VERSION 5.8 ;
BUSBITCHARS "[]" ;
DIVIDERCHAR "/" ;
UNITS
    DATABASE MICRONS 1000 ;
END UNITS

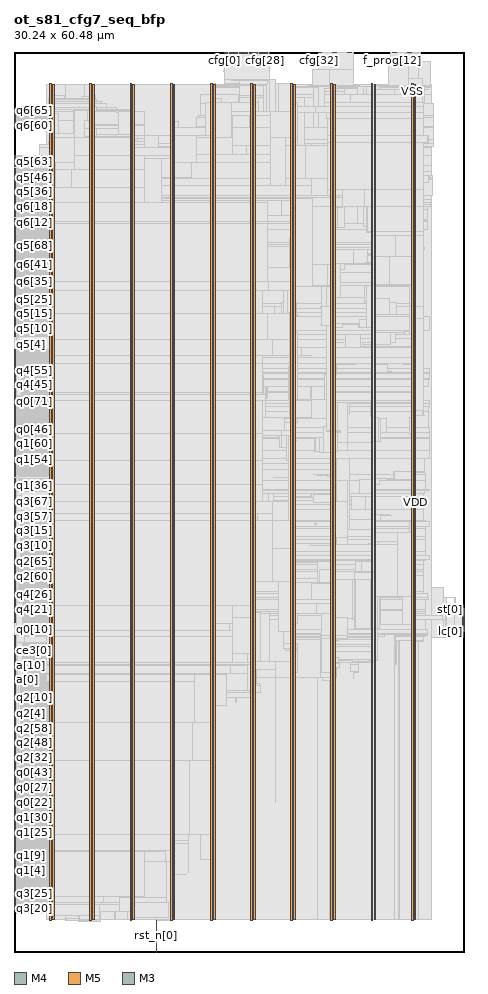
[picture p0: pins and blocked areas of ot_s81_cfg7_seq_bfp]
MACRO ot_s81_cfg7_seq_bfp
  FOREIGN ot_s81_cfg7_seq_bfp 0 0 ;
  CLASS BLOCK ;
  SIZE 30.24 BY 60.48 ;
  PIN a[0]
    DIRECTION OUTPUT ;
    USE SIGNAL ;
    PORT
      LAYER M4 ;
        RECT  0 18.288 0.084 18.312 ;
    END
  END a[0]
  PIN a[10]
    DIRECTION OUTPUT ;
    USE SIGNAL ;
    PORT
      LAYER M4 ;
        RECT  0 19.248 0.084 19.272 ;
    END
  END a[10]
  PIN a[11]
    DIRECTION OUTPUT ;
    USE SIGNAL ;
    PORT
      LAYER M4 ;
        RECT  0 19.344 0.084 19.368 ;
    END
  END a[11]
  PIN a[1]
    DIRECTION OUTPUT ;
    USE SIGNAL ;
    PORT
      LAYER M4 ;
        RECT  0 18.384 0.084 18.408 ;
    END
  END a[1]
  PIN a[2]
    DIRECTION OUTPUT ;
    USE SIGNAL ;
    PORT
      LAYER M4 ;
        RECT  0 18.48 0.084 18.504 ;
    END
  END a[2]
  PIN a[3]
    DIRECTION OUTPUT ;
    USE SIGNAL ;
    PORT
      LAYER M4 ;
        RECT  0 18.576 0.084 18.6 ;
    END
  END a[3]
  PIN a[4]
    DIRECTION OUTPUT ;
    USE SIGNAL ;
    PORT
      LAYER M4 ;
        RECT  0 18.672 0.084 18.696 ;
    END
  END a[4]
  PIN a[5]
    DIRECTION OUTPUT ;
    USE SIGNAL ;
    PORT
      LAYER M4 ;
        RECT  0 18.768 0.084 18.792 ;
    END
  END a[5]
  PIN a[6]
    DIRECTION OUTPUT ;
    USE SIGNAL ;
    PORT
      LAYER M4 ;
        RECT  0 18.864 0.084 18.888 ;
    END
  END a[6]
  PIN a[7]
    DIRECTION OUTPUT ;
    USE SIGNAL ;
    PORT
      LAYER M4 ;
        RECT  0 18.96 0.084 18.984 ;
    END
  END a[7]
  PIN a[8]
    DIRECTION OUTPUT ;
    USE SIGNAL ;
    PORT
      LAYER M4 ;
        RECT  0 19.056 0.084 19.08 ;
    END
  END a[8]
  PIN a[9]
    DIRECTION OUTPUT ;
    USE SIGNAL ;
    PORT
      LAYER M4 ;
        RECT  0 19.152 0.084 19.176 ;
    END
  END a[9]
  PIN ce0[0]
    DIRECTION OUTPUT ;
    USE SIGNAL ;
    PORT
      LAYER M4 ;
        RECT  0 19.44 0.084 19.464 ;
    END
  END ce0[0]
  PIN ce1[0]
    DIRECTION OUTPUT ;
    USE SIGNAL ;
    PORT
      LAYER M4 ;
        RECT  0 19.536 0.084 19.56 ;
    END
  END ce1[0]
  PIN ce2[0]
    DIRECTION OUTPUT ;
    USE SIGNAL ;
    PORT
      LAYER M4 ;
        RECT  0 19.632 0.084 19.656 ;
    END
  END ce2[0]
  PIN ce3[0]
    DIRECTION OUTPUT ;
    USE SIGNAL ;
    PORT
      LAYER M4 ;
        RECT  0 19.728 0.084 19.752 ;
    END
  END ce3[0]
  PIN ce4[0]
    DIRECTION OUTPUT ;
    USE SIGNAL ;
    PORT
      LAYER M4 ;
        RECT  0 19.824 0.084 19.848 ;
    END
  END ce4[0]
  PIN ce5[0]
    DIRECTION OUTPUT ;
    USE SIGNAL ;
    PORT
      LAYER M4 ;
        RECT  0 19.92 0.084 19.944 ;
    END
  END ce5[0]
  PIN ce6[0]
    DIRECTION OUTPUT ;
    USE SIGNAL ;
    PORT
      LAYER M4 ;
        RECT  0 20.016 0.084 20.04 ;
    END
  END ce6[0]
  PIN cfg[0]
    DIRECTION OUTPUT ;
    USE SIGNAL ;
    PORT
      LAYER M5 ;
        RECT  14.16 60.396 14.184 60.48 ;
    END
  END cfg[0]
  PIN cfg[10]
    DIRECTION OUTPUT ;
    USE SIGNAL ;
    PORT
      LAYER M5 ;
        RECT  15.12 60.396 15.144 60.48 ;
    END
  END cfg[10]
  PIN cfg[11]
    DIRECTION OUTPUT ;
    USE SIGNAL ;
    PORT
      LAYER M5 ;
        RECT  15.216 60.396 15.24 60.48 ;
    END
  END cfg[11]
  PIN cfg[12]
    DIRECTION OUTPUT ;
    USE SIGNAL ;
    PORT
      LAYER M5 ;
        RECT  15.312 60.396 15.336 60.48 ;
    END
  END cfg[12]
  PIN cfg[13]
    DIRECTION OUTPUT ;
    USE SIGNAL ;
    PORT
      LAYER M5 ;
        RECT  15.408 60.396 15.432 60.48 ;
    END
  END cfg[13]
  PIN cfg[14]
    DIRECTION OUTPUT ;
    USE SIGNAL ;
    PORT
      LAYER M5 ;
        RECT  15.504 60.396 15.528 60.48 ;
    END
  END cfg[14]
  PIN cfg[15]
    DIRECTION OUTPUT ;
    USE SIGNAL ;
    PORT
      LAYER M5 ;
        RECT  15.6 60.396 15.624 60.48 ;
    END
  END cfg[15]
  PIN cfg[16]
    DIRECTION OUTPUT ;
    USE SIGNAL ;
    PORT
      LAYER M5 ;
        RECT  15.696 60.396 15.72 60.48 ;
    END
  END cfg[16]
  PIN cfg[17]
    DIRECTION OUTPUT ;
    USE SIGNAL ;
    PORT
      LAYER M5 ;
        RECT  15.792 60.396 15.816 60.48 ;
    END
  END cfg[17]
  PIN cfg[18]
    DIRECTION OUTPUT ;
    USE SIGNAL ;
    PORT
      LAYER M5 ;
        RECT  15.888 60.396 15.912 60.48 ;
    END
  END cfg[18]
  PIN cfg[19]
    DIRECTION OUTPUT ;
    USE SIGNAL ;
    PORT
      LAYER M5 ;
        RECT  15.984 60.396 16.008 60.48 ;
    END
  END cfg[19]
  PIN cfg[1]
    DIRECTION OUTPUT ;
    USE SIGNAL ;
    PORT
      LAYER M5 ;
        RECT  14.256 60.396 14.28 60.48 ;
    END
  END cfg[1]
  PIN cfg[20]
    DIRECTION OUTPUT ;
    USE SIGNAL ;
    PORT
      LAYER M5 ;
        RECT  16.08 60.396 16.104 60.48 ;
    END
  END cfg[20]
  PIN cfg[21]
    DIRECTION OUTPUT ;
    USE SIGNAL ;
    PORT
      LAYER M5 ;
        RECT  16.176 60.396 16.2 60.48 ;
    END
  END cfg[21]
  PIN cfg[22]
    DIRECTION OUTPUT ;
    USE SIGNAL ;
    PORT
      LAYER M5 ;
        RECT  16.272 60.396 16.296 60.48 ;
    END
  END cfg[22]
  PIN cfg[23]
    DIRECTION OUTPUT ;
    USE SIGNAL ;
    PORT
      LAYER M5 ;
        RECT  16.368 60.396 16.392 60.48 ;
    END
  END cfg[23]
  PIN cfg[24]
    DIRECTION OUTPUT ;
    USE SIGNAL ;
    PORT
      LAYER M5 ;
        RECT  16.464 60.396 16.488 60.48 ;
    END
  END cfg[24]
  PIN cfg[25]
    DIRECTION OUTPUT ;
    USE SIGNAL ;
    PORT
      LAYER M5 ;
        RECT  16.56 60.396 16.584 60.48 ;
    END
  END cfg[25]
  PIN cfg[26]
    DIRECTION OUTPUT ;
    USE SIGNAL ;
    PORT
      LAYER M5 ;
        RECT  16.656 60.396 16.68 60.48 ;
    END
  END cfg[26]
  PIN cfg[27]
    DIRECTION OUTPUT ;
    USE SIGNAL ;
    PORT
      LAYER M5 ;
        RECT  16.752 60.396 16.776 60.48 ;
    END
  END cfg[27]
  PIN cfg[28]
    DIRECTION OUTPUT ;
    USE SIGNAL ;
    PORT
      LAYER M5 ;
        RECT  16.848 60.396 16.872 60.48 ;
    END
  END cfg[28]
  PIN cfg[29]
    DIRECTION OUTPUT ;
    USE SIGNAL ;
    PORT
      LAYER M5 ;
        RECT  16.944 60.396 16.968 60.48 ;
    END
  END cfg[29]
  PIN cfg[2]
    DIRECTION OUTPUT ;
    USE SIGNAL ;
    PORT
      LAYER M5 ;
        RECT  14.352 60.396 14.376 60.48 ;
    END
  END cfg[2]
  PIN cfg[30]
    DIRECTION OUTPUT ;
    USE SIGNAL ;
    PORT
      LAYER M5 ;
        RECT  17.04 60.396 17.064 60.48 ;
    END
  END cfg[30]
  PIN cfg[31]
    DIRECTION OUTPUT ;
    USE SIGNAL ;
    PORT
      LAYER M5 ;
        RECT  17.136 60.396 17.16 60.48 ;
    END
  END cfg[31]
  PIN cfg[32]
    DIRECTION OUTPUT ;
    USE SIGNAL ;
    PORT
      LAYER M3 ;
        RECT  20.484 60.443 20.502 60.48 ;
    END
  END cfg[32]
  PIN cfg[33]
    DIRECTION OUTPUT ;
    USE SIGNAL ;
    PORT
      LAYER M3 ;
        RECT  20.556 60.443 20.574 60.48 ;
    END
  END cfg[33]
  PIN cfg[34]
    DIRECTION OUTPUT ;
    USE SIGNAL ;
    PORT
      LAYER M3 ;
        RECT  20.628 60.443 20.646 60.48 ;
    END
  END cfg[34]
  PIN cfg[35]
    DIRECTION OUTPUT ;
    USE SIGNAL ;
    PORT
      LAYER M3 ;
        RECT  20.7 60.443 20.718 60.48 ;
    END
  END cfg[35]
  PIN cfg[36]
    DIRECTION OUTPUT ;
    USE SIGNAL ;
    PORT
      LAYER M3 ;
        RECT  20.772 60.443 20.79 60.48 ;
    END
  END cfg[36]
  PIN cfg[37]
    DIRECTION OUTPUT ;
    USE SIGNAL ;
    PORT
      LAYER M3 ;
        RECT  20.844 60.443 20.862 60.48 ;
    END
  END cfg[37]
  PIN cfg[38]
    DIRECTION OUTPUT ;
    USE SIGNAL ;
    PORT
      LAYER M3 ;
        RECT  20.916 60.443 20.934 60.48 ;
    END
  END cfg[38]
  PIN cfg[39]
    DIRECTION OUTPUT ;
    USE SIGNAL ;
    PORT
      LAYER M3 ;
        RECT  20.988 60.443 21.006 60.48 ;
    END
  END cfg[39]
  PIN cfg[3]
    DIRECTION OUTPUT ;
    USE SIGNAL ;
    PORT
      LAYER M5 ;
        RECT  14.448 60.396 14.472 60.48 ;
    END
  END cfg[3]
  PIN cfg[40]
    DIRECTION OUTPUT ;
    USE SIGNAL ;
    PORT
      LAYER M3 ;
        RECT  21.06 60.443 21.078 60.48 ;
    END
  END cfg[40]
  PIN cfg[41]
    DIRECTION OUTPUT ;
    USE SIGNAL ;
    PORT
      LAYER M3 ;
        RECT  21.132 60.443 21.15 60.48 ;
    END
  END cfg[41]
  PIN cfg[42]
    DIRECTION OUTPUT ;
    USE SIGNAL ;
    PORT
      LAYER M3 ;
        RECT  21.204 60.443 21.222 60.48 ;
    END
  END cfg[42]
  PIN cfg[43]
    DIRECTION OUTPUT ;
    USE SIGNAL ;
    PORT
      LAYER M3 ;
        RECT  21.276 60.443 21.294 60.48 ;
    END
  END cfg[43]
  PIN cfg[44]
    DIRECTION OUTPUT ;
    USE SIGNAL ;
    PORT
      LAYER M3 ;
        RECT  21.348 60.443 21.366 60.48 ;
    END
  END cfg[44]
  PIN cfg[45]
    DIRECTION OUTPUT ;
    USE SIGNAL ;
    PORT
      LAYER M3 ;
        RECT  21.42 60.443 21.438 60.48 ;
    END
  END cfg[45]
  PIN cfg[46]
    DIRECTION OUTPUT ;
    USE SIGNAL ;
    PORT
      LAYER M3 ;
        RECT  21.492 60.443 21.51 60.48 ;
    END
  END cfg[46]
  PIN cfg[47]
    DIRECTION OUTPUT ;
    USE SIGNAL ;
    PORT
      LAYER M3 ;
        RECT  21.564 60.443 21.582 60.48 ;
    END
  END cfg[47]
  PIN cfg[48]
    DIRECTION OUTPUT ;
    USE SIGNAL ;
    PORT
      LAYER M3 ;
        RECT  21.636 60.443 21.654 60.48 ;
    END
  END cfg[48]
  PIN cfg[49]
    DIRECTION OUTPUT ;
    USE SIGNAL ;
    PORT
      LAYER M3 ;
        RECT  21.708 60.443 21.726 60.48 ;
    END
  END cfg[49]
  PIN cfg[4]
    DIRECTION OUTPUT ;
    USE SIGNAL ;
    PORT
      LAYER M5 ;
        RECT  14.544 60.396 14.568 60.48 ;
    END
  END cfg[4]
  PIN cfg[50]
    DIRECTION OUTPUT ;
    USE SIGNAL ;
    PORT
      LAYER M3 ;
        RECT  21.78 60.443 21.798 60.48 ;
    END
  END cfg[50]
  PIN cfg[51]
    DIRECTION OUTPUT ;
    USE SIGNAL ;
    PORT
      LAYER M3 ;
        RECT  21.852 60.443 21.87 60.48 ;
    END
  END cfg[51]
  PIN cfg[52]
    DIRECTION OUTPUT ;
    USE SIGNAL ;
    PORT
      LAYER M3 ;
        RECT  21.924 60.443 21.942 60.48 ;
    END
  END cfg[52]
  PIN cfg[53]
    DIRECTION OUTPUT ;
    USE SIGNAL ;
    PORT
      LAYER M3 ;
        RECT  21.996 60.443 22.014 60.48 ;
    END
  END cfg[53]
  PIN cfg[5]
    DIRECTION OUTPUT ;
    USE SIGNAL ;
    PORT
      LAYER M5 ;
        RECT  14.64 60.396 14.664 60.48 ;
    END
  END cfg[5]
  PIN cfg[6]
    DIRECTION OUTPUT ;
    USE SIGNAL ;
    PORT
      LAYER M5 ;
        RECT  14.736 60.396 14.76 60.48 ;
    END
  END cfg[6]
  PIN cfg[7]
    DIRECTION OUTPUT ;
    USE SIGNAL ;
    PORT
      LAYER M5 ;
        RECT  14.832 60.396 14.856 60.48 ;
    END
  END cfg[7]
  PIN cfg[8]
    DIRECTION OUTPUT ;
    USE SIGNAL ;
    PORT
      LAYER M5 ;
        RECT  14.928 60.396 14.952 60.48 ;
    END
  END cfg[8]
  PIN cfg[9]
    DIRECTION OUTPUT ;
    USE SIGNAL ;
    PORT
      LAYER M5 ;
        RECT  15.024 60.396 15.048 60.48 ;
    END
  END cfg[9]
  PIN clk[0]
    DIRECTION INPUT ;
    USE SIGNAL ;
    PORT
      LAYER M4 ;
        RECT  0 20.112 0.084 20.136 ;
    END
  END clk[0]
  PIN f_prog[0]
    DIRECTION OUTPUT ;
    USE SIGNAL ;
    PORT
      LAYER M3 ;
        RECT  22.068 60.443 22.086 60.48 ;
    END
  END f_prog[0]
  PIN f_prog[10]
    DIRECTION OUTPUT ;
    USE SIGNAL ;
    PORT
      LAYER M3 ;
        RECT  25.308 60.443 25.326 60.48 ;
    END
  END f_prog[10]
  PIN f_prog[11]
    DIRECTION OUTPUT ;
    USE SIGNAL ;
    PORT
      LAYER M3 ;
        RECT  25.38 60.443 25.398 60.48 ;
    END
  END f_prog[11]
  PIN f_prog[12]
    DIRECTION OUTPUT ;
    USE SIGNAL ;
    PORT
      LAYER M3 ;
        RECT  25.452 60.443 25.47 60.48 ;
    END
  END f_prog[12]
  PIN f_prog[13]
    DIRECTION OUTPUT ;
    USE SIGNAL ;
    PORT
      LAYER M3 ;
        RECT  25.524 60.443 25.542 60.48 ;
    END
  END f_prog[13]
  PIN f_prog[14]
    DIRECTION OUTPUT ;
    USE SIGNAL ;
    PORT
      LAYER M3 ;
        RECT  25.596 60.443 25.614 60.48 ;
    END
  END f_prog[14]
  PIN f_prog[15]
    DIRECTION OUTPUT ;
    USE SIGNAL ;
    PORT
      LAYER M3 ;
        RECT  25.668 60.443 25.686 60.48 ;
    END
  END f_prog[15]
  PIN f_prog[16]
    DIRECTION OUTPUT ;
    USE SIGNAL ;
    PORT
      LAYER M3 ;
        RECT  25.74 60.443 25.758 60.48 ;
    END
  END f_prog[16]
  PIN f_prog[17]
    DIRECTION OUTPUT ;
    USE SIGNAL ;
    PORT
      LAYER M3 ;
        RECT  25.812 60.443 25.83 60.48 ;
    END
  END f_prog[17]
  PIN f_prog[18]
    DIRECTION OUTPUT ;
    USE SIGNAL ;
    PORT
      LAYER M3 ;
        RECT  25.884 60.443 25.902 60.48 ;
    END
  END f_prog[18]
  PIN f_prog[19]
    DIRECTION OUTPUT ;
    USE SIGNAL ;
    PORT
      LAYER M3 ;
        RECT  25.956 60.443 25.974 60.48 ;
    END
  END f_prog[19]
  PIN f_prog[1]
    DIRECTION OUTPUT ;
    USE SIGNAL ;
    PORT
      LAYER M3 ;
        RECT  22.14 60.443 22.158 60.48 ;
    END
  END f_prog[1]
  PIN f_prog[20]
    DIRECTION OUTPUT ;
    USE SIGNAL ;
    PORT
      LAYER M3 ;
        RECT  26.028 60.443 26.046 60.48 ;
    END
  END f_prog[20]
  PIN f_prog[21]
    DIRECTION OUTPUT ;
    USE SIGNAL ;
    PORT
      LAYER M3 ;
        RECT  26.1 60.443 26.118 60.48 ;
    END
  END f_prog[21]
  PIN f_prog[22]
    DIRECTION OUTPUT ;
    USE SIGNAL ;
    PORT
      LAYER M3 ;
        RECT  26.172 60.443 26.19 60.48 ;
    END
  END f_prog[22]
  PIN f_prog[23]
    DIRECTION OUTPUT ;
    USE SIGNAL ;
    PORT
      LAYER M3 ;
        RECT  26.244 60.443 26.262 60.48 ;
    END
  END f_prog[23]
  PIN f_prog[24]
    DIRECTION OUTPUT ;
    USE SIGNAL ;
    PORT
      LAYER M3 ;
        RECT  26.316 60.443 26.334 60.48 ;
    END
  END f_prog[24]
  PIN f_prog[25]
    DIRECTION OUTPUT ;
    USE SIGNAL ;
    PORT
      LAYER M3 ;
        RECT  26.388 60.443 26.406 60.48 ;
    END
  END f_prog[25]
  PIN f_prog[26]
    DIRECTION OUTPUT ;
    USE SIGNAL ;
    PORT
      LAYER M3 ;
        RECT  26.46 60.443 26.478 60.48 ;
    END
  END f_prog[26]
  PIN f_prog[27]
    DIRECTION OUTPUT ;
    USE SIGNAL ;
    PORT
      LAYER M3 ;
        RECT  26.532 60.443 26.55 60.48 ;
    END
  END f_prog[27]
  PIN f_prog[28]
    DIRECTION OUTPUT ;
    USE SIGNAL ;
    PORT
      LAYER M3 ;
        RECT  26.604 60.443 26.622 60.48 ;
    END
  END f_prog[28]
  PIN f_prog[29]
    DIRECTION OUTPUT ;
    USE SIGNAL ;
    PORT
      LAYER M3 ;
        RECT  26.676 60.443 26.694 60.48 ;
    END
  END f_prog[29]
  PIN f_prog[2]
    DIRECTION OUTPUT ;
    USE SIGNAL ;
    PORT
      LAYER M3 ;
        RECT  22.212 60.443 22.23 60.48 ;
    END
  END f_prog[2]
  PIN f_prog[30]
    DIRECTION OUTPUT ;
    USE SIGNAL ;
    PORT
      LAYER M3 ;
        RECT  26.748 60.443 26.766 60.48 ;
    END
  END f_prog[30]
  PIN f_prog[31]
    DIRECTION OUTPUT ;
    USE SIGNAL ;
    PORT
      LAYER M3 ;
        RECT  26.82 60.443 26.838 60.48 ;
    END
  END f_prog[31]
  PIN f_prog[32]
    DIRECTION OUTPUT ;
    USE SIGNAL ;
    PORT
      LAYER M3 ;
        RECT  26.892 60.443 26.91 60.48 ;
    END
  END f_prog[32]
  PIN f_prog[33]
    DIRECTION OUTPUT ;
    USE SIGNAL ;
    PORT
      LAYER M3 ;
        RECT  26.964 60.443 26.982 60.48 ;
    END
  END f_prog[33]
  PIN f_prog[34]
    DIRECTION OUTPUT ;
    USE SIGNAL ;
    PORT
      LAYER M3 ;
        RECT  27.036 60.443 27.054 60.48 ;
    END
  END f_prog[34]
  PIN f_prog[35]
    DIRECTION OUTPUT ;
    USE SIGNAL ;
    PORT
      LAYER M3 ;
        RECT  27.108 60.443 27.126 60.48 ;
    END
  END f_prog[35]
  PIN f_prog[36]
    DIRECTION OUTPUT ;
    USE SIGNAL ;
    PORT
      LAYER M3 ;
        RECT  27.18 60.443 27.198 60.48 ;
    END
  END f_prog[36]
  PIN f_prog[37]
    DIRECTION OUTPUT ;
    USE SIGNAL ;
    PORT
      LAYER M3 ;
        RECT  27.252 60.443 27.27 60.48 ;
    END
  END f_prog[37]
  PIN f_prog[3]
    DIRECTION OUTPUT ;
    USE SIGNAL ;
    PORT
      LAYER M3 ;
        RECT  22.284 60.443 22.302 60.48 ;
    END
  END f_prog[3]
  PIN f_prog[4]
    DIRECTION OUTPUT ;
    USE SIGNAL ;
    PORT
      LAYER M3 ;
        RECT  22.356 60.443 22.374 60.48 ;
    END
  END f_prog[4]
  PIN f_prog[5]
    DIRECTION OUTPUT ;
    USE SIGNAL ;
    PORT
      LAYER M3 ;
        RECT  22.428 60.443 22.446 60.48 ;
    END
  END f_prog[5]
  PIN f_prog[6]
    DIRECTION OUTPUT ;
    USE SIGNAL ;
    PORT
      LAYER M3 ;
        RECT  22.5 60.443 22.518 60.48 ;
    END
  END f_prog[6]
  PIN f_prog[7]
    DIRECTION OUTPUT ;
    USE SIGNAL ;
    PORT
      LAYER M3 ;
        RECT  22.572 60.443 22.59 60.48 ;
    END
  END f_prog[7]
  PIN f_prog[8]
    DIRECTION OUTPUT ;
    USE SIGNAL ;
    PORT
      LAYER M3 ;
        RECT  22.644 60.443 22.662 60.48 ;
    END
  END f_prog[8]
  PIN f_prog[9]
    DIRECTION OUTPUT ;
    USE SIGNAL ;
    PORT
      LAYER M3 ;
        RECT  22.716 60.443 22.734 60.48 ;
    END
  END f_prog[9]
  PIN go_e[0]
    DIRECTION OUTPUT ;
    USE SIGNAL ;
    PORT
      LAYER M3 ;
        RECT  27.324 60.443 27.342 60.48 ;
    END
  END go_e[0]
  PIN lc[0]
    DIRECTION INPUT ;
    USE SIGNAL ;
    PORT
      LAYER M4 ;
        RECT  30.156 21.552 30.24 21.576 ;
    END
  END lc[0]
  PIN lc[10]
    DIRECTION INPUT ;
    USE SIGNAL ;
    PORT
      LAYER M4 ;
        RECT  30.156 22.512 30.24 22.536 ;
    END
  END lc[10]
  PIN lc[11]
    DIRECTION INPUT ;
    USE SIGNAL ;
    PORT
      LAYER M4 ;
        RECT  30.156 22.608 30.24 22.632 ;
    END
  END lc[11]
  PIN lc[12]
    DIRECTION INPUT ;
    USE SIGNAL ;
    PORT
      LAYER M4 ;
        RECT  30.156 22.704 30.24 22.728 ;
    END
  END lc[12]
  PIN lc[13]
    DIRECTION INPUT ;
    USE SIGNAL ;
    PORT
      LAYER M4 ;
        RECT  30.156 22.8 30.24 22.824 ;
    END
  END lc[13]
  PIN lc[14]
    DIRECTION INPUT ;
    USE SIGNAL ;
    PORT
      LAYER M4 ;
        RECT  30.156 22.896 30.24 22.92 ;
    END
  END lc[14]
  PIN lc[1]
    DIRECTION INPUT ;
    USE SIGNAL ;
    PORT
      LAYER M4 ;
        RECT  30.156 21.648 30.24 21.672 ;
    END
  END lc[1]
  PIN lc[2]
    DIRECTION INPUT ;
    USE SIGNAL ;
    PORT
      LAYER M4 ;
        RECT  30.156 21.744 30.24 21.768 ;
    END
  END lc[2]
  PIN lc[3]
    DIRECTION INPUT ;
    USE SIGNAL ;
    PORT
      LAYER M4 ;
        RECT  30.156 21.84 30.24 21.864 ;
    END
  END lc[3]
  PIN lc[4]
    DIRECTION INPUT ;
    USE SIGNAL ;
    PORT
      LAYER M4 ;
        RECT  30.156 21.936 30.24 21.96 ;
    END
  END lc[4]
  PIN lc[5]
    DIRECTION INPUT ;
    USE SIGNAL ;
    PORT
      LAYER M4 ;
        RECT  30.156 22.032 30.24 22.056 ;
    END
  END lc[5]
  PIN lc[6]
    DIRECTION INPUT ;
    USE SIGNAL ;
    PORT
      LAYER M4 ;
        RECT  30.156 22.128 30.24 22.152 ;
    END
  END lc[6]
  PIN lc[7]
    DIRECTION INPUT ;
    USE SIGNAL ;
    PORT
      LAYER M4 ;
        RECT  30.156 22.224 30.24 22.248 ;
    END
  END lc[7]
  PIN lc[8]
    DIRECTION INPUT ;
    USE SIGNAL ;
    PORT
      LAYER M4 ;
        RECT  30.156 22.32 30.24 22.344 ;
    END
  END lc[8]
  PIN lc[9]
    DIRECTION INPUT ;
    USE SIGNAL ;
    PORT
      LAYER M4 ;
        RECT  30.156 22.416 30.24 22.44 ;
    END
  END lc[9]
  PIN q0[0]
    DIRECTION INPUT ;
    USE SIGNAL ;
    PORT
      LAYER M4 ;
        RECT  0 20.208 0.084 20.232 ;
    END
  END q0[0]
  PIN q0[10]
    DIRECTION INPUT ;
    USE SIGNAL ;
    PORT
      LAYER M4 ;
        RECT  0 21.168 0.084 21.192 ;
    END
  END q0[10]
  PIN q0[11]
    DIRECTION INPUT ;
    USE SIGNAL ;
    PORT
      LAYER M4 ;
        RECT  0 21.264 0.084 21.288 ;
    END
  END q0[11]
  PIN q0[12]
    DIRECTION INPUT ;
    USE SIGNAL ;
    PORT
      LAYER M4 ;
        RECT  0 9.072 0.084 9.096 ;
    END
  END q0[12]
  PIN q0[13]
    DIRECTION INPUT ;
    USE SIGNAL ;
    PORT
      LAYER M4 ;
        RECT  0 9.168 0.084 9.192 ;
    END
  END q0[13]
  PIN q0[14]
    DIRECTION INPUT ;
    USE SIGNAL ;
    PORT
      LAYER M4 ;
        RECT  0 9.264 0.084 9.288 ;
    END
  END q0[14]
  PIN q0[15]
    DIRECTION INPUT ;
    USE SIGNAL ;
    PORT
      LAYER M4 ;
        RECT  0 9.36 0.084 9.384 ;
    END
  END q0[15]
  PIN q0[16]
    DIRECTION INPUT ;
    USE SIGNAL ;
    PORT
      LAYER M4 ;
        RECT  0 9.456 0.084 9.48 ;
    END
  END q0[16]
  PIN q0[17]
    DIRECTION INPUT ;
    USE SIGNAL ;
    PORT
      LAYER M4 ;
        RECT  0 9.552 0.084 9.576 ;
    END
  END q0[17]
  PIN q0[18]
    DIRECTION INPUT ;
    USE SIGNAL ;
    PORT
      LAYER M4 ;
        RECT  0 9.648 0.084 9.672 ;
    END
  END q0[18]
  PIN q0[19]
    DIRECTION INPUT ;
    USE SIGNAL ;
    PORT
      LAYER M4 ;
        RECT  0 9.744 0.084 9.768 ;
    END
  END q0[19]
  PIN q0[1]
    DIRECTION INPUT ;
    USE SIGNAL ;
    PORT
      LAYER M4 ;
        RECT  0 20.304 0.084 20.328 ;
    END
  END q0[1]
  PIN q0[20]
    DIRECTION INPUT ;
    USE SIGNAL ;
    PORT
      LAYER M4 ;
        RECT  0 9.84 0.084 9.864 ;
    END
  END q0[20]
  PIN q0[21]
    DIRECTION INPUT ;
    USE SIGNAL ;
    PORT
      LAYER M4 ;
        RECT  0 9.936 0.084 9.96 ;
    END
  END q0[21]
  PIN q0[22]
    DIRECTION INPUT ;
    USE SIGNAL ;
    PORT
      LAYER M4 ;
        RECT  0 10.032 0.084 10.056 ;
    END
  END q0[22]
  PIN q0[23]
    DIRECTION INPUT ;
    USE SIGNAL ;
    PORT
      LAYER M4 ;
        RECT  0 10.128 0.084 10.152 ;
    END
  END q0[23]
  PIN q0[24]
    DIRECTION INPUT ;
    USE SIGNAL ;
    PORT
      LAYER M4 ;
        RECT  0 10.224 0.084 10.248 ;
    END
  END q0[24]
  PIN q0[25]
    DIRECTION INPUT ;
    USE SIGNAL ;
    PORT
      LAYER M4 ;
        RECT  0 10.32 0.084 10.344 ;
    END
  END q0[25]
  PIN q0[26]
    DIRECTION INPUT ;
    USE SIGNAL ;
    PORT
      LAYER M4 ;
        RECT  0 10.416 0.084 10.44 ;
    END
  END q0[26]
  PIN q0[27]
    DIRECTION INPUT ;
    USE SIGNAL ;
    PORT
      LAYER M4 ;
        RECT  0 10.512 0.084 10.536 ;
    END
  END q0[27]
  PIN q0[28]
    DIRECTION INPUT ;
    USE SIGNAL ;
    PORT
      LAYER M4 ;
        RECT  0 10.608 0.084 10.632 ;
    END
  END q0[28]
  PIN q0[29]
    DIRECTION INPUT ;
    USE SIGNAL ;
    PORT
      LAYER M4 ;
        RECT  0 10.704 0.084 10.728 ;
    END
  END q0[29]
  PIN q0[2]
    DIRECTION INPUT ;
    USE SIGNAL ;
    PORT
      LAYER M4 ;
        RECT  0 20.4 0.084 20.424 ;
    END
  END q0[2]
  PIN q0[30]
    DIRECTION INPUT ;
    USE SIGNAL ;
    PORT
      LAYER M4 ;
        RECT  0 10.8 0.084 10.824 ;
    END
  END q0[30]
  PIN q0[31]
    DIRECTION INPUT ;
    USE SIGNAL ;
    PORT
      LAYER M4 ;
        RECT  0 10.896 0.084 10.92 ;
    END
  END q0[31]
  PIN q0[32]
    DIRECTION INPUT ;
    USE SIGNAL ;
    PORT
      LAYER M4 ;
        RECT  0 10.992 0.084 11.016 ;
    END
  END q0[32]
  PIN q0[33]
    DIRECTION INPUT ;
    USE SIGNAL ;
    PORT
      LAYER M4 ;
        RECT  0 11.088 0.084 11.112 ;
    END
  END q0[33]
  PIN q0[34]
    DIRECTION INPUT ;
    USE SIGNAL ;
    PORT
      LAYER M4 ;
        RECT  0 11.184 0.084 11.208 ;
    END
  END q0[34]
  PIN q0[35]
    DIRECTION INPUT ;
    USE SIGNAL ;
    PORT
      LAYER M4 ;
        RECT  0 11.28 0.084 11.304 ;
    END
  END q0[35]
  PIN q0[36]
    DIRECTION INPUT ;
    USE SIGNAL ;
    PORT
      LAYER M4 ;
        RECT  0 11.376 0.084 11.4 ;
    END
  END q0[36]
  PIN q0[37]
    DIRECTION INPUT ;
    USE SIGNAL ;
    PORT
      LAYER M4 ;
        RECT  0 11.472 0.084 11.496 ;
    END
  END q0[37]
  PIN q0[38]
    DIRECTION INPUT ;
    USE SIGNAL ;
    PORT
      LAYER M4 ;
        RECT  0 11.568 0.084 11.592 ;
    END
  END q0[38]
  PIN q0[39]
    DIRECTION INPUT ;
    USE SIGNAL ;
    PORT
      LAYER M4 ;
        RECT  0 11.664 0.084 11.688 ;
    END
  END q0[39]
  PIN q0[3]
    DIRECTION INPUT ;
    USE SIGNAL ;
    PORT
      LAYER M4 ;
        RECT  0 20.496 0.084 20.52 ;
    END
  END q0[3]
  PIN q0[40]
    DIRECTION INPUT ;
    USE SIGNAL ;
    PORT
      LAYER M4 ;
        RECT  0 11.76 0.084 11.784 ;
    END
  END q0[40]
  PIN q0[41]
    DIRECTION INPUT ;
    USE SIGNAL ;
    PORT
      LAYER M4 ;
        RECT  0 11.856 0.084 11.88 ;
    END
  END q0[41]
  PIN q0[42]
    DIRECTION INPUT ;
    USE SIGNAL ;
    PORT
      LAYER M4 ;
        RECT  0 11.952 0.084 11.976 ;
    END
  END q0[42]
  PIN q0[43]
    DIRECTION INPUT ;
    USE SIGNAL ;
    PORT
      LAYER M4 ;
        RECT  0 12.048 0.084 12.072 ;
    END
  END q0[43]
  PIN q0[44]
    DIRECTION INPUT ;
    USE SIGNAL ;
    PORT
      LAYER M4 ;
        RECT  0 34.416 0.084 34.44 ;
    END
  END q0[44]
  PIN q0[45]
    DIRECTION INPUT ;
    USE SIGNAL ;
    PORT
      LAYER M4 ;
        RECT  0 34.512 0.084 34.536 ;
    END
  END q0[45]
  PIN q0[46]
    DIRECTION INPUT ;
    USE SIGNAL ;
    PORT
      LAYER M4 ;
        RECT  0 34.608 0.084 34.632 ;
    END
  END q0[46]
  PIN q0[47]
    DIRECTION INPUT ;
    USE SIGNAL ;
    PORT
      LAYER M4 ;
        RECT  0 34.704 0.084 34.728 ;
    END
  END q0[47]
  PIN q0[48]
    DIRECTION INPUT ;
    USE SIGNAL ;
    PORT
      LAYER M4 ;
        RECT  0 34.8 0.084 34.824 ;
    END
  END q0[48]
  PIN q0[49]
    DIRECTION INPUT ;
    USE SIGNAL ;
    PORT
      LAYER M4 ;
        RECT  0 34.896 0.084 34.92 ;
    END
  END q0[49]
  PIN q0[4]
    DIRECTION INPUT ;
    USE SIGNAL ;
    PORT
      LAYER M4 ;
        RECT  0 20.592 0.084 20.616 ;
    END
  END q0[4]
  PIN q0[50]
    DIRECTION INPUT ;
    USE SIGNAL ;
    PORT
      LAYER M4 ;
        RECT  0 34.992 0.084 35.016 ;
    END
  END q0[50]
  PIN q0[51]
    DIRECTION INPUT ;
    USE SIGNAL ;
    PORT
      LAYER M4 ;
        RECT  0 35.088 0.084 35.112 ;
    END
  END q0[51]
  PIN q0[52]
    DIRECTION INPUT ;
    USE SIGNAL ;
    PORT
      LAYER M4 ;
        RECT  0 35.184 0.084 35.208 ;
    END
  END q0[52]
  PIN q0[53]
    DIRECTION INPUT ;
    USE SIGNAL ;
    PORT
      LAYER M4 ;
        RECT  0 35.28 0.084 35.304 ;
    END
  END q0[53]
  PIN q0[54]
    DIRECTION INPUT ;
    USE SIGNAL ;
    PORT
      LAYER M4 ;
        RECT  0 35.376 0.084 35.4 ;
    END
  END q0[54]
  PIN q0[55]
    DIRECTION INPUT ;
    USE SIGNAL ;
    PORT
      LAYER M4 ;
        RECT  0 35.472 0.084 35.496 ;
    END
  END q0[55]
  PIN q0[56]
    DIRECTION INPUT ;
    USE SIGNAL ;
    PORT
      LAYER M4 ;
        RECT  0 35.568 0.084 35.592 ;
    END
  END q0[56]
  PIN q0[57]
    DIRECTION INPUT ;
    USE SIGNAL ;
    PORT
      LAYER M4 ;
        RECT  0 35.664 0.084 35.688 ;
    END
  END q0[57]
  PIN q0[58]
    DIRECTION INPUT ;
    USE SIGNAL ;
    PORT
      LAYER M4 ;
        RECT  0 35.76 0.084 35.784 ;
    END
  END q0[58]
  PIN q0[59]
    DIRECTION INPUT ;
    USE SIGNAL ;
    PORT
      LAYER M4 ;
        RECT  0 35.856 0.084 35.88 ;
    END
  END q0[59]
  PIN q0[5]
    DIRECTION INPUT ;
    USE SIGNAL ;
    PORT
      LAYER M4 ;
        RECT  0 20.688 0.084 20.712 ;
    END
  END q0[5]
  PIN q0[60]
    DIRECTION INPUT ;
    USE SIGNAL ;
    PORT
      LAYER M4 ;
        RECT  0 35.952 0.084 35.976 ;
    END
  END q0[60]
  PIN q0[61]
    DIRECTION INPUT ;
    USE SIGNAL ;
    PORT
      LAYER M4 ;
        RECT  0 36.048 0.084 36.072 ;
    END
  END q0[61]
  PIN q0[62]
    DIRECTION INPUT ;
    USE SIGNAL ;
    PORT
      LAYER M4 ;
        RECT  0 36.144 0.084 36.168 ;
    END
  END q0[62]
  PIN q0[63]
    DIRECTION INPUT ;
    USE SIGNAL ;
    PORT
      LAYER M4 ;
        RECT  0 36.24 0.084 36.264 ;
    END
  END q0[63]
  PIN q0[64]
    DIRECTION INPUT ;
    USE SIGNAL ;
    PORT
      LAYER M4 ;
        RECT  0 36.336 0.084 36.36 ;
    END
  END q0[64]
  PIN q0[65]
    DIRECTION INPUT ;
    USE SIGNAL ;
    PORT
      LAYER M4 ;
        RECT  0 36.432 0.084 36.456 ;
    END
  END q0[65]
  PIN q0[66]
    DIRECTION INPUT ;
    USE SIGNAL ;
    PORT
      LAYER M4 ;
        RECT  0 36.528 0.084 36.552 ;
    END
  END q0[66]
  PIN q0[67]
    DIRECTION INPUT ;
    USE SIGNAL ;
    PORT
      LAYER M4 ;
        RECT  0 36.624 0.084 36.648 ;
    END
  END q0[67]
  PIN q0[68]
    DIRECTION INPUT ;
    USE SIGNAL ;
    PORT
      LAYER M4 ;
        RECT  0 36.72 0.084 36.744 ;
    END
  END q0[68]
  PIN q0[69]
    DIRECTION INPUT ;
    USE SIGNAL ;
    PORT
      LAYER M4 ;
        RECT  0 36.816 0.084 36.84 ;
    END
  END q0[69]
  PIN q0[6]
    DIRECTION INPUT ;
    USE SIGNAL ;
    PORT
      LAYER M4 ;
        RECT  0 20.784 0.084 20.808 ;
    END
  END q0[6]
  PIN q0[70]
    DIRECTION INPUT ;
    USE SIGNAL ;
    PORT
      LAYER M4 ;
        RECT  0 36.912 0.084 36.936 ;
    END
  END q0[70]
  PIN q0[71]
    DIRECTION INPUT ;
    USE SIGNAL ;
    PORT
      LAYER M4 ;
        RECT  0 37.008 0.084 37.032 ;
    END
  END q0[71]
  PIN q0[7]
    DIRECTION INPUT ;
    USE SIGNAL ;
    PORT
      LAYER M4 ;
        RECT  0 20.88 0.084 20.904 ;
    END
  END q0[7]
  PIN q0[8]
    DIRECTION INPUT ;
    USE SIGNAL ;
    PORT
      LAYER M4 ;
        RECT  0 20.976 0.084 21 ;
    END
  END q0[8]
  PIN q0[9]
    DIRECTION INPUT ;
    USE SIGNAL ;
    PORT
      LAYER M4 ;
        RECT  0 21.072 0.084 21.096 ;
    END
  END q0[9]
  PIN q1[0]
    DIRECTION INPUT ;
    USE SIGNAL ;
    PORT
      LAYER M4 ;
        RECT  0 37.104 0.084 37.128 ;
    END
  END q1[0]
  PIN q1[10]
    DIRECTION INPUT ;
    USE SIGNAL ;
    PORT
      LAYER M4 ;
        RECT  0 6.576 0.084 6.6 ;
    END
  END q1[10]
  PIN q1[11]
    DIRECTION INPUT ;
    USE SIGNAL ;
    PORT
      LAYER M4 ;
        RECT  0 6.672 0.084 6.696 ;
    END
  END q1[11]
  PIN q1[12]
    DIRECTION INPUT ;
    USE SIGNAL ;
    PORT
      LAYER M4 ;
        RECT  0 6.768 0.084 6.792 ;
    END
  END q1[12]
  PIN q1[13]
    DIRECTION INPUT ;
    USE SIGNAL ;
    PORT
      LAYER M4 ;
        RECT  0 6.864 0.084 6.888 ;
    END
  END q1[13]
  PIN q1[14]
    DIRECTION INPUT ;
    USE SIGNAL ;
    PORT
      LAYER M4 ;
        RECT  0 6.96 0.084 6.984 ;
    END
  END q1[14]
  PIN q1[15]
    DIRECTION INPUT ;
    USE SIGNAL ;
    PORT
      LAYER M4 ;
        RECT  0 7.056 0.084 7.08 ;
    END
  END q1[15]
  PIN q1[16]
    DIRECTION INPUT ;
    USE SIGNAL ;
    PORT
      LAYER M4 ;
        RECT  0 7.152 0.084 7.176 ;
    END
  END q1[16]
  PIN q1[17]
    DIRECTION INPUT ;
    USE SIGNAL ;
    PORT
      LAYER M4 ;
        RECT  0 7.248 0.084 7.272 ;
    END
  END q1[17]
  PIN q1[18]
    DIRECTION INPUT ;
    USE SIGNAL ;
    PORT
      LAYER M4 ;
        RECT  0 7.344 0.084 7.368 ;
    END
  END q1[18]
  PIN q1[19]
    DIRECTION INPUT ;
    USE SIGNAL ;
    PORT
      LAYER M4 ;
        RECT  0 7.44 0.084 7.464 ;
    END
  END q1[19]
  PIN q1[1]
    DIRECTION INPUT ;
    USE SIGNAL ;
    PORT
      LAYER M4 ;
        RECT  0 37.2 0.084 37.224 ;
    END
  END q1[1]
  PIN q1[20]
    DIRECTION INPUT ;
    USE SIGNAL ;
    PORT
      LAYER M4 ;
        RECT  0 7.536 0.084 7.56 ;
    END
  END q1[20]
  PIN q1[21]
    DIRECTION INPUT ;
    USE SIGNAL ;
    PORT
      LAYER M4 ;
        RECT  0 7.632 0.084 7.656 ;
    END
  END q1[21]
  PIN q1[22]
    DIRECTION INPUT ;
    USE SIGNAL ;
    PORT
      LAYER M4 ;
        RECT  0 7.728 0.084 7.752 ;
    END
  END q1[22]
  PIN q1[23]
    DIRECTION INPUT ;
    USE SIGNAL ;
    PORT
      LAYER M4 ;
        RECT  0 7.824 0.084 7.848 ;
    END
  END q1[23]
  PIN q1[24]
    DIRECTION INPUT ;
    USE SIGNAL ;
    PORT
      LAYER M4 ;
        RECT  0 7.92 0.084 7.944 ;
    END
  END q1[24]
  PIN q1[25]
    DIRECTION INPUT ;
    USE SIGNAL ;
    PORT
      LAYER M4 ;
        RECT  0 8.016 0.084 8.04 ;
    END
  END q1[25]
  PIN q1[26]
    DIRECTION INPUT ;
    USE SIGNAL ;
    PORT
      LAYER M4 ;
        RECT  0 8.112 0.084 8.136 ;
    END
  END q1[26]
  PIN q1[27]
    DIRECTION INPUT ;
    USE SIGNAL ;
    PORT
      LAYER M4 ;
        RECT  0 8.208 0.084 8.232 ;
    END
  END q1[27]
  PIN q1[28]
    DIRECTION INPUT ;
    USE SIGNAL ;
    PORT
      LAYER M4 ;
        RECT  0 8.304 0.084 8.328 ;
    END
  END q1[28]
  PIN q1[29]
    DIRECTION INPUT ;
    USE SIGNAL ;
    PORT
      LAYER M4 ;
        RECT  0 8.4 0.084 8.424 ;
    END
  END q1[29]
  PIN q1[2]
    DIRECTION INPUT ;
    USE SIGNAL ;
    PORT
      LAYER M4 ;
        RECT  0 37.296 0.084 37.32 ;
    END
  END q1[2]
  PIN q1[30]
    DIRECTION INPUT ;
    USE SIGNAL ;
    PORT
      LAYER M4 ;
        RECT  0 8.496 0.084 8.52 ;
    END
  END q1[30]
  PIN q1[31]
    DIRECTION INPUT ;
    USE SIGNAL ;
    PORT
      LAYER M4 ;
        RECT  0 8.592 0.084 8.616 ;
    END
  END q1[31]
  PIN q1[32]
    DIRECTION INPUT ;
    USE SIGNAL ;
    PORT
      LAYER M4 ;
        RECT  0 8.688 0.084 8.712 ;
    END
  END q1[32]
  PIN q1[33]
    DIRECTION INPUT ;
    USE SIGNAL ;
    PORT
      LAYER M4 ;
        RECT  0 8.784 0.084 8.808 ;
    END
  END q1[33]
  PIN q1[34]
    DIRECTION INPUT ;
    USE SIGNAL ;
    PORT
      LAYER M4 ;
        RECT  0 8.88 0.084 8.904 ;
    END
  END q1[34]
  PIN q1[35]
    DIRECTION INPUT ;
    USE SIGNAL ;
    PORT
      LAYER M4 ;
        RECT  0 8.976 0.084 9 ;
    END
  END q1[35]
  PIN q1[36]
    DIRECTION INPUT ;
    USE SIGNAL ;
    PORT
      LAYER M4 ;
        RECT  0 31.344 0.084 31.368 ;
    END
  END q1[36]
  PIN q1[37]
    DIRECTION INPUT ;
    USE SIGNAL ;
    PORT
      LAYER M4 ;
        RECT  0 31.44 0.084 31.464 ;
    END
  END q1[37]
  PIN q1[38]
    DIRECTION INPUT ;
    USE SIGNAL ;
    PORT
      LAYER M4 ;
        RECT  0 31.536 0.084 31.56 ;
    END
  END q1[38]
  PIN q1[39]
    DIRECTION INPUT ;
    USE SIGNAL ;
    PORT
      LAYER M4 ;
        RECT  0 31.632 0.084 31.656 ;
    END
  END q1[39]
  PIN q1[3]
    DIRECTION INPUT ;
    USE SIGNAL ;
    PORT
      LAYER M4 ;
        RECT  0 37.392 0.084 37.416 ;
    END
  END q1[3]
  PIN q1[40]
    DIRECTION INPUT ;
    USE SIGNAL ;
    PORT
      LAYER M4 ;
        RECT  0 31.728 0.084 31.752 ;
    END
  END q1[40]
  PIN q1[41]
    DIRECTION INPUT ;
    USE SIGNAL ;
    PORT
      LAYER M4 ;
        RECT  0 31.824 0.084 31.848 ;
    END
  END q1[41]
  PIN q1[42]
    DIRECTION INPUT ;
    USE SIGNAL ;
    PORT
      LAYER M4 ;
        RECT  0 31.92 0.084 31.944 ;
    END
  END q1[42]
  PIN q1[43]
    DIRECTION INPUT ;
    USE SIGNAL ;
    PORT
      LAYER M4 ;
        RECT  0 32.016 0.084 32.04 ;
    END
  END q1[43]
  PIN q1[44]
    DIRECTION INPUT ;
    USE SIGNAL ;
    PORT
      LAYER M4 ;
        RECT  0 32.112 0.084 32.136 ;
    END
  END q1[44]
  PIN q1[45]
    DIRECTION INPUT ;
    USE SIGNAL ;
    PORT
      LAYER M4 ;
        RECT  0 32.208 0.084 32.232 ;
    END
  END q1[45]
  PIN q1[46]
    DIRECTION INPUT ;
    USE SIGNAL ;
    PORT
      LAYER M4 ;
        RECT  0 32.304 0.084 32.328 ;
    END
  END q1[46]
  PIN q1[47]
    DIRECTION INPUT ;
    USE SIGNAL ;
    PORT
      LAYER M4 ;
        RECT  0 32.4 0.084 32.424 ;
    END
  END q1[47]
  PIN q1[48]
    DIRECTION INPUT ;
    USE SIGNAL ;
    PORT
      LAYER M4 ;
        RECT  0 32.496 0.084 32.52 ;
    END
  END q1[48]
  PIN q1[49]
    DIRECTION INPUT ;
    USE SIGNAL ;
    PORT
      LAYER M4 ;
        RECT  0 32.592 0.084 32.616 ;
    END
  END q1[49]
  PIN q1[4]
    DIRECTION INPUT ;
    USE SIGNAL ;
    PORT
      LAYER M4 ;
        RECT  0 6 0.084 6.024 ;
    END
  END q1[4]
  PIN q1[50]
    DIRECTION INPUT ;
    USE SIGNAL ;
    PORT
      LAYER M4 ;
        RECT  0 32.688 0.084 32.712 ;
    END
  END q1[50]
  PIN q1[51]
    DIRECTION INPUT ;
    USE SIGNAL ;
    PORT
      LAYER M4 ;
        RECT  0 32.784 0.084 32.808 ;
    END
  END q1[51]
  PIN q1[52]
    DIRECTION INPUT ;
    USE SIGNAL ;
    PORT
      LAYER M4 ;
        RECT  0 32.88 0.084 32.904 ;
    END
  END q1[52]
  PIN q1[53]
    DIRECTION INPUT ;
    USE SIGNAL ;
    PORT
      LAYER M4 ;
        RECT  0 32.976 0.084 33 ;
    END
  END q1[53]
  PIN q1[54]
    DIRECTION INPUT ;
    USE SIGNAL ;
    PORT
      LAYER M4 ;
        RECT  0 33.072 0.084 33.096 ;
    END
  END q1[54]
  PIN q1[55]
    DIRECTION INPUT ;
    USE SIGNAL ;
    PORT
      LAYER M4 ;
        RECT  0 33.168 0.084 33.192 ;
    END
  END q1[55]
  PIN q1[56]
    DIRECTION INPUT ;
    USE SIGNAL ;
    PORT
      LAYER M4 ;
        RECT  0 33.264 0.084 33.288 ;
    END
  END q1[56]
  PIN q1[57]
    DIRECTION INPUT ;
    USE SIGNAL ;
    PORT
      LAYER M4 ;
        RECT  0 33.36 0.084 33.384 ;
    END
  END q1[57]
  PIN q1[58]
    DIRECTION INPUT ;
    USE SIGNAL ;
    PORT
      LAYER M4 ;
        RECT  0 33.456 0.084 33.48 ;
    END
  END q1[58]
  PIN q1[59]
    DIRECTION INPUT ;
    USE SIGNAL ;
    PORT
      LAYER M4 ;
        RECT  0 33.552 0.084 33.576 ;
    END
  END q1[59]
  PIN q1[5]
    DIRECTION INPUT ;
    USE SIGNAL ;
    PORT
      LAYER M4 ;
        RECT  0 6.096 0.084 6.12 ;
    END
  END q1[5]
  PIN q1[60]
    DIRECTION INPUT ;
    USE SIGNAL ;
    PORT
      LAYER M4 ;
        RECT  0 33.648 0.084 33.672 ;
    END
  END q1[60]
  PIN q1[61]
    DIRECTION INPUT ;
    USE SIGNAL ;
    PORT
      LAYER M4 ;
        RECT  0 33.744 0.084 33.768 ;
    END
  END q1[61]
  PIN q1[62]
    DIRECTION INPUT ;
    USE SIGNAL ;
    PORT
      LAYER M4 ;
        RECT  0 33.84 0.084 33.864 ;
    END
  END q1[62]
  PIN q1[63]
    DIRECTION INPUT ;
    USE SIGNAL ;
    PORT
      LAYER M4 ;
        RECT  0 33.936 0.084 33.96 ;
    END
  END q1[63]
  PIN q1[64]
    DIRECTION INPUT ;
    USE SIGNAL ;
    PORT
      LAYER M4 ;
        RECT  0 34.032 0.084 34.056 ;
    END
  END q1[64]
  PIN q1[65]
    DIRECTION INPUT ;
    USE SIGNAL ;
    PORT
      LAYER M4 ;
        RECT  0 34.128 0.084 34.152 ;
    END
  END q1[65]
  PIN q1[66]
    DIRECTION INPUT ;
    USE SIGNAL ;
    PORT
      LAYER M4 ;
        RECT  0 34.224 0.084 34.248 ;
    END
  END q1[66]
  PIN q1[67]
    DIRECTION INPUT ;
    USE SIGNAL ;
    PORT
      LAYER M4 ;
        RECT  0 34.32 0.084 34.344 ;
    END
  END q1[67]
  PIN q1[68]
    DIRECTION INPUT ;
    USE SIGNAL ;
    PORT
      LAYER M4 ;
        RECT  0 15.216 0.084 15.24 ;
    END
  END q1[68]
  PIN q1[69]
    DIRECTION INPUT ;
    USE SIGNAL ;
    PORT
      LAYER M4 ;
        RECT  0 15.312 0.084 15.336 ;
    END
  END q1[69]
  PIN q1[6]
    DIRECTION INPUT ;
    USE SIGNAL ;
    PORT
      LAYER M4 ;
        RECT  0 6.192 0.084 6.216 ;
    END
  END q1[6]
  PIN q1[70]
    DIRECTION INPUT ;
    USE SIGNAL ;
    PORT
      LAYER M4 ;
        RECT  0 15.408 0.084 15.432 ;
    END
  END q1[70]
  PIN q1[71]
    DIRECTION INPUT ;
    USE SIGNAL ;
    PORT
      LAYER M4 ;
        RECT  0 15.504 0.084 15.528 ;
    END
  END q1[71]
  PIN q1[7]
    DIRECTION INPUT ;
    USE SIGNAL ;
    PORT
      LAYER M4 ;
        RECT  0 6.288 0.084 6.312 ;
    END
  END q1[7]
  PIN q1[8]
    DIRECTION INPUT ;
    USE SIGNAL ;
    PORT
      LAYER M4 ;
        RECT  0 6.384 0.084 6.408 ;
    END
  END q1[8]
  PIN q1[9]
    DIRECTION INPUT ;
    USE SIGNAL ;
    PORT
      LAYER M4 ;
        RECT  0 6.48 0.084 6.504 ;
    END
  END q1[9]
  PIN q2[0]
    DIRECTION INPUT ;
    USE SIGNAL ;
    PORT
      LAYER M4 ;
        RECT  0 15.6 0.084 15.624 ;
    END
  END q2[0]
  PIN q2[10]
    DIRECTION INPUT ;
    USE SIGNAL ;
    PORT
      LAYER M4 ;
        RECT  0 16.56 0.084 16.584 ;
    END
  END q2[10]
  PIN q2[11]
    DIRECTION INPUT ;
    USE SIGNAL ;
    PORT
      LAYER M4 ;
        RECT  0 16.656 0.084 16.68 ;
    END
  END q2[11]
  PIN q2[12]
    DIRECTION INPUT ;
    USE SIGNAL ;
    PORT
      LAYER M4 ;
        RECT  0 16.752 0.084 16.776 ;
    END
  END q2[12]
  PIN q2[13]
    DIRECTION INPUT ;
    USE SIGNAL ;
    PORT
      LAYER M4 ;
        RECT  0 16.848 0.084 16.872 ;
    END
  END q2[13]
  PIN q2[14]
    DIRECTION INPUT ;
    USE SIGNAL ;
    PORT
      LAYER M4 ;
        RECT  0 16.944 0.084 16.968 ;
    END
  END q2[14]
  PIN q2[15]
    DIRECTION INPUT ;
    USE SIGNAL ;
    PORT
      LAYER M4 ;
        RECT  0 17.04 0.084 17.064 ;
    END
  END q2[15]
  PIN q2[16]
    DIRECTION INPUT ;
    USE SIGNAL ;
    PORT
      LAYER M4 ;
        RECT  0 17.136 0.084 17.16 ;
    END
  END q2[16]
  PIN q2[17]
    DIRECTION INPUT ;
    USE SIGNAL ;
    PORT
      LAYER M4 ;
        RECT  0 17.232 0.084 17.256 ;
    END
  END q2[17]
  PIN q2[18]
    DIRECTION INPUT ;
    USE SIGNAL ;
    PORT
      LAYER M4 ;
        RECT  0 17.328 0.084 17.352 ;
    END
  END q2[18]
  PIN q2[19]
    DIRECTION INPUT ;
    USE SIGNAL ;
    PORT
      LAYER M4 ;
        RECT  0 17.424 0.084 17.448 ;
    END
  END q2[19]
  PIN q2[1]
    DIRECTION INPUT ;
    USE SIGNAL ;
    PORT
      LAYER M4 ;
        RECT  0 15.696 0.084 15.72 ;
    END
  END q2[1]
  PIN q2[20]
    DIRECTION INPUT ;
    USE SIGNAL ;
    PORT
      LAYER M4 ;
        RECT  0 17.52 0.084 17.544 ;
    END
  END q2[20]
  PIN q2[21]
    DIRECTION INPUT ;
    USE SIGNAL ;
    PORT
      LAYER M4 ;
        RECT  0 17.616 0.084 17.64 ;
    END
  END q2[21]
  PIN q2[22]
    DIRECTION INPUT ;
    USE SIGNAL ;
    PORT
      LAYER M4 ;
        RECT  0 17.712 0.084 17.736 ;
    END
  END q2[22]
  PIN q2[23]
    DIRECTION INPUT ;
    USE SIGNAL ;
    PORT
      LAYER M4 ;
        RECT  0 17.808 0.084 17.832 ;
    END
  END q2[23]
  PIN q2[24]
    DIRECTION INPUT ;
    USE SIGNAL ;
    PORT
      LAYER M4 ;
        RECT  0 17.904 0.084 17.928 ;
    END
  END q2[24]
  PIN q2[25]
    DIRECTION INPUT ;
    USE SIGNAL ;
    PORT
      LAYER M4 ;
        RECT  0 18 0.084 18.024 ;
    END
  END q2[25]
  PIN q2[26]
    DIRECTION INPUT ;
    USE SIGNAL ;
    PORT
      LAYER M4 ;
        RECT  0 18.096 0.084 18.12 ;
    END
  END q2[26]
  PIN q2[27]
    DIRECTION INPUT ;
    USE SIGNAL ;
    PORT
      LAYER M4 ;
        RECT  0 18.192 0.084 18.216 ;
    END
  END q2[27]
  PIN q2[28]
    DIRECTION INPUT ;
    USE SIGNAL ;
    PORT
      LAYER M4 ;
        RECT  0 12.144 0.084 12.168 ;
    END
  END q2[28]
  PIN q2[29]
    DIRECTION INPUT ;
    USE SIGNAL ;
    PORT
      LAYER M4 ;
        RECT  0 12.24 0.084 12.264 ;
    END
  END q2[29]
  PIN q2[2]
    DIRECTION INPUT ;
    USE SIGNAL ;
    PORT
      LAYER M4 ;
        RECT  0 15.792 0.084 15.816 ;
    END
  END q2[2]
  PIN q2[30]
    DIRECTION INPUT ;
    USE SIGNAL ;
    PORT
      LAYER M4 ;
        RECT  0 12.336 0.084 12.36 ;
    END
  END q2[30]
  PIN q2[31]
    DIRECTION INPUT ;
    USE SIGNAL ;
    PORT
      LAYER M4 ;
        RECT  0 12.432 0.084 12.456 ;
    END
  END q2[31]
  PIN q2[32]
    DIRECTION INPUT ;
    USE SIGNAL ;
    PORT
      LAYER M4 ;
        RECT  0 12.528 0.084 12.552 ;
    END
  END q2[32]
  PIN q2[33]
    DIRECTION INPUT ;
    USE SIGNAL ;
    PORT
      LAYER M4 ;
        RECT  0 12.624 0.084 12.648 ;
    END
  END q2[33]
  PIN q2[34]
    DIRECTION INPUT ;
    USE SIGNAL ;
    PORT
      LAYER M4 ;
        RECT  0 12.72 0.084 12.744 ;
    END
  END q2[34]
  PIN q2[35]
    DIRECTION INPUT ;
    USE SIGNAL ;
    PORT
      LAYER M4 ;
        RECT  0 12.816 0.084 12.84 ;
    END
  END q2[35]
  PIN q2[36]
    DIRECTION INPUT ;
    USE SIGNAL ;
    PORT
      LAYER M4 ;
        RECT  0 12.912 0.084 12.936 ;
    END
  END q2[36]
  PIN q2[37]
    DIRECTION INPUT ;
    USE SIGNAL ;
    PORT
      LAYER M4 ;
        RECT  0 13.008 0.084 13.032 ;
    END
  END q2[37]
  PIN q2[38]
    DIRECTION INPUT ;
    USE SIGNAL ;
    PORT
      LAYER M4 ;
        RECT  0 13.104 0.084 13.128 ;
    END
  END q2[38]
  PIN q2[39]
    DIRECTION INPUT ;
    USE SIGNAL ;
    PORT
      LAYER M4 ;
        RECT  0 13.2 0.084 13.224 ;
    END
  END q2[39]
  PIN q2[3]
    DIRECTION INPUT ;
    USE SIGNAL ;
    PORT
      LAYER M4 ;
        RECT  0 15.888 0.084 15.912 ;
    END
  END q2[3]
  PIN q2[40]
    DIRECTION INPUT ;
    USE SIGNAL ;
    PORT
      LAYER M4 ;
        RECT  0 13.296 0.084 13.32 ;
    END
  END q2[40]
  PIN q2[41]
    DIRECTION INPUT ;
    USE SIGNAL ;
    PORT
      LAYER M4 ;
        RECT  0 13.392 0.084 13.416 ;
    END
  END q2[41]
  PIN q2[42]
    DIRECTION INPUT ;
    USE SIGNAL ;
    PORT
      LAYER M4 ;
        RECT  0 13.488 0.084 13.512 ;
    END
  END q2[42]
  PIN q2[43]
    DIRECTION INPUT ;
    USE SIGNAL ;
    PORT
      LAYER M4 ;
        RECT  0 13.584 0.084 13.608 ;
    END
  END q2[43]
  PIN q2[44]
    DIRECTION INPUT ;
    USE SIGNAL ;
    PORT
      LAYER M4 ;
        RECT  0 13.68 0.084 13.704 ;
    END
  END q2[44]
  PIN q2[45]
    DIRECTION INPUT ;
    USE SIGNAL ;
    PORT
      LAYER M4 ;
        RECT  0 13.776 0.084 13.8 ;
    END
  END q2[45]
  PIN q2[46]
    DIRECTION INPUT ;
    USE SIGNAL ;
    PORT
      LAYER M4 ;
        RECT  0 13.872 0.084 13.896 ;
    END
  END q2[46]
  PIN q2[47]
    DIRECTION INPUT ;
    USE SIGNAL ;
    PORT
      LAYER M4 ;
        RECT  0 13.968 0.084 13.992 ;
    END
  END q2[47]
  PIN q2[48]
    DIRECTION INPUT ;
    USE SIGNAL ;
    PORT
      LAYER M4 ;
        RECT  0 14.064 0.084 14.088 ;
    END
  END q2[48]
  PIN q2[49]
    DIRECTION INPUT ;
    USE SIGNAL ;
    PORT
      LAYER M4 ;
        RECT  0 14.16 0.084 14.184 ;
    END
  END q2[49]
  PIN q2[4]
    DIRECTION INPUT ;
    USE SIGNAL ;
    PORT
      LAYER M4 ;
        RECT  0 15.984 0.084 16.008 ;
    END
  END q2[4]
  PIN q2[50]
    DIRECTION INPUT ;
    USE SIGNAL ;
    PORT
      LAYER M4 ;
        RECT  0 14.256 0.084 14.28 ;
    END
  END q2[50]
  PIN q2[51]
    DIRECTION INPUT ;
    USE SIGNAL ;
    PORT
      LAYER M4 ;
        RECT  0 14.352 0.084 14.376 ;
    END
  END q2[51]
  PIN q2[52]
    DIRECTION INPUT ;
    USE SIGNAL ;
    PORT
      LAYER M4 ;
        RECT  0 14.448 0.084 14.472 ;
    END
  END q2[52]
  PIN q2[53]
    DIRECTION INPUT ;
    USE SIGNAL ;
    PORT
      LAYER M4 ;
        RECT  0 14.544 0.084 14.568 ;
    END
  END q2[53]
  PIN q2[54]
    DIRECTION INPUT ;
    USE SIGNAL ;
    PORT
      LAYER M4 ;
        RECT  0 14.64 0.084 14.664 ;
    END
  END q2[54]
  PIN q2[55]
    DIRECTION INPUT ;
    USE SIGNAL ;
    PORT
      LAYER M4 ;
        RECT  0 14.736 0.084 14.76 ;
    END
  END q2[55]
  PIN q2[56]
    DIRECTION INPUT ;
    USE SIGNAL ;
    PORT
      LAYER M4 ;
        RECT  0 14.832 0.084 14.856 ;
    END
  END q2[56]
  PIN q2[57]
    DIRECTION INPUT ;
    USE SIGNAL ;
    PORT
      LAYER M4 ;
        RECT  0 14.928 0.084 14.952 ;
    END
  END q2[57]
  PIN q2[58]
    DIRECTION INPUT ;
    USE SIGNAL ;
    PORT
      LAYER M4 ;
        RECT  0 15.024 0.084 15.048 ;
    END
  END q2[58]
  PIN q2[59]
    DIRECTION INPUT ;
    USE SIGNAL ;
    PORT
      LAYER M4 ;
        RECT  0 15.12 0.084 15.144 ;
    END
  END q2[59]
  PIN q2[5]
    DIRECTION INPUT ;
    USE SIGNAL ;
    PORT
      LAYER M4 ;
        RECT  0 16.08 0.084 16.104 ;
    END
  END q2[5]
  PIN q2[60]
    DIRECTION INPUT ;
    USE SIGNAL ;
    PORT
      LAYER M4 ;
        RECT  0 25.2 0.084 25.224 ;
    END
  END q2[60]
  PIN q2[61]
    DIRECTION INPUT ;
    USE SIGNAL ;
    PORT
      LAYER M4 ;
        RECT  0 25.296 0.084 25.32 ;
    END
  END q2[61]
  PIN q2[62]
    DIRECTION INPUT ;
    USE SIGNAL ;
    PORT
      LAYER M4 ;
        RECT  0 25.392 0.084 25.416 ;
    END
  END q2[62]
  PIN q2[63]
    DIRECTION INPUT ;
    USE SIGNAL ;
    PORT
      LAYER M4 ;
        RECT  0 25.488 0.084 25.512 ;
    END
  END q2[63]
  PIN q2[64]
    DIRECTION INPUT ;
    USE SIGNAL ;
    PORT
      LAYER M4 ;
        RECT  0 25.584 0.084 25.608 ;
    END
  END q2[64]
  PIN q2[65]
    DIRECTION INPUT ;
    USE SIGNAL ;
    PORT
      LAYER M4 ;
        RECT  0 25.68 0.084 25.704 ;
    END
  END q2[65]
  PIN q2[66]
    DIRECTION INPUT ;
    USE SIGNAL ;
    PORT
      LAYER M4 ;
        RECT  0 25.776 0.084 25.8 ;
    END
  END q2[66]
  PIN q2[67]
    DIRECTION INPUT ;
    USE SIGNAL ;
    PORT
      LAYER M4 ;
        RECT  0 25.872 0.084 25.896 ;
    END
  END q2[67]
  PIN q2[68]
    DIRECTION INPUT ;
    USE SIGNAL ;
    PORT
      LAYER M4 ;
        RECT  0 25.968 0.084 25.992 ;
    END
  END q2[68]
  PIN q2[69]
    DIRECTION INPUT ;
    USE SIGNAL ;
    PORT
      LAYER M4 ;
        RECT  0 26.064 0.084 26.088 ;
    END
  END q2[69]
  PIN q2[6]
    DIRECTION INPUT ;
    USE SIGNAL ;
    PORT
      LAYER M4 ;
        RECT  0 16.176 0.084 16.2 ;
    END
  END q2[6]
  PIN q2[70]
    DIRECTION INPUT ;
    USE SIGNAL ;
    PORT
      LAYER M4 ;
        RECT  0 26.16 0.084 26.184 ;
    END
  END q2[70]
  PIN q2[71]
    DIRECTION INPUT ;
    USE SIGNAL ;
    PORT
      LAYER M4 ;
        RECT  0 26.256 0.084 26.28 ;
    END
  END q2[71]
  PIN q2[7]
    DIRECTION INPUT ;
    USE SIGNAL ;
    PORT
      LAYER M4 ;
        RECT  0 16.272 0.084 16.296 ;
    END
  END q2[7]
  PIN q2[8]
    DIRECTION INPUT ;
    USE SIGNAL ;
    PORT
      LAYER M4 ;
        RECT  0 16.368 0.084 16.392 ;
    END
  END q2[8]
  PIN q2[9]
    DIRECTION INPUT ;
    USE SIGNAL ;
    PORT
      LAYER M4 ;
        RECT  0 16.464 0.084 16.488 ;
    END
  END q2[9]
  PIN q3[0]
    DIRECTION INPUT ;
    USE SIGNAL ;
    PORT
      LAYER M4 ;
        RECT  0 26.352 0.084 26.376 ;
    END
  END q3[0]
  PIN q3[10]
    DIRECTION INPUT ;
    USE SIGNAL ;
    PORT
      LAYER M4 ;
        RECT  0 27.312 0.084 27.336 ;
    END
  END q3[10]
  PIN q3[11]
    DIRECTION INPUT ;
    USE SIGNAL ;
    PORT
      LAYER M4 ;
        RECT  0 27.408 0.084 27.432 ;
    END
  END q3[11]
  PIN q3[12]
    DIRECTION INPUT ;
    USE SIGNAL ;
    PORT
      LAYER M4 ;
        RECT  0 27.504 0.084 27.528 ;
    END
  END q3[12]
  PIN q3[13]
    DIRECTION INPUT ;
    USE SIGNAL ;
    PORT
      LAYER M4 ;
        RECT  0 27.6 0.084 27.624 ;
    END
  END q3[13]
  PIN q3[14]
    DIRECTION INPUT ;
    USE SIGNAL ;
    PORT
      LAYER M4 ;
        RECT  0 27.696 0.084 27.72 ;
    END
  END q3[14]
  PIN q3[15]
    DIRECTION INPUT ;
    USE SIGNAL ;
    PORT
      LAYER M4 ;
        RECT  0 27.792 0.084 27.816 ;
    END
  END q3[15]
  PIN q3[16]
    DIRECTION INPUT ;
    USE SIGNAL ;
    PORT
      LAYER M4 ;
        RECT  0 27.888 0.084 27.912 ;
    END
  END q3[16]
  PIN q3[17]
    DIRECTION INPUT ;
    USE SIGNAL ;
    PORT
      LAYER M4 ;
        RECT  0 27.984 0.084 28.008 ;
    END
  END q3[17]
  PIN q3[18]
    DIRECTION INPUT ;
    USE SIGNAL ;
    PORT
      LAYER M4 ;
        RECT  0 28.08 0.084 28.104 ;
    END
  END q3[18]
  PIN q3[19]
    DIRECTION INPUT ;
    USE SIGNAL ;
    PORT
      LAYER M4 ;
        RECT  0 28.176 0.084 28.2 ;
    END
  END q3[19]
  PIN q3[1]
    DIRECTION INPUT ;
    USE SIGNAL ;
    PORT
      LAYER M4 ;
        RECT  0 26.448 0.084 26.472 ;
    END
  END q3[1]
  PIN q3[20]
    DIRECTION INPUT ;
    USE SIGNAL ;
    PORT
      LAYER M4 ;
        RECT  0 2.928 0.084 2.952 ;
    END
  END q3[20]
  PIN q3[21]
    DIRECTION INPUT ;
    USE SIGNAL ;
    PORT
      LAYER M4 ;
        RECT  0 3.024 0.084 3.048 ;
    END
  END q3[21]
  PIN q3[22]
    DIRECTION INPUT ;
    USE SIGNAL ;
    PORT
      LAYER M4 ;
        RECT  0 3.12 0.084 3.144 ;
    END
  END q3[22]
  PIN q3[23]
    DIRECTION INPUT ;
    USE SIGNAL ;
    PORT
      LAYER M4 ;
        RECT  0 3.216 0.084 3.24 ;
    END
  END q3[23]
  PIN q3[24]
    DIRECTION INPUT ;
    USE SIGNAL ;
    PORT
      LAYER M4 ;
        RECT  0 3.312 0.084 3.336 ;
    END
  END q3[24]
  PIN q3[25]
    DIRECTION INPUT ;
    USE SIGNAL ;
    PORT
      LAYER M4 ;
        RECT  0 3.408 0.084 3.432 ;
    END
  END q3[25]
  PIN q3[26]
    DIRECTION INPUT ;
    USE SIGNAL ;
    PORT
      LAYER M4 ;
        RECT  0 3.504 0.084 3.528 ;
    END
  END q3[26]
  PIN q3[27]
    DIRECTION INPUT ;
    USE SIGNAL ;
    PORT
      LAYER M4 ;
        RECT  0 3.6 0.084 3.624 ;
    END
  END q3[27]
  PIN q3[28]
    DIRECTION INPUT ;
    USE SIGNAL ;
    PORT
      LAYER M4 ;
        RECT  0 3.696 0.084 3.72 ;
    END
  END q3[28]
  PIN q3[29]
    DIRECTION INPUT ;
    USE SIGNAL ;
    PORT
      LAYER M4 ;
        RECT  0 3.792 0.084 3.816 ;
    END
  END q3[29]
  PIN q3[2]
    DIRECTION INPUT ;
    USE SIGNAL ;
    PORT
      LAYER M4 ;
        RECT  0 26.544 0.084 26.568 ;
    END
  END q3[2]
  PIN q3[30]
    DIRECTION INPUT ;
    USE SIGNAL ;
    PORT
      LAYER M4 ;
        RECT  0 3.888 0.084 3.912 ;
    END
  END q3[30]
  PIN q3[31]
    DIRECTION INPUT ;
    USE SIGNAL ;
    PORT
      LAYER M4 ;
        RECT  0 3.984 0.084 4.008 ;
    END
  END q3[31]
  PIN q3[32]
    DIRECTION INPUT ;
    USE SIGNAL ;
    PORT
      LAYER M4 ;
        RECT  0 4.08 0.084 4.104 ;
    END
  END q3[32]
  PIN q3[33]
    DIRECTION INPUT ;
    USE SIGNAL ;
    PORT
      LAYER M4 ;
        RECT  0 4.176 0.084 4.2 ;
    END
  END q3[33]
  PIN q3[34]
    DIRECTION INPUT ;
    USE SIGNAL ;
    PORT
      LAYER M4 ;
        RECT  0 4.272 0.084 4.296 ;
    END
  END q3[34]
  PIN q3[35]
    DIRECTION INPUT ;
    USE SIGNAL ;
    PORT
      LAYER M4 ;
        RECT  0 4.368 0.084 4.392 ;
    END
  END q3[35]
  PIN q3[36]
    DIRECTION INPUT ;
    USE SIGNAL ;
    PORT
      LAYER M4 ;
        RECT  0 4.464 0.084 4.488 ;
    END
  END q3[36]
  PIN q3[37]
    DIRECTION INPUT ;
    USE SIGNAL ;
    PORT
      LAYER M4 ;
        RECT  0 4.56 0.084 4.584 ;
    END
  END q3[37]
  PIN q3[38]
    DIRECTION INPUT ;
    USE SIGNAL ;
    PORT
      LAYER M4 ;
        RECT  0 4.656 0.084 4.68 ;
    END
  END q3[38]
  PIN q3[39]
    DIRECTION INPUT ;
    USE SIGNAL ;
    PORT
      LAYER M4 ;
        RECT  0 4.752 0.084 4.776 ;
    END
  END q3[39]
  PIN q3[3]
    DIRECTION INPUT ;
    USE SIGNAL ;
    PORT
      LAYER M4 ;
        RECT  0 26.64 0.084 26.664 ;
    END
  END q3[3]
  PIN q3[40]
    DIRECTION INPUT ;
    USE SIGNAL ;
    PORT
      LAYER M4 ;
        RECT  0 4.848 0.084 4.872 ;
    END
  END q3[40]
  PIN q3[41]
    DIRECTION INPUT ;
    USE SIGNAL ;
    PORT
      LAYER M4 ;
        RECT  0 4.944 0.084 4.968 ;
    END
  END q3[41]
  PIN q3[42]
    DIRECTION INPUT ;
    USE SIGNAL ;
    PORT
      LAYER M4 ;
        RECT  0 5.04 0.084 5.064 ;
    END
  END q3[42]
  PIN q3[43]
    DIRECTION INPUT ;
    USE SIGNAL ;
    PORT
      LAYER M4 ;
        RECT  0 5.136 0.084 5.16 ;
    END
  END q3[43]
  PIN q3[44]
    DIRECTION INPUT ;
    USE SIGNAL ;
    PORT
      LAYER M4 ;
        RECT  0 5.232 0.084 5.256 ;
    END
  END q3[44]
  PIN q3[45]
    DIRECTION INPUT ;
    USE SIGNAL ;
    PORT
      LAYER M4 ;
        RECT  0 5.328 0.084 5.352 ;
    END
  END q3[45]
  PIN q3[46]
    DIRECTION INPUT ;
    USE SIGNAL ;
    PORT
      LAYER M4 ;
        RECT  0 5.424 0.084 5.448 ;
    END
  END q3[46]
  PIN q3[47]
    DIRECTION INPUT ;
    USE SIGNAL ;
    PORT
      LAYER M4 ;
        RECT  0 5.52 0.084 5.544 ;
    END
  END q3[47]
  PIN q3[48]
    DIRECTION INPUT ;
    USE SIGNAL ;
    PORT
      LAYER M4 ;
        RECT  0 5.616 0.084 5.64 ;
    END
  END q3[48]
  PIN q3[49]
    DIRECTION INPUT ;
    USE SIGNAL ;
    PORT
      LAYER M4 ;
        RECT  0 5.712 0.084 5.736 ;
    END
  END q3[49]
  PIN q3[4]
    DIRECTION INPUT ;
    USE SIGNAL ;
    PORT
      LAYER M4 ;
        RECT  0 26.736 0.084 26.76 ;
    END
  END q3[4]
  PIN q3[50]
    DIRECTION INPUT ;
    USE SIGNAL ;
    PORT
      LAYER M4 ;
        RECT  0 5.808 0.084 5.832 ;
    END
  END q3[50]
  PIN q3[51]
    DIRECTION INPUT ;
    USE SIGNAL ;
    PORT
      LAYER M4 ;
        RECT  0 5.904 0.084 5.928 ;
    END
  END q3[51]
  PIN q3[52]
    DIRECTION INPUT ;
    USE SIGNAL ;
    PORT
      LAYER M4 ;
        RECT  0 28.272 0.084 28.296 ;
    END
  END q3[52]
  PIN q3[53]
    DIRECTION INPUT ;
    USE SIGNAL ;
    PORT
      LAYER M4 ;
        RECT  0 28.368 0.084 28.392 ;
    END
  END q3[53]
  PIN q3[54]
    DIRECTION INPUT ;
    USE SIGNAL ;
    PORT
      LAYER M4 ;
        RECT  0 28.464 0.084 28.488 ;
    END
  END q3[54]
  PIN q3[55]
    DIRECTION INPUT ;
    USE SIGNAL ;
    PORT
      LAYER M4 ;
        RECT  0 28.56 0.084 28.584 ;
    END
  END q3[55]
  PIN q3[56]
    DIRECTION INPUT ;
    USE SIGNAL ;
    PORT
      LAYER M4 ;
        RECT  0 28.656 0.084 28.68 ;
    END
  END q3[56]
  PIN q3[57]
    DIRECTION INPUT ;
    USE SIGNAL ;
    PORT
      LAYER M4 ;
        RECT  0 28.752 0.084 28.776 ;
    END
  END q3[57]
  PIN q3[58]
    DIRECTION INPUT ;
    USE SIGNAL ;
    PORT
      LAYER M4 ;
        RECT  0 28.848 0.084 28.872 ;
    END
  END q3[58]
  PIN q3[59]
    DIRECTION INPUT ;
    USE SIGNAL ;
    PORT
      LAYER M4 ;
        RECT  0 28.944 0.084 28.968 ;
    END
  END q3[59]
  PIN q3[5]
    DIRECTION INPUT ;
    USE SIGNAL ;
    PORT
      LAYER M4 ;
        RECT  0 26.832 0.084 26.856 ;
    END
  END q3[5]
  PIN q3[60]
    DIRECTION INPUT ;
    USE SIGNAL ;
    PORT
      LAYER M4 ;
        RECT  0 29.04 0.084 29.064 ;
    END
  END q3[60]
  PIN q3[61]
    DIRECTION INPUT ;
    USE SIGNAL ;
    PORT
      LAYER M4 ;
        RECT  0 29.136 0.084 29.16 ;
    END
  END q3[61]
  PIN q3[62]
    DIRECTION INPUT ;
    USE SIGNAL ;
    PORT
      LAYER M4 ;
        RECT  0 29.232 0.084 29.256 ;
    END
  END q3[62]
  PIN q3[63]
    DIRECTION INPUT ;
    USE SIGNAL ;
    PORT
      LAYER M4 ;
        RECT  0 29.328 0.084 29.352 ;
    END
  END q3[63]
  PIN q3[64]
    DIRECTION INPUT ;
    USE SIGNAL ;
    PORT
      LAYER M4 ;
        RECT  0 29.424 0.084 29.448 ;
    END
  END q3[64]
  PIN q3[65]
    DIRECTION INPUT ;
    USE SIGNAL ;
    PORT
      LAYER M4 ;
        RECT  0 29.52 0.084 29.544 ;
    END
  END q3[65]
  PIN q3[66]
    DIRECTION INPUT ;
    USE SIGNAL ;
    PORT
      LAYER M4 ;
        RECT  0 29.616 0.084 29.64 ;
    END
  END q3[66]
  PIN q3[67]
    DIRECTION INPUT ;
    USE SIGNAL ;
    PORT
      LAYER M4 ;
        RECT  0 29.712 0.084 29.736 ;
    END
  END q3[67]
  PIN q3[68]
    DIRECTION INPUT ;
    USE SIGNAL ;
    PORT
      LAYER M4 ;
        RECT  0 29.808 0.084 29.832 ;
    END
  END q3[68]
  PIN q3[69]
    DIRECTION INPUT ;
    USE SIGNAL ;
    PORT
      LAYER M4 ;
        RECT  0 29.904 0.084 29.928 ;
    END
  END q3[69]
  PIN q3[6]
    DIRECTION INPUT ;
    USE SIGNAL ;
    PORT
      LAYER M4 ;
        RECT  0 26.928 0.084 26.952 ;
    END
  END q3[6]
  PIN q3[70]
    DIRECTION INPUT ;
    USE SIGNAL ;
    PORT
      LAYER M4 ;
        RECT  0 30 0.084 30.024 ;
    END
  END q3[70]
  PIN q3[71]
    DIRECTION INPUT ;
    USE SIGNAL ;
    PORT
      LAYER M4 ;
        RECT  0 30.096 0.084 30.12 ;
    END
  END q3[71]
  PIN q3[7]
    DIRECTION INPUT ;
    USE SIGNAL ;
    PORT
      LAYER M4 ;
        RECT  0 27.024 0.084 27.048 ;
    END
  END q3[7]
  PIN q3[8]
    DIRECTION INPUT ;
    USE SIGNAL ;
    PORT
      LAYER M4 ;
        RECT  0 27.12 0.084 27.144 ;
    END
  END q3[8]
  PIN q3[9]
    DIRECTION INPUT ;
    USE SIGNAL ;
    PORT
      LAYER M4 ;
        RECT  0 27.216 0.084 27.24 ;
    END
  END q3[9]
  PIN q4[0]
    DIRECTION INPUT ;
    USE SIGNAL ;
    PORT
      LAYER M4 ;
        RECT  0 30.192 0.084 30.216 ;
    END
  END q4[0]
  PIN q4[10]
    DIRECTION INPUT ;
    USE SIGNAL ;
    PORT
      LAYER M4 ;
        RECT  0 31.152 0.084 31.176 ;
    END
  END q4[10]
  PIN q4[11]
    DIRECTION INPUT ;
    USE SIGNAL ;
    PORT
      LAYER M4 ;
        RECT  0 31.248 0.084 31.272 ;
    END
  END q4[11]
  PIN q4[12]
    DIRECTION INPUT ;
    USE SIGNAL ;
    PORT
      LAYER M4 ;
        RECT  0 22.128 0.084 22.152 ;
    END
  END q4[12]
  PIN q4[13]
    DIRECTION INPUT ;
    USE SIGNAL ;
    PORT
      LAYER M4 ;
        RECT  0 22.224 0.084 22.248 ;
    END
  END q4[13]
  PIN q4[14]
    DIRECTION INPUT ;
    USE SIGNAL ;
    PORT
      LAYER M4 ;
        RECT  0 22.32 0.084 22.344 ;
    END
  END q4[14]
  PIN q4[15]
    DIRECTION INPUT ;
    USE SIGNAL ;
    PORT
      LAYER M4 ;
        RECT  0 22.416 0.084 22.44 ;
    END
  END q4[15]
  PIN q4[16]
    DIRECTION INPUT ;
    USE SIGNAL ;
    PORT
      LAYER M4 ;
        RECT  0 22.512 0.084 22.536 ;
    END
  END q4[16]
  PIN q4[17]
    DIRECTION INPUT ;
    USE SIGNAL ;
    PORT
      LAYER M4 ;
        RECT  0 22.608 0.084 22.632 ;
    END
  END q4[17]
  PIN q4[18]
    DIRECTION INPUT ;
    USE SIGNAL ;
    PORT
      LAYER M4 ;
        RECT  0 22.704 0.084 22.728 ;
    END
  END q4[18]
  PIN q4[19]
    DIRECTION INPUT ;
    USE SIGNAL ;
    PORT
      LAYER M4 ;
        RECT  0 22.8 0.084 22.824 ;
    END
  END q4[19]
  PIN q4[1]
    DIRECTION INPUT ;
    USE SIGNAL ;
    PORT
      LAYER M4 ;
        RECT  0 30.288 0.084 30.312 ;
    END
  END q4[1]
  PIN q4[20]
    DIRECTION INPUT ;
    USE SIGNAL ;
    PORT
      LAYER M4 ;
        RECT  0 22.896 0.084 22.92 ;
    END
  END q4[20]
  PIN q4[21]
    DIRECTION INPUT ;
    USE SIGNAL ;
    PORT
      LAYER M4 ;
        RECT  0 22.992 0.084 23.016 ;
    END
  END q4[21]
  PIN q4[22]
    DIRECTION INPUT ;
    USE SIGNAL ;
    PORT
      LAYER M4 ;
        RECT  0 23.088 0.084 23.112 ;
    END
  END q4[22]
  PIN q4[23]
    DIRECTION INPUT ;
    USE SIGNAL ;
    PORT
      LAYER M4 ;
        RECT  0 23.184 0.084 23.208 ;
    END
  END q4[23]
  PIN q4[24]
    DIRECTION INPUT ;
    USE SIGNAL ;
    PORT
      LAYER M4 ;
        RECT  0 23.28 0.084 23.304 ;
    END
  END q4[24]
  PIN q4[25]
    DIRECTION INPUT ;
    USE SIGNAL ;
    PORT
      LAYER M4 ;
        RECT  0 23.376 0.084 23.4 ;
    END
  END q4[25]
  PIN q4[26]
    DIRECTION INPUT ;
    USE SIGNAL ;
    PORT
      LAYER M4 ;
        RECT  0 23.472 0.084 23.496 ;
    END
  END q4[26]
  PIN q4[27]
    DIRECTION INPUT ;
    USE SIGNAL ;
    PORT
      LAYER M4 ;
        RECT  0 23.568 0.084 23.592 ;
    END
  END q4[27]
  PIN q4[28]
    DIRECTION INPUT ;
    USE SIGNAL ;
    PORT
      LAYER M4 ;
        RECT  0 23.664 0.084 23.688 ;
    END
  END q4[28]
  PIN q4[29]
    DIRECTION INPUT ;
    USE SIGNAL ;
    PORT
      LAYER M4 ;
        RECT  0 23.76 0.084 23.784 ;
    END
  END q4[29]
  PIN q4[2]
    DIRECTION INPUT ;
    USE SIGNAL ;
    PORT
      LAYER M4 ;
        RECT  0 30.384 0.084 30.408 ;
    END
  END q4[2]
  PIN q4[30]
    DIRECTION INPUT ;
    USE SIGNAL ;
    PORT
      LAYER M4 ;
        RECT  0 23.856 0.084 23.88 ;
    END
  END q4[30]
  PIN q4[31]
    DIRECTION INPUT ;
    USE SIGNAL ;
    PORT
      LAYER M4 ;
        RECT  0 23.952 0.084 23.976 ;
    END
  END q4[31]
  PIN q4[32]
    DIRECTION INPUT ;
    USE SIGNAL ;
    PORT
      LAYER M4 ;
        RECT  0 24.048 0.084 24.072 ;
    END
  END q4[32]
  PIN q4[33]
    DIRECTION INPUT ;
    USE SIGNAL ;
    PORT
      LAYER M4 ;
        RECT  0 24.144 0.084 24.168 ;
    END
  END q4[33]
  PIN q4[34]
    DIRECTION INPUT ;
    USE SIGNAL ;
    PORT
      LAYER M4 ;
        RECT  0 24.24 0.084 24.264 ;
    END
  END q4[34]
  PIN q4[35]
    DIRECTION INPUT ;
    USE SIGNAL ;
    PORT
      LAYER M4 ;
        RECT  0 24.336 0.084 24.36 ;
    END
  END q4[35]
  PIN q4[36]
    DIRECTION INPUT ;
    USE SIGNAL ;
    PORT
      LAYER M4 ;
        RECT  0 24.432 0.084 24.456 ;
    END
  END q4[36]
  PIN q4[37]
    DIRECTION INPUT ;
    USE SIGNAL ;
    PORT
      LAYER M4 ;
        RECT  0 24.528 0.084 24.552 ;
    END
  END q4[37]
  PIN q4[38]
    DIRECTION INPUT ;
    USE SIGNAL ;
    PORT
      LAYER M4 ;
        RECT  0 24.624 0.084 24.648 ;
    END
  END q4[38]
  PIN q4[39]
    DIRECTION INPUT ;
    USE SIGNAL ;
    PORT
      LAYER M4 ;
        RECT  0 24.72 0.084 24.744 ;
    END
  END q4[39]
  PIN q4[3]
    DIRECTION INPUT ;
    USE SIGNAL ;
    PORT
      LAYER M4 ;
        RECT  0 30.48 0.084 30.504 ;
    END
  END q4[3]
  PIN q4[40]
    DIRECTION INPUT ;
    USE SIGNAL ;
    PORT
      LAYER M4 ;
        RECT  0 24.816 0.084 24.84 ;
    END
  END q4[40]
  PIN q4[41]
    DIRECTION INPUT ;
    USE SIGNAL ;
    PORT
      LAYER M4 ;
        RECT  0 24.912 0.084 24.936 ;
    END
  END q4[41]
  PIN q4[42]
    DIRECTION INPUT ;
    USE SIGNAL ;
    PORT
      LAYER M4 ;
        RECT  0 25.008 0.084 25.032 ;
    END
  END q4[42]
  PIN q4[43]
    DIRECTION INPUT ;
    USE SIGNAL ;
    PORT
      LAYER M4 ;
        RECT  0 25.104 0.084 25.128 ;
    END
  END q4[43]
  PIN q4[44]
    DIRECTION INPUT ;
    USE SIGNAL ;
    PORT
      LAYER M4 ;
        RECT  0 37.488 0.084 37.512 ;
    END
  END q4[44]
  PIN q4[45]
    DIRECTION INPUT ;
    USE SIGNAL ;
    PORT
      LAYER M4 ;
        RECT  0 37.584 0.084 37.608 ;
    END
  END q4[45]
  PIN q4[46]
    DIRECTION INPUT ;
    USE SIGNAL ;
    PORT
      LAYER M4 ;
        RECT  0 37.68 0.084 37.704 ;
    END
  END q4[46]
  PIN q4[47]
    DIRECTION INPUT ;
    USE SIGNAL ;
    PORT
      LAYER M4 ;
        RECT  0 37.776 0.084 37.8 ;
    END
  END q4[47]
  PIN q4[48]
    DIRECTION INPUT ;
    USE SIGNAL ;
    PORT
      LAYER M4 ;
        RECT  0 37.872 0.084 37.896 ;
    END
  END q4[48]
  PIN q4[49]
    DIRECTION INPUT ;
    USE SIGNAL ;
    PORT
      LAYER M4 ;
        RECT  0 37.968 0.084 37.992 ;
    END
  END q4[49]
  PIN q4[4]
    DIRECTION INPUT ;
    USE SIGNAL ;
    PORT
      LAYER M4 ;
        RECT  0 30.576 0.084 30.6 ;
    END
  END q4[4]
  PIN q4[50]
    DIRECTION INPUT ;
    USE SIGNAL ;
    PORT
      LAYER M4 ;
        RECT  0 38.064 0.084 38.088 ;
    END
  END q4[50]
  PIN q4[51]
    DIRECTION INPUT ;
    USE SIGNAL ;
    PORT
      LAYER M4 ;
        RECT  0 38.16 0.084 38.184 ;
    END
  END q4[51]
  PIN q4[52]
    DIRECTION INPUT ;
    USE SIGNAL ;
    PORT
      LAYER M4 ;
        RECT  0 38.256 0.084 38.28 ;
    END
  END q4[52]
  PIN q4[53]
    DIRECTION INPUT ;
    USE SIGNAL ;
    PORT
      LAYER M4 ;
        RECT  0 38.352 0.084 38.376 ;
    END
  END q4[53]
  PIN q4[54]
    DIRECTION INPUT ;
    USE SIGNAL ;
    PORT
      LAYER M4 ;
        RECT  0 38.448 0.084 38.472 ;
    END
  END q4[54]
  PIN q4[55]
    DIRECTION INPUT ;
    USE SIGNAL ;
    PORT
      LAYER M4 ;
        RECT  0 38.544 0.084 38.568 ;
    END
  END q4[55]
  PIN q4[56]
    DIRECTION INPUT ;
    USE SIGNAL ;
    PORT
      LAYER M4 ;
        RECT  0 38.64 0.084 38.664 ;
    END
  END q4[56]
  PIN q4[57]
    DIRECTION INPUT ;
    USE SIGNAL ;
    PORT
      LAYER M4 ;
        RECT  0 38.736 0.084 38.76 ;
    END
  END q4[57]
  PIN q4[58]
    DIRECTION INPUT ;
    USE SIGNAL ;
    PORT
      LAYER M4 ;
        RECT  0 38.832 0.084 38.856 ;
    END
  END q4[58]
  PIN q4[59]
    DIRECTION INPUT ;
    USE SIGNAL ;
    PORT
      LAYER M4 ;
        RECT  0 38.928 0.084 38.952 ;
    END
  END q4[59]
  PIN q4[5]
    DIRECTION INPUT ;
    USE SIGNAL ;
    PORT
      LAYER M4 ;
        RECT  0 30.672 0.084 30.696 ;
    END
  END q4[5]
  PIN q4[60]
    DIRECTION INPUT ;
    USE SIGNAL ;
    PORT
      LAYER M4 ;
        RECT  0 39.024 0.084 39.048 ;
    END
  END q4[60]
  PIN q4[61]
    DIRECTION INPUT ;
    USE SIGNAL ;
    PORT
      LAYER M4 ;
        RECT  0 39.12 0.084 39.144 ;
    END
  END q4[61]
  PIN q4[62]
    DIRECTION INPUT ;
    USE SIGNAL ;
    PORT
      LAYER M4 ;
        RECT  0 39.216 0.084 39.24 ;
    END
  END q4[62]
  PIN q4[63]
    DIRECTION INPUT ;
    USE SIGNAL ;
    PORT
      LAYER M4 ;
        RECT  0 39.312 0.084 39.336 ;
    END
  END q4[63]
  PIN q4[64]
    DIRECTION INPUT ;
    USE SIGNAL ;
    PORT
      LAYER M4 ;
        RECT  0 39.408 0.084 39.432 ;
    END
  END q4[64]
  PIN q4[65]
    DIRECTION INPUT ;
    USE SIGNAL ;
    PORT
      LAYER M4 ;
        RECT  0 39.504 0.084 39.528 ;
    END
  END q4[65]
  PIN q4[66]
    DIRECTION INPUT ;
    USE SIGNAL ;
    PORT
      LAYER M4 ;
        RECT  0 39.6 0.084 39.624 ;
    END
  END q4[66]
  PIN q4[67]
    DIRECTION INPUT ;
    USE SIGNAL ;
    PORT
      LAYER M4 ;
        RECT  0 39.696 0.084 39.72 ;
    END
  END q4[67]
  PIN q4[68]
    DIRECTION INPUT ;
    USE SIGNAL ;
    PORT
      LAYER M4 ;
        RECT  0 39.792 0.084 39.816 ;
    END
  END q4[68]
  PIN q4[69]
    DIRECTION INPUT ;
    USE SIGNAL ;
    PORT
      LAYER M4 ;
        RECT  0 39.888 0.084 39.912 ;
    END
  END q4[69]
  PIN q4[6]
    DIRECTION INPUT ;
    USE SIGNAL ;
    PORT
      LAYER M4 ;
        RECT  0 30.768 0.084 30.792 ;
    END
  END q4[6]
  PIN q4[70]
    DIRECTION INPUT ;
    USE SIGNAL ;
    PORT
      LAYER M4 ;
        RECT  0 39.984 0.084 40.008 ;
    END
  END q4[70]
  PIN q4[71]
    DIRECTION INPUT ;
    USE SIGNAL ;
    PORT
      LAYER M4 ;
        RECT  0 40.08 0.084 40.104 ;
    END
  END q4[71]
  PIN q4[7]
    DIRECTION INPUT ;
    USE SIGNAL ;
    PORT
      LAYER M4 ;
        RECT  0 30.864 0.084 30.888 ;
    END
  END q4[7]
  PIN q4[8]
    DIRECTION INPUT ;
    USE SIGNAL ;
    PORT
      LAYER M4 ;
        RECT  0 30.96 0.084 30.984 ;
    END
  END q4[8]
  PIN q4[9]
    DIRECTION INPUT ;
    USE SIGNAL ;
    PORT
      LAYER M4 ;
        RECT  0 31.056 0.084 31.08 ;
    END
  END q4[9]
  PIN q5[0]
    DIRECTION INPUT ;
    USE SIGNAL ;
    PORT
      LAYER M4 ;
        RECT  0 40.176 0.084 40.2 ;
    END
  END q5[0]
  PIN q5[10]
    DIRECTION INPUT ;
    USE SIGNAL ;
    PORT
      LAYER M4 ;
        RECT  0 41.904 0.084 41.928 ;
    END
  END q5[10]
  PIN q5[11]
    DIRECTION INPUT ;
    USE SIGNAL ;
    PORT
      LAYER M4 ;
        RECT  0 42 0.084 42.024 ;
    END
  END q5[11]
  PIN q5[12]
    DIRECTION INPUT ;
    USE SIGNAL ;
    PORT
      LAYER M4 ;
        RECT  0 42.096 0.084 42.12 ;
    END
  END q5[12]
  PIN q5[13]
    DIRECTION INPUT ;
    USE SIGNAL ;
    PORT
      LAYER M4 ;
        RECT  0 42.192 0.084 42.216 ;
    END
  END q5[13]
  PIN q5[14]
    DIRECTION INPUT ;
    USE SIGNAL ;
    PORT
      LAYER M4 ;
        RECT  0 42.288 0.084 42.312 ;
    END
  END q5[14]
  PIN q5[15]
    DIRECTION INPUT ;
    USE SIGNAL ;
    PORT
      LAYER M4 ;
        RECT  0 42.384 0.084 42.408 ;
    END
  END q5[15]
  PIN q5[16]
    DIRECTION INPUT ;
    USE SIGNAL ;
    PORT
      LAYER M4 ;
        RECT  0 42.48 0.084 42.504 ;
    END
  END q5[16]
  PIN q5[17]
    DIRECTION INPUT ;
    USE SIGNAL ;
    PORT
      LAYER M4 ;
        RECT  0 42.576 0.084 42.6 ;
    END
  END q5[17]
  PIN q5[18]
    DIRECTION INPUT ;
    USE SIGNAL ;
    PORT
      LAYER M4 ;
        RECT  0 42.672 0.084 42.696 ;
    END
  END q5[18]
  PIN q5[19]
    DIRECTION INPUT ;
    USE SIGNAL ;
    PORT
      LAYER M4 ;
        RECT  0 42.768 0.084 42.792 ;
    END
  END q5[19]
  PIN q5[1]
    DIRECTION INPUT ;
    USE SIGNAL ;
    PORT
      LAYER M4 ;
        RECT  0 40.272 0.084 40.296 ;
    END
  END q5[1]
  PIN q5[20]
    DIRECTION INPUT ;
    USE SIGNAL ;
    PORT
      LAYER M4 ;
        RECT  0 42.864 0.084 42.888 ;
    END
  END q5[20]
  PIN q5[21]
    DIRECTION INPUT ;
    USE SIGNAL ;
    PORT
      LAYER M4 ;
        RECT  0 42.96 0.084 42.984 ;
    END
  END q5[21]
  PIN q5[22]
    DIRECTION INPUT ;
    USE SIGNAL ;
    PORT
      LAYER M4 ;
        RECT  0 43.056 0.084 43.08 ;
    END
  END q5[22]
  PIN q5[23]
    DIRECTION INPUT ;
    USE SIGNAL ;
    PORT
      LAYER M4 ;
        RECT  0 43.152 0.084 43.176 ;
    END
  END q5[23]
  PIN q5[24]
    DIRECTION INPUT ;
    USE SIGNAL ;
    PORT
      LAYER M4 ;
        RECT  0 43.248 0.084 43.272 ;
    END
  END q5[24]
  PIN q5[25]
    DIRECTION INPUT ;
    USE SIGNAL ;
    PORT
      LAYER M4 ;
        RECT  0 43.344 0.084 43.368 ;
    END
  END q5[25]
  PIN q5[26]
    DIRECTION INPUT ;
    USE SIGNAL ;
    PORT
      LAYER M4 ;
        RECT  0 43.44 0.084 43.464 ;
    END
  END q5[26]
  PIN q5[27]
    DIRECTION INPUT ;
    USE SIGNAL ;
    PORT
      LAYER M4 ;
        RECT  0 43.536 0.084 43.56 ;
    END
  END q5[27]
  PIN q5[28]
    DIRECTION INPUT ;
    USE SIGNAL ;
    PORT
      LAYER M4 ;
        RECT  0 43.632 0.084 43.656 ;
    END
  END q5[28]
  PIN q5[29]
    DIRECTION INPUT ;
    USE SIGNAL ;
    PORT
      LAYER M4 ;
        RECT  0 43.728 0.084 43.752 ;
    END
  END q5[29]
  PIN q5[2]
    DIRECTION INPUT ;
    USE SIGNAL ;
    PORT
      LAYER M4 ;
        RECT  0 40.368 0.084 40.392 ;
    END
  END q5[2]
  PIN q5[30]
    DIRECTION INPUT ;
    USE SIGNAL ;
    PORT
      LAYER M4 ;
        RECT  0 43.824 0.084 43.848 ;
    END
  END q5[30]
  PIN q5[31]
    DIRECTION INPUT ;
    USE SIGNAL ;
    PORT
      LAYER M4 ;
        RECT  0 43.92 0.084 43.944 ;
    END
  END q5[31]
  PIN q5[32]
    DIRECTION INPUT ;
    USE SIGNAL ;
    PORT
      LAYER M4 ;
        RECT  0 44.016 0.084 44.04 ;
    END
  END q5[32]
  PIN q5[33]
    DIRECTION INPUT ;
    USE SIGNAL ;
    PORT
      LAYER M4 ;
        RECT  0 44.112 0.084 44.136 ;
    END
  END q5[33]
  PIN q5[34]
    DIRECTION INPUT ;
    USE SIGNAL ;
    PORT
      LAYER M4 ;
        RECT  0 44.208 0.084 44.232 ;
    END
  END q5[34]
  PIN q5[35]
    DIRECTION INPUT ;
    USE SIGNAL ;
    PORT
      LAYER M4 ;
        RECT  0 44.304 0.084 44.328 ;
    END
  END q5[35]
  PIN q5[36]
    DIRECTION INPUT ;
    USE SIGNAL ;
    PORT
      LAYER M4 ;
        RECT  0 50.544 0.084 50.568 ;
    END
  END q5[36]
  PIN q5[37]
    DIRECTION INPUT ;
    USE SIGNAL ;
    PORT
      LAYER M4 ;
        RECT  0 50.64 0.084 50.664 ;
    END
  END q5[37]
  PIN q5[38]
    DIRECTION INPUT ;
    USE SIGNAL ;
    PORT
      LAYER M4 ;
        RECT  0 50.736 0.084 50.76 ;
    END
  END q5[38]
  PIN q5[39]
    DIRECTION INPUT ;
    USE SIGNAL ;
    PORT
      LAYER M4 ;
        RECT  0 50.832 0.084 50.856 ;
    END
  END q5[39]
  PIN q5[3]
    DIRECTION INPUT ;
    USE SIGNAL ;
    PORT
      LAYER M4 ;
        RECT  0 40.464 0.084 40.488 ;
    END
  END q5[3]
  PIN q5[40]
    DIRECTION INPUT ;
    USE SIGNAL ;
    PORT
      LAYER M4 ;
        RECT  0 50.928 0.084 50.952 ;
    END
  END q5[40]
  PIN q5[41]
    DIRECTION INPUT ;
    USE SIGNAL ;
    PORT
      LAYER M4 ;
        RECT  0 51.024 0.084 51.048 ;
    END
  END q5[41]
  PIN q5[42]
    DIRECTION INPUT ;
    USE SIGNAL ;
    PORT
      LAYER M4 ;
        RECT  0 51.12 0.084 51.144 ;
    END
  END q5[42]
  PIN q5[43]
    DIRECTION INPUT ;
    USE SIGNAL ;
    PORT
      LAYER M4 ;
        RECT  0 51.216 0.084 51.24 ;
    END
  END q5[43]
  PIN q5[44]
    DIRECTION INPUT ;
    USE SIGNAL ;
    PORT
      LAYER M4 ;
        RECT  0 51.312 0.084 51.336 ;
    END
  END q5[44]
  PIN q5[45]
    DIRECTION INPUT ;
    USE SIGNAL ;
    PORT
      LAYER M4 ;
        RECT  0 51.408 0.084 51.432 ;
    END
  END q5[45]
  PIN q5[46]
    DIRECTION INPUT ;
    USE SIGNAL ;
    PORT
      LAYER M4 ;
        RECT  0 51.504 0.084 51.528 ;
    END
  END q5[46]
  PIN q5[47]
    DIRECTION INPUT ;
    USE SIGNAL ;
    PORT
      LAYER M4 ;
        RECT  0 51.6 0.084 51.624 ;
    END
  END q5[47]
  PIN q5[48]
    DIRECTION INPUT ;
    USE SIGNAL ;
    PORT
      LAYER M4 ;
        RECT  0 51.696 0.084 51.72 ;
    END
  END q5[48]
  PIN q5[49]
    DIRECTION INPUT ;
    USE SIGNAL ;
    PORT
      LAYER M4 ;
        RECT  0 51.792 0.084 51.816 ;
    END
  END q5[49]
  PIN q5[4]
    DIRECTION INPUT ;
    USE SIGNAL ;
    PORT
      LAYER M4 ;
        RECT  0 41.328 0.084 41.352 ;
    END
  END q5[4]
  PIN q5[50]
    DIRECTION INPUT ;
    USE SIGNAL ;
    PORT
      LAYER M4 ;
        RECT  0 51.888 0.084 51.912 ;
    END
  END q5[50]
  PIN q5[51]
    DIRECTION INPUT ;
    USE SIGNAL ;
    PORT
      LAYER M4 ;
        RECT  0 51.984 0.084 52.008 ;
    END
  END q5[51]
  PIN q5[52]
    DIRECTION INPUT ;
    USE SIGNAL ;
    PORT
      LAYER M4 ;
        RECT  0 52.08 0.084 52.104 ;
    END
  END q5[52]
  PIN q5[53]
    DIRECTION INPUT ;
    USE SIGNAL ;
    PORT
      LAYER M4 ;
        RECT  0 52.176 0.084 52.2 ;
    END
  END q5[53]
  PIN q5[54]
    DIRECTION INPUT ;
    USE SIGNAL ;
    PORT
      LAYER M4 ;
        RECT  0 52.272 0.084 52.296 ;
    END
  END q5[54]
  PIN q5[55]
    DIRECTION INPUT ;
    USE SIGNAL ;
    PORT
      LAYER M4 ;
        RECT  0 52.368 0.084 52.392 ;
    END
  END q5[55]
  PIN q5[56]
    DIRECTION INPUT ;
    USE SIGNAL ;
    PORT
      LAYER M4 ;
        RECT  0 52.464 0.084 52.488 ;
    END
  END q5[56]
  PIN q5[57]
    DIRECTION INPUT ;
    USE SIGNAL ;
    PORT
      LAYER M4 ;
        RECT  0 52.56 0.084 52.584 ;
    END
  END q5[57]
  PIN q5[58]
    DIRECTION INPUT ;
    USE SIGNAL ;
    PORT
      LAYER M4 ;
        RECT  0 52.656 0.084 52.68 ;
    END
  END q5[58]
  PIN q5[59]
    DIRECTION INPUT ;
    USE SIGNAL ;
    PORT
      LAYER M4 ;
        RECT  0 52.752 0.084 52.776 ;
    END
  END q5[59]
  PIN q5[5]
    DIRECTION INPUT ;
    USE SIGNAL ;
    PORT
      LAYER M4 ;
        RECT  0 41.424 0.084 41.448 ;
    END
  END q5[5]
  PIN q5[60]
    DIRECTION INPUT ;
    USE SIGNAL ;
    PORT
      LAYER M4 ;
        RECT  0 52.848 0.084 52.872 ;
    END
  END q5[60]
  PIN q5[61]
    DIRECTION INPUT ;
    USE SIGNAL ;
    PORT
      LAYER M4 ;
        RECT  0 52.944 0.084 52.968 ;
    END
  END q5[61]
  PIN q5[62]
    DIRECTION INPUT ;
    USE SIGNAL ;
    PORT
      LAYER M4 ;
        RECT  0 53.04 0.084 53.064 ;
    END
  END q5[62]
  PIN q5[63]
    DIRECTION INPUT ;
    USE SIGNAL ;
    PORT
      LAYER M4 ;
        RECT  0 53.136 0.084 53.16 ;
    END
  END q5[63]
  PIN q5[64]
    DIRECTION INPUT ;
    USE SIGNAL ;
    PORT
      LAYER M4 ;
        RECT  0 53.232 0.084 53.256 ;
    END
  END q5[64]
  PIN q5[65]
    DIRECTION INPUT ;
    USE SIGNAL ;
    PORT
      LAYER M4 ;
        RECT  0 53.328 0.084 53.352 ;
    END
  END q5[65]
  PIN q5[66]
    DIRECTION INPUT ;
    USE SIGNAL ;
    PORT
      LAYER M4 ;
        RECT  0 53.424 0.084 53.448 ;
    END
  END q5[66]
  PIN q5[67]
    DIRECTION INPUT ;
    USE SIGNAL ;
    PORT
      LAYER M4 ;
        RECT  0 53.52 0.084 53.544 ;
    END
  END q5[67]
  PIN q5[68]
    DIRECTION INPUT ;
    USE SIGNAL ;
    PORT
      LAYER M4 ;
        RECT  0 47.472 0.084 47.496 ;
    END
  END q5[68]
  PIN q5[69]
    DIRECTION INPUT ;
    USE SIGNAL ;
    PORT
      LAYER M4 ;
        RECT  0 47.568 0.084 47.592 ;
    END
  END q5[69]
  PIN q5[6]
    DIRECTION INPUT ;
    USE SIGNAL ;
    PORT
      LAYER M4 ;
        RECT  0 41.52 0.084 41.544 ;
    END
  END q5[6]
  PIN q5[70]
    DIRECTION INPUT ;
    USE SIGNAL ;
    PORT
      LAYER M4 ;
        RECT  0 47.664 0.084 47.688 ;
    END
  END q5[70]
  PIN q5[71]
    DIRECTION INPUT ;
    USE SIGNAL ;
    PORT
      LAYER M4 ;
        RECT  0 47.76 0.084 47.784 ;
    END
  END q5[71]
  PIN q5[7]
    DIRECTION INPUT ;
    USE SIGNAL ;
    PORT
      LAYER M4 ;
        RECT  0 41.616 0.084 41.64 ;
    END
  END q5[7]
  PIN q5[8]
    DIRECTION INPUT ;
    USE SIGNAL ;
    PORT
      LAYER M4 ;
        RECT  0 41.712 0.084 41.736 ;
    END
  END q5[8]
  PIN q5[9]
    DIRECTION INPUT ;
    USE SIGNAL ;
    PORT
      LAYER M4 ;
        RECT  0 41.808 0.084 41.832 ;
    END
  END q5[9]
  PIN q6[0]
    DIRECTION INPUT ;
    USE SIGNAL ;
    PORT
      LAYER M4 ;
        RECT  0 47.856 0.084 47.88 ;
    END
  END q6[0]
  PIN q6[10]
    DIRECTION INPUT ;
    USE SIGNAL ;
    PORT
      LAYER M4 ;
        RECT  0 48.816 0.084 48.84 ;
    END
  END q6[10]
  PIN q6[11]
    DIRECTION INPUT ;
    USE SIGNAL ;
    PORT
      LAYER M4 ;
        RECT  0 48.912 0.084 48.936 ;
    END
  END q6[11]
  PIN q6[12]
    DIRECTION INPUT ;
    USE SIGNAL ;
    PORT
      LAYER M4 ;
        RECT  0 49.008 0.084 49.032 ;
    END
  END q6[12]
  PIN q6[13]
    DIRECTION INPUT ;
    USE SIGNAL ;
    PORT
      LAYER M4 ;
        RECT  0 49.104 0.084 49.128 ;
    END
  END q6[13]
  PIN q6[14]
    DIRECTION INPUT ;
    USE SIGNAL ;
    PORT
      LAYER M4 ;
        RECT  0 49.2 0.084 49.224 ;
    END
  END q6[14]
  PIN q6[15]
    DIRECTION INPUT ;
    USE SIGNAL ;
    PORT
      LAYER M4 ;
        RECT  0 49.296 0.084 49.32 ;
    END
  END q6[15]
  PIN q6[16]
    DIRECTION INPUT ;
    USE SIGNAL ;
    PORT
      LAYER M4 ;
        RECT  0 49.392 0.084 49.416 ;
    END
  END q6[16]
  PIN q6[17]
    DIRECTION INPUT ;
    USE SIGNAL ;
    PORT
      LAYER M4 ;
        RECT  0 49.488 0.084 49.512 ;
    END
  END q6[17]
  PIN q6[18]
    DIRECTION INPUT ;
    USE SIGNAL ;
    PORT
      LAYER M4 ;
        RECT  0 49.584 0.084 49.608 ;
    END
  END q6[18]
  PIN q6[19]
    DIRECTION INPUT ;
    USE SIGNAL ;
    PORT
      LAYER M4 ;
        RECT  0 49.68 0.084 49.704 ;
    END
  END q6[19]
  PIN q6[1]
    DIRECTION INPUT ;
    USE SIGNAL ;
    PORT
      LAYER M4 ;
        RECT  0 47.952 0.084 47.976 ;
    END
  END q6[1]
  PIN q6[20]
    DIRECTION INPUT ;
    USE SIGNAL ;
    PORT
      LAYER M4 ;
        RECT  0 49.776 0.084 49.8 ;
    END
  END q6[20]
  PIN q6[21]
    DIRECTION INPUT ;
    USE SIGNAL ;
    PORT
      LAYER M4 ;
        RECT  0 49.872 0.084 49.896 ;
    END
  END q6[21]
  PIN q6[22]
    DIRECTION INPUT ;
    USE SIGNAL ;
    PORT
      LAYER M4 ;
        RECT  0 49.968 0.084 49.992 ;
    END
  END q6[22]
  PIN q6[23]
    DIRECTION INPUT ;
    USE SIGNAL ;
    PORT
      LAYER M4 ;
        RECT  0 50.064 0.084 50.088 ;
    END
  END q6[23]
  PIN q6[24]
    DIRECTION INPUT ;
    USE SIGNAL ;
    PORT
      LAYER M4 ;
        RECT  0 50.16 0.084 50.184 ;
    END
  END q6[24]
  PIN q6[25]
    DIRECTION INPUT ;
    USE SIGNAL ;
    PORT
      LAYER M4 ;
        RECT  0 50.256 0.084 50.28 ;
    END
  END q6[25]
  PIN q6[26]
    DIRECTION INPUT ;
    USE SIGNAL ;
    PORT
      LAYER M4 ;
        RECT  0 50.352 0.084 50.376 ;
    END
  END q6[26]
  PIN q6[27]
    DIRECTION INPUT ;
    USE SIGNAL ;
    PORT
      LAYER M4 ;
        RECT  0 50.448 0.084 50.472 ;
    END
  END q6[27]
  PIN q6[28]
    DIRECTION INPUT ;
    USE SIGNAL ;
    PORT
      LAYER M4 ;
        RECT  0 44.4 0.084 44.424 ;
    END
  END q6[28]
  PIN q6[29]
    DIRECTION INPUT ;
    USE SIGNAL ;
    PORT
      LAYER M4 ;
        RECT  0 44.496 0.084 44.52 ;
    END
  END q6[29]
  PIN q6[2]
    DIRECTION INPUT ;
    USE SIGNAL ;
    PORT
      LAYER M4 ;
        RECT  0 48.048 0.084 48.072 ;
    END
  END q6[2]
  PIN q6[30]
    DIRECTION INPUT ;
    USE SIGNAL ;
    PORT
      LAYER M4 ;
        RECT  0 44.592 0.084 44.616 ;
    END
  END q6[30]
  PIN q6[31]
    DIRECTION INPUT ;
    USE SIGNAL ;
    PORT
      LAYER M4 ;
        RECT  0 44.688 0.084 44.712 ;
    END
  END q6[31]
  PIN q6[32]
    DIRECTION INPUT ;
    USE SIGNAL ;
    PORT
      LAYER M4 ;
        RECT  0 44.784 0.084 44.808 ;
    END
  END q6[32]
  PIN q6[33]
    DIRECTION INPUT ;
    USE SIGNAL ;
    PORT
      LAYER M4 ;
        RECT  0 44.88 0.084 44.904 ;
    END
  END q6[33]
  PIN q6[34]
    DIRECTION INPUT ;
    USE SIGNAL ;
    PORT
      LAYER M4 ;
        RECT  0 44.976 0.084 45 ;
    END
  END q6[34]
  PIN q6[35]
    DIRECTION INPUT ;
    USE SIGNAL ;
    PORT
      LAYER M4 ;
        RECT  0 45.072 0.084 45.096 ;
    END
  END q6[35]
  PIN q6[36]
    DIRECTION INPUT ;
    USE SIGNAL ;
    PORT
      LAYER M4 ;
        RECT  0 45.168 0.084 45.192 ;
    END
  END q6[36]
  PIN q6[37]
    DIRECTION INPUT ;
    USE SIGNAL ;
    PORT
      LAYER M4 ;
        RECT  0 45.264 0.084 45.288 ;
    END
  END q6[37]
  PIN q6[38]
    DIRECTION INPUT ;
    USE SIGNAL ;
    PORT
      LAYER M4 ;
        RECT  0 45.36 0.084 45.384 ;
    END
  END q6[38]
  PIN q6[39]
    DIRECTION INPUT ;
    USE SIGNAL ;
    PORT
      LAYER M4 ;
        RECT  0 45.456 0.084 45.48 ;
    END
  END q6[39]
  PIN q6[3]
    DIRECTION INPUT ;
    USE SIGNAL ;
    PORT
      LAYER M4 ;
        RECT  0 48.144 0.084 48.168 ;
    END
  END q6[3]
  PIN q6[40]
    DIRECTION INPUT ;
    USE SIGNAL ;
    PORT
      LAYER M4 ;
        RECT  0 45.552 0.084 45.576 ;
    END
  END q6[40]
  PIN q6[41]
    DIRECTION INPUT ;
    USE SIGNAL ;
    PORT
      LAYER M4 ;
        RECT  0 45.648 0.084 45.672 ;
    END
  END q6[41]
  PIN q6[42]
    DIRECTION INPUT ;
    USE SIGNAL ;
    PORT
      LAYER M4 ;
        RECT  0 45.744 0.084 45.768 ;
    END
  END q6[42]
  PIN q6[43]
    DIRECTION INPUT ;
    USE SIGNAL ;
    PORT
      LAYER M4 ;
        RECT  0 45.84 0.084 45.864 ;
    END
  END q6[43]
  PIN q6[44]
    DIRECTION INPUT ;
    USE SIGNAL ;
    PORT
      LAYER M4 ;
        RECT  0 45.936 0.084 45.96 ;
    END
  END q6[44]
  PIN q6[45]
    DIRECTION INPUT ;
    USE SIGNAL ;
    PORT
      LAYER M4 ;
        RECT  0 46.032 0.084 46.056 ;
    END
  END q6[45]
  PIN q6[46]
    DIRECTION INPUT ;
    USE SIGNAL ;
    PORT
      LAYER M4 ;
        RECT  0 46.128 0.084 46.152 ;
    END
  END q6[46]
  PIN q6[47]
    DIRECTION INPUT ;
    USE SIGNAL ;
    PORT
      LAYER M4 ;
        RECT  0 46.224 0.084 46.248 ;
    END
  END q6[47]
  PIN q6[48]
    DIRECTION INPUT ;
    USE SIGNAL ;
    PORT
      LAYER M4 ;
        RECT  0 46.32 0.084 46.344 ;
    END
  END q6[48]
  PIN q6[49]
    DIRECTION INPUT ;
    USE SIGNAL ;
    PORT
      LAYER M4 ;
        RECT  0 46.416 0.084 46.44 ;
    END
  END q6[49]
  PIN q6[4]
    DIRECTION INPUT ;
    USE SIGNAL ;
    PORT
      LAYER M4 ;
        RECT  0 48.24 0.084 48.264 ;
    END
  END q6[4]
  PIN q6[50]
    DIRECTION INPUT ;
    USE SIGNAL ;
    PORT
      LAYER M4 ;
        RECT  0 46.512 0.084 46.536 ;
    END
  END q6[50]
  PIN q6[51]
    DIRECTION INPUT ;
    USE SIGNAL ;
    PORT
      LAYER M4 ;
        RECT  0 46.608 0.084 46.632 ;
    END
  END q6[51]
  PIN q6[52]
    DIRECTION INPUT ;
    USE SIGNAL ;
    PORT
      LAYER M4 ;
        RECT  0 46.704 0.084 46.728 ;
    END
  END q6[52]
  PIN q6[53]
    DIRECTION INPUT ;
    USE SIGNAL ;
    PORT
      LAYER M4 ;
        RECT  0 46.8 0.084 46.824 ;
    END
  END q6[53]
  PIN q6[54]
    DIRECTION INPUT ;
    USE SIGNAL ;
    PORT
      LAYER M4 ;
        RECT  0 46.896 0.084 46.92 ;
    END
  END q6[54]
  PIN q6[55]
    DIRECTION INPUT ;
    USE SIGNAL ;
    PORT
      LAYER M4 ;
        RECT  0 46.992 0.084 47.016 ;
    END
  END q6[55]
  PIN q6[56]
    DIRECTION INPUT ;
    USE SIGNAL ;
    PORT
      LAYER M4 ;
        RECT  0 47.088 0.084 47.112 ;
    END
  END q6[56]
  PIN q6[57]
    DIRECTION INPUT ;
    USE SIGNAL ;
    PORT
      LAYER M4 ;
        RECT  0 47.184 0.084 47.208 ;
    END
  END q6[57]
  PIN q6[58]
    DIRECTION INPUT ;
    USE SIGNAL ;
    PORT
      LAYER M4 ;
        RECT  0 47.28 0.084 47.304 ;
    END
  END q6[58]
  PIN q6[59]
    DIRECTION INPUT ;
    USE SIGNAL ;
    PORT
      LAYER M4 ;
        RECT  0 47.376 0.084 47.4 ;
    END
  END q6[59]
  PIN q6[5]
    DIRECTION INPUT ;
    USE SIGNAL ;
    PORT
      LAYER M4 ;
        RECT  0 48.336 0.084 48.36 ;
    END
  END q6[5]
  PIN q6[60]
    DIRECTION INPUT ;
    USE SIGNAL ;
    PORT
      LAYER M4 ;
        RECT  0 55.536 0.084 55.56 ;
    END
  END q6[60]
  PIN q6[61]
    DIRECTION INPUT ;
    USE SIGNAL ;
    PORT
      LAYER M4 ;
        RECT  0 55.632 0.084 55.656 ;
    END
  END q6[61]
  PIN q6[62]
    DIRECTION INPUT ;
    USE SIGNAL ;
    PORT
      LAYER M4 ;
        RECT  0 55.728 0.084 55.752 ;
    END
  END q6[62]
  PIN q6[63]
    DIRECTION INPUT ;
    USE SIGNAL ;
    PORT
      LAYER M4 ;
        RECT  0 55.824 0.084 55.848 ;
    END
  END q6[63]
  PIN q6[64]
    DIRECTION INPUT ;
    USE SIGNAL ;
    PORT
      LAYER M4 ;
        RECT  0 55.92 0.084 55.944 ;
    END
  END q6[64]
  PIN q6[65]
    DIRECTION INPUT ;
    USE SIGNAL ;
    PORT
      LAYER M4 ;
        RECT  0 56.016 0.084 56.04 ;
    END
  END q6[65]
  PIN q6[66]
    DIRECTION INPUT ;
    USE SIGNAL ;
    PORT
      LAYER M4 ;
        RECT  0 56.112 0.084 56.136 ;
    END
  END q6[66]
  PIN q6[67]
    DIRECTION INPUT ;
    USE SIGNAL ;
    PORT
      LAYER M4 ;
        RECT  0 56.208 0.084 56.232 ;
    END
  END q6[67]
  PIN q6[68]
    DIRECTION INPUT ;
    USE SIGNAL ;
    PORT
      LAYER M4 ;
        RECT  0 56.304 0.084 56.328 ;
    END
  END q6[68]
  PIN q6[69]
    DIRECTION INPUT ;
    USE SIGNAL ;
    PORT
      LAYER M4 ;
        RECT  0 56.4 0.084 56.424 ;
    END
  END q6[69]
  PIN q6[6]
    DIRECTION INPUT ;
    USE SIGNAL ;
    PORT
      LAYER M4 ;
        RECT  0 48.432 0.084 48.456 ;
    END
  END q6[6]
  PIN q6[70]
    DIRECTION INPUT ;
    USE SIGNAL ;
    PORT
      LAYER M4 ;
        RECT  0 56.496 0.084 56.52 ;
    END
  END q6[70]
  PIN q6[71]
    DIRECTION INPUT ;
    USE SIGNAL ;
    PORT
      LAYER M4 ;
        RECT  0 56.592 0.084 56.616 ;
    END
  END q6[71]
  PIN q6[7]
    DIRECTION INPUT ;
    USE SIGNAL ;
    PORT
      LAYER M4 ;
        RECT  0 48.528 0.084 48.552 ;
    END
  END q6[7]
  PIN q6[8]
    DIRECTION INPUT ;
    USE SIGNAL ;
    PORT
      LAYER M4 ;
        RECT  0 48.624 0.084 48.648 ;
    END
  END q6[8]
  PIN q6[9]
    DIRECTION INPUT ;
    USE SIGNAL ;
    PORT
      LAYER M4 ;
        RECT  0 48.72 0.084 48.744 ;
    END
  END q6[9]
  PIN rst_n[0]
    DIRECTION INPUT ;
    USE SIGNAL ;
    PORT
      LAYER M5 ;
        RECT  9.552 0 9.576 0.084 ;
    END
    PORT
      LAYER M5 ;
        RECT  9.552 0.016 9.576 2.137 ;
    END
  END rst_n[0]
  PIN st[0]
    DIRECTION OUTPUT ;
    USE SIGNAL ;
    PORT
      LAYER M4 ;
        RECT  30.156 22.992 30.24 23.016 ;
    END
  END st[0]
  PIN st[1]
    DIRECTION OUTPUT ;
    USE SIGNAL ;
    PORT
      LAYER M4 ;
        RECT  30.156 23.088 30.24 23.112 ;
    END
  END st[1]
  PIN VDD
    DIRECTION INOUT ;
    USE POWER ;
    PORT
      LAYER M5 ;
        RECT  26.892 2.151 27.012 58.329 ;
        RECT  24.192 2.151 24.312 58.329 ;
        RECT  21.492 2.151 21.612 58.329 ;
        RECT  18.792 2.151 18.912 58.329 ;
        RECT  16.092 2.151 16.212 58.329 ;
        RECT  13.392 2.151 13.512 58.329 ;
        RECT  10.692 2.151 10.812 58.329 ;
        RECT  7.992 2.151 8.112 58.329 ;
        RECT  5.292 2.151 5.412 58.329 ;
        RECT  2.592 2.151 2.712 58.329 ;
    END
  END VDD
  PIN VSS
    DIRECTION INOUT ;
    USE GROUND ;
    PORT
      LAYER M5 ;
        RECT  26.7 2.137 26.82 58.343 ;
        RECT  24 2.137 24.12 58.343 ;
        RECT  21.3 2.137 21.42 58.343 ;
        RECT  18.6 2.137 18.72 58.343 ;
        RECT  15.9 2.137 16.02 58.343 ;
        RECT  13.2 2.137 13.32 58.343 ;
        RECT  10.5 2.137 10.62 58.343 ;
        RECT  7.8 2.137 7.92 58.343 ;
        RECT  5.1 2.137 5.22 58.343 ;
        RECT  2.4 2.137 2.52 58.343 ;
    END
  END VSS
  # OT_OBS_CLOSED layer=M5 d_um=1.536 added=94
  OBS
    LAYER RVTN ;
     RECT  2.16 2.16 28.08 2.295 ;
     RECT  2.16 2.565 28.08 2.835 ;
     RECT  2.16 3.105 28.08 3.375 ;
     RECT  2.16 3.645 28.08 3.915 ;
     RECT  2.16 4.185 28.08 4.455 ;
     RECT  2.16 4.725 28.08 4.995 ;
     RECT  2.16 5.265 28.08 5.535 ;
     RECT  2.16 5.805 28.08 6.075 ;
     RECT  2.16 6.345 28.08 6.615 ;
     RECT  2.16 6.885 28.08 7.155 ;
     RECT  2.16 7.425 28.08 7.695 ;
     RECT  2.16 7.965 28.08 8.235 ;
     RECT  2.16 8.505 28.08 8.775 ;
     RECT  2.16 9.045 28.08 9.315 ;
     RECT  2.16 9.585 28.08 9.855 ;
     RECT  2.16 10.125 28.08 10.395 ;
     RECT  2.16 10.665 28.08 10.935 ;
     RECT  2.16 11.205 28.08 11.475 ;
     RECT  2.16 11.745 28.08 12.015 ;
     RECT  2.16 12.285 28.08 12.555 ;
     RECT  2.16 12.825 28.08 13.095 ;
     RECT  2.16 13.365 28.08 13.635 ;
     RECT  2.16 13.905 28.08 14.175 ;
     RECT  2.16 14.445 28.08 14.715 ;
     RECT  2.16 14.985 28.08 15.255 ;
     RECT  2.16 15.525 28.08 15.795 ;
     RECT  2.16 16.065 28.08 16.335 ;
     RECT  2.16 16.605 28.08 16.875 ;
     RECT  2.16 17.145 28.08 17.415 ;
     RECT  2.16 17.685 28.08 17.955 ;
     RECT  2.16 18.225 28.08 18.495 ;
     RECT  2.16 18.765 28.08 19.035 ;
     RECT  2.16 19.305 28.08 19.575 ;
     RECT  2.16 19.845 28.08 20.115 ;
     RECT  2.16 20.385 28.08 20.655 ;
     RECT  2.16 20.925 28.08 21.195 ;
     RECT  2.16 21.465 28.08 21.735 ;
     RECT  2.16 22.005 28.08 22.275 ;
     RECT  2.16 22.545 28.08 22.815 ;
     RECT  2.16 23.085 28.08 23.355 ;
     RECT  2.16 23.625 28.08 23.895 ;
     RECT  2.16 24.165 28.08 24.435 ;
     RECT  2.16 24.705 28.08 24.975 ;
     RECT  2.16 25.245 28.08 25.515 ;
     RECT  2.16 25.785 28.08 26.055 ;
     RECT  2.16 26.325 28.08 26.595 ;
     RECT  2.16 26.865 28.08 27.135 ;
     RECT  2.16 27.405 28.08 27.675 ;
     RECT  2.16 27.945 28.08 28.215 ;
     RECT  2.16 28.485 28.08 28.755 ;
     RECT  2.16 29.025 28.08 29.295 ;
     RECT  2.16 29.565 28.08 29.835 ;
     RECT  2.16 30.105 28.08 30.375 ;
     RECT  2.16 30.645 28.08 30.915 ;
     RECT  2.16 31.185 28.08 31.455 ;
     RECT  2.16 31.725 28.08 31.995 ;
     RECT  2.16 32.265 28.08 32.535 ;
     RECT  2.16 32.805 28.08 33.075 ;
     RECT  2.16 33.345 28.08 33.615 ;
     RECT  2.16 33.885 28.08 34.155 ;
     RECT  2.16 34.425 28.08 34.695 ;
     RECT  2.16 34.965 28.08 35.235 ;
     RECT  2.16 35.505 28.08 35.775 ;
     RECT  2.16 36.045 28.08 36.315 ;
     RECT  2.16 36.585 28.08 36.855 ;
     RECT  2.16 37.125 28.08 37.395 ;
     RECT  2.16 37.665 28.08 37.935 ;
     RECT  2.16 38.205 28.08 38.475 ;
     RECT  2.16 38.745 28.08 39.015 ;
     RECT  2.16 39.285 28.08 39.555 ;
     RECT  2.16 39.825 28.08 40.095 ;
     RECT  2.16 40.365 28.08 40.635 ;
     RECT  2.16 40.905 28.08 41.175 ;
     RECT  2.16 41.445 28.08 41.715 ;
     RECT  2.16 41.985 28.08 42.255 ;
     RECT  2.16 42.525 28.08 42.795 ;
     RECT  2.16 43.065 28.08 43.335 ;
     RECT  2.16 43.605 28.08 43.875 ;
     RECT  2.16 44.145 28.08 44.415 ;
     RECT  2.16 44.685 28.08 44.955 ;
     RECT  2.16 45.225 28.08 45.495 ;
     RECT  2.16 45.765 28.08 46.035 ;
     RECT  2.16 46.305 28.08 46.575 ;
     RECT  2.16 46.845 28.08 47.115 ;
     RECT  2.16 47.385 28.08 47.655 ;
     RECT  2.16 47.925 28.08 48.195 ;
     RECT  2.16 48.465 28.08 48.735 ;
     RECT  2.16 49.005 28.08 49.275 ;
     RECT  2.16 49.545 28.08 49.815 ;
     RECT  2.16 50.085 28.08 50.355 ;
     RECT  2.16 50.625 28.08 50.895 ;
     RECT  2.16 51.165 28.08 51.435 ;
     RECT  2.16 51.705 28.08 51.975 ;
     RECT  2.16 52.245 28.08 52.515 ;
     RECT  2.16 52.785 28.08 53.055 ;
     RECT  2.16 53.325 28.08 53.595 ;
     RECT  2.16 53.865 28.08 54.135 ;
     RECT  2.16 54.405 28.08 54.675 ;
     RECT  2.16 54.945 28.08 55.215 ;
     RECT  2.16 55.485 28.08 55.755 ;
     RECT  2.16 56.025 28.08 56.295 ;
     RECT  2.16 56.565 28.08 56.835 ;
     RECT  2.16 57.105 28.08 57.375 ;
     RECT  2.16 57.645 28.08 57.915 ;
     RECT  2.16 58.185 28.08 58.32 ;
    LAYER RVTP ;
     RECT  2.16 2.295 28.08 2.565 ;
     RECT  2.16 2.835 28.08 3.105 ;
     RECT  2.16 3.375 28.08 3.645 ;
     RECT  2.16 3.915 28.08 4.185 ;
     RECT  2.16 4.455 28.08 4.725 ;
     RECT  2.16 4.995 28.08 5.265 ;
     RECT  2.16 5.535 28.08 5.805 ;
     RECT  2.16 6.075 28.08 6.345 ;
     RECT  2.16 6.615 28.08 6.885 ;
     RECT  2.16 7.155 28.08 7.425 ;
     RECT  2.16 7.695 28.08 7.965 ;
     RECT  2.16 8.235 28.08 8.505 ;
     RECT  2.16 8.775 28.08 9.045 ;
     RECT  2.16 9.315 28.08 9.585 ;
     RECT  2.16 9.855 28.08 10.125 ;
     RECT  2.16 10.395 28.08 10.665 ;
     RECT  2.16 10.935 28.08 11.205 ;
     RECT  2.16 11.475 28.08 11.745 ;
     RECT  2.16 12.015 28.08 12.285 ;
     RECT  2.16 12.555 28.08 12.825 ;
     RECT  2.16 13.095 28.08 13.365 ;
     RECT  2.16 13.635 28.08 13.905 ;
     RECT  2.16 14.175 28.08 14.445 ;
     RECT  2.16 14.715 28.08 14.985 ;
     RECT  2.16 15.255 28.08 15.525 ;
     RECT  2.16 15.795 28.08 16.065 ;
     RECT  2.16 16.335 28.08 16.605 ;
     RECT  2.16 16.875 28.08 17.145 ;
     RECT  2.16 17.415 28.08 17.685 ;
     RECT  2.16 17.955 28.08 18.225 ;
     RECT  2.16 18.495 28.08 18.765 ;
     RECT  2.16 19.035 28.08 19.305 ;
     RECT  2.16 19.575 28.08 19.845 ;
     RECT  2.16 20.115 28.08 20.385 ;
     RECT  2.16 20.655 28.08 20.925 ;
     RECT  2.16 21.195 28.08 21.465 ;
     RECT  2.16 21.735 28.08 22.005 ;
     RECT  2.16 22.275 28.08 22.545 ;
     RECT  2.16 22.815 28.08 23.085 ;
     RECT  2.16 23.355 28.08 23.625 ;
     RECT  2.16 23.895 28.08 24.165 ;
     RECT  2.16 24.435 28.08 24.705 ;
     RECT  2.16 24.975 28.08 25.245 ;
     RECT  2.16 25.515 28.08 25.785 ;
     RECT  2.16 26.055 28.08 26.325 ;
     RECT  2.16 26.595 28.08 26.865 ;
     RECT  2.16 27.135 28.08 27.405 ;
     RECT  2.16 27.675 28.08 27.945 ;
     RECT  2.16 28.215 28.08 28.485 ;
     RECT  2.16 28.755 28.08 29.025 ;
     RECT  2.16 29.295 28.08 29.565 ;
     RECT  2.16 29.835 28.08 30.105 ;
     RECT  2.16 30.375 28.08 30.645 ;
     RECT  2.16 30.915 28.08 31.185 ;
     RECT  2.16 31.455 28.08 31.725 ;
     RECT  2.16 31.995 28.08 32.265 ;
     RECT  2.16 32.535 28.08 32.805 ;
     RECT  2.16 33.075 28.08 33.345 ;
     RECT  2.16 33.615 28.08 33.885 ;
     RECT  2.16 34.155 28.08 34.425 ;
     RECT  2.16 34.695 28.08 34.965 ;
     RECT  2.16 35.235 28.08 35.505 ;
     RECT  2.16 35.775 28.08 36.045 ;
     RECT  2.16 36.315 28.08 36.585 ;
     RECT  2.16 36.855 28.08 37.125 ;
     RECT  2.16 37.395 28.08 37.665 ;
     RECT  2.16 37.935 28.08 38.205 ;
     RECT  2.16 38.475 28.08 38.745 ;
     RECT  2.16 39.015 28.08 39.285 ;
     RECT  2.16 39.555 28.08 39.825 ;
     RECT  2.16 40.095 28.08 40.365 ;
     RECT  2.16 40.635 28.08 40.905 ;
     RECT  2.16 41.175 28.08 41.445 ;
     RECT  2.16 41.715 28.08 41.985 ;
     RECT  2.16 42.255 28.08 42.525 ;
     RECT  2.16 42.795 28.08 43.065 ;
     RECT  2.16 43.335 28.08 43.605 ;
     RECT  2.16 43.875 28.08 44.145 ;
     RECT  2.16 44.415 28.08 44.685 ;
     RECT  2.16 44.955 28.08 45.225 ;
     RECT  2.16 45.495 28.08 45.765 ;
     RECT  2.16 46.035 28.08 46.305 ;
     RECT  2.16 46.575 28.08 46.845 ;
     RECT  2.16 47.115 28.08 47.385 ;
     RECT  2.16 47.655 28.08 47.925 ;
     RECT  2.16 48.195 28.08 48.465 ;
     RECT  2.16 48.735 28.08 49.005 ;
     RECT  2.16 49.275 28.08 49.545 ;
     RECT  2.16 49.815 28.08 50.085 ;
     RECT  2.16 50.355 28.08 50.625 ;
     RECT  2.16 50.895 28.08 51.165 ;
     RECT  2.16 51.435 28.08 51.705 ;
     RECT  2.16 51.975 28.08 52.245 ;
     RECT  2.16 52.515 28.08 52.785 ;
     RECT  2.16 53.055 28.08 53.325 ;
     RECT  2.16 53.595 28.08 53.865 ;
     RECT  2.16 54.135 28.08 54.405 ;
     RECT  2.16 54.675 28.08 54.945 ;
     RECT  2.16 55.215 28.08 55.485 ;
     RECT  2.16 55.755 28.08 56.025 ;
     RECT  2.16 56.295 28.08 56.565 ;
     RECT  2.16 56.835 28.08 57.105 ;
     RECT  2.16 57.375 28.08 57.645 ;
     RECT  2.16 57.915 28.08 58.185 ;
    LAYER M1 ;
     RECT  2.16 2.151 28.08 58.329 ;
    LAYER M2 ;
     RECT  0.031 6.66 0.103 6.678 ;
     RECT  0.031 9.171 0.103 9.189 ;
     RECT  0.103 9.171 0.131 9.918 ;
     RECT  0.103 2.772 0.139 3.402 ;
     RECT  0.103 16.11 0.139 16.128 ;
     RECT  0.103 17.424 0.139 17.514 ;
     RECT  0.103 24.174 0.139 24.192 ;
     RECT  0.103 28.962 0.139 29.628 ;
     RECT  0.103 42.534 0.139 42.552 ;
     RECT  0.103 45.54 0.139 45.558 ;
     RECT  0.131 9.252 0.175 9.918 ;
     RECT  0.103 14.49 0.175 14.508 ;
     RECT  0.103 33.66 0.175 35.298 ;
     RECT  0.103 55.692 0.175 55.71 ;
     RECT  0.103 32.076 0.203 32.49 ;
     RECT  0.103 6.66 0.211 7.416 ;
     RECT  0.175 8.28 0.211 8.298 ;
     RECT  0.175 33.66 0.239 35.838 ;
     RECT  0.103 43.812 0.239 43.83 ;
     RECT  0.175 26.028 0.247 26.046 ;
     RECT  0.139 45 0.247 45.558 ;
     RECT  0.211 19.044 0.347 19.062 ;
     RECT  0.247 43.956 0.347 45.558 ;
     RECT  0.175 55.692 0.347 56.394 ;
     RECT  0.103 30.582 0.383 30.708 ;
     RECT  0.319 5.616 0.419 5.634 ;
     RECT  0.175 4.734 0.463 4.752 ;
     RECT  0.139 24.174 0.499 24.228 ;
     RECT  0.103 39.87 0.499 39.888 ;
     RECT  0.139 17.082 0.535 17.514 ;
     RECT  0.499 23.706 0.535 24.228 ;
     RECT  0.139 28.764 0.535 29.628 ;
     RECT  0.203 32.472 0.535 32.49 ;
     RECT  0.175 14.112 1.147 14.508 ;
     RECT  0.347 43.956 1.175 45.018 ;
     RECT  0.535 22.554 1.183 22.572 ;
     RECT  1.183 21.942 1.283 22.572 ;
     RECT  0.535 11.178 1.723 11.772 ;
     RECT  0.239 34.632 1.723 35.838 ;
     RECT  1.283 22.554 2.155 22.572 ;
     RECT  0.535 23.706 2.155 24.426 ;
     RECT  0.139 2.61 2.16 3.402 ;
     RECT  0.463 4.266 2.16 4.752 ;
     RECT  0.211 6.426 2.16 8.298 ;
     RECT  0.175 9.252 2.16 10.08 ;
     RECT  1.723 10.944 2.16 11.772 ;
     RECT  1.147 14.112 2.16 14.778 ;
     RECT  0.139 16.038 2.16 16.128 ;
     RECT  0.535 16.956 2.16 17.712 ;
     RECT  1.147 20.322 2.16 20.34 ;
     RECT  2.083 21.402 2.16 21.42 ;
     RECT  2.155 22.554 2.16 24.426 ;
     RECT  0.247 25.722 2.16 26.046 ;
     RECT  1.723 26.874 2.16 26.892 ;
     RECT  0.535 28.296 2.16 29.628 ;
     RECT  0.383 30.69 2.16 30.708 ;
     RECT  0.535 32.472 2.16 32.868 ;
     RECT  1.723 34.632 2.16 36.342 ;
     RECT  0.535 37.206 2.16 37.224 ;
     RECT  1.723 38.826 2.16 38.844 ;
     RECT  0.499 39.87 2.16 40.428 ;
     RECT  0.535 41.724 2.16 41.742 ;
     RECT  0.139 42.534 2.16 42.75 ;
     RECT  1.175 43.956 2.16 44.91 ;
     RECT  1.723 54.216 2.16 54.234 ;
     RECT  0.347 55.692 2.16 55.71 ;
     RECT  2.16 2.151 3.487 58.329 ;
     RECT  3.487 2.106 4.739 58.329 ;
     RECT  4.739 2.151 20.371 58.329 ;
     RECT  20.371 2.151 21.235 58.374 ;
     RECT  21.235 2.151 21.443 58.986 ;
     RECT  21.883 60.426 22.811 60.444 ;
     RECT  25.159 59.85 25.483 59.868 ;
     RECT  21.443 2.151 25.591 58.329 ;
     RECT  25.591 2.151 25.807 58.374 ;
     RECT  25.483 59.274 25.879 59.868 ;
     RECT  25.807 2.151 25.907 58.446 ;
     RECT  25.879 59.274 25.951 60.372 ;
     RECT  25.951 59.274 26.087 60.444 ;
     RECT  26.087 59.274 26.339 59.868 ;
     RECT  26.339 59.85 27.067 59.868 ;
     RECT  25.907 2.151 27.203 58.41 ;
     RECT  27.067 59.85 27.203 60.444 ;
     RECT  27.203 59.85 27.995 59.868 ;
     RECT  27.203 2.151 28.08 58.329 ;
     RECT  28.08 50.868 28.103 50.886 ;
     RECT  28.08 52.146 28.103 52.164 ;
     RECT  28.08 54.108 28.103 54.432 ;
     RECT  28.08 56.196 28.103 57.024 ;
     RECT  28.103 54.108 28.175 54.126 ;
     RECT  28.103 57.006 28.175 57.024 ;
     RECT  28.08 21.168 28.859 24.498 ;
     RECT  28.859 21.168 29.075 23.814 ;
     RECT  29.075 21.168 29.111 22.734 ;
     RECT  29.111 21.168 29.147 22.104 ;
     RECT  29.075 23.796 29.651 23.814 ;
     RECT  29.147 21.744 30.083 22.104 ;
     RECT  30.083 21.744 30.119 21.798 ;
     RECT  30.119 21.78 30.155 21.798 ;
    LAYER M3 ;
     RECT  4.716 2.101 4.734 2.143 ;
     RECT  5.796 2.059 5.814 2.143 ;
     RECT  4.716 2.143 5.814 2.191 ;
     RECT  6.588 2.191 6.606 2.237 ;
     RECT  3.492 2.101 3.51 2.263 ;
     RECT  4.464 2.191 5.814 2.263 ;
     RECT  10.515 2.143 10.605 2.299 ;
     RECT  2.415 2.143 2.505 2.413 ;
     RECT  7.815 2.143 7.905 2.413 ;
     RECT  10.26 2.299 10.605 2.413 ;
     RECT  13.215 2.143 13.305 2.413 ;
     RECT  15.915 2.143 16.005 2.413 ;
     RECT  18.615 2.143 18.705 2.413 ;
     RECT  21.315 2.143 21.405 2.413 ;
     RECT  24.015 2.143 24.105 2.413 ;
     RECT  26.715 2.143 26.805 2.413 ;
     RECT  7.815 2.413 8.097 2.461 ;
     RECT  2.415 2.413 2.697 2.497 ;
     RECT  3.492 2.263 5.814 2.497 ;
     RECT  2.415 2.497 5.814 2.641 ;
     RECT  0.144 2.605 0.162 2.767 ;
     RECT  2.415 2.641 6.138 2.767 ;
     RECT  10.26 2.413 10.797 2.795 ;
     RECT  0.108 2.767 0.162 3.001 ;
     RECT  2.376 2.767 6.138 3.001 ;
     RECT  0.108 3.001 0.522 3.073 ;
     RECT  2.376 3.001 6.282 3.109 ;
     RECT  7.02 2.461 8.097 3.109 ;
     RECT  2.376 3.109 8.097 3.115 ;
     RECT  10.515 2.795 10.797 3.721 ;
     RECT  0.108 3.073 0.558 4.109 ;
     RECT  0.18 4.109 0.558 4.397 ;
     RECT  0.18 4.397 0.522 4.493 ;
     RECT  8.82 4.261 8.838 4.531 ;
     RECT  9.864 3.721 10.797 4.531 ;
     RECT  0.18 4.493 0.486 4.973 ;
     RECT  11.592 5.179 11.61 5.225 ;
     RECT  0.18 4.973 0.414 5.515 ;
     RECT  2.304 3.115 8.097 5.611 ;
     RECT  8.82 4.531 10.797 5.611 ;
     RECT  0.144 5.515 0.414 5.639 ;
     RECT  0.144 5.639 0.342 5.648 ;
     RECT  2.304 5.611 10.797 5.659 ;
     RECT  2.268 5.659 10.797 5.837 ;
     RECT  13.215 2.413 13.497 6.241 ;
     RECT  0.144 5.648 0.162 6.421 ;
     RECT  2.304 5.837 10.797 6.605 ;
     RECT  0.144 6.421 0.234 6.655 ;
     RECT  0.036 6.655 0.234 6.691 ;
     RECT  2.304 6.605 6.354 6.817 ;
     RECT  2.232 6.817 6.354 6.941 ;
     RECT  7.128 6.605 10.797 7.321 ;
     RECT  11.7 5.341 11.718 7.321 ;
     RECT  2.268 6.941 6.354 7.483 ;
     RECT  7.128 7.321 11.718 7.483 ;
     RECT  2.268 7.483 11.718 8.311 ;
     RECT  2.268 8.311 11.826 8.743 ;
     RECT  12.564 6.241 13.497 8.743 ;
     RECT  2.268 8.743 13.497 9.005 ;
     RECT  0.036 6.691 0.558 9.194 ;
     RECT  2.304 9.005 13.497 9.835 ;
     RECT  0.108 9.194 0.558 10.157 ;
     RECT  0.108 10.157 0.342 10.637 ;
     RECT  1.728 9.835 13.497 10.967 ;
     RECT  0.18 10.637 0.342 11.173 ;
     RECT  2.268 10.967 13.497 11.507 ;
     RECT  0.18 11.173 0.558 11.707 ;
     RECT  0.144 11.707 0.558 12.077 ;
     RECT  2.304 11.507 13.497 12.331 ;
     RECT  0.144 12.077 0.342 12.845 ;
     RECT  0.216 12.845 0.234 13.085 ;
     RECT  1.152 12.235 1.17 13.579 ;
     RECT  2.268 12.331 13.497 13.579 ;
     RECT  0.144 13.963 0.162 14.107 ;
     RECT  0.144 14.107 0.198 14.215 ;
     RECT  1.152 13.579 13.497 14.215 ;
     RECT  0.144 14.215 13.497 14.285 ;
     RECT  1.152 14.285 13.497 14.441 ;
     RECT  0.144 14.285 0.378 14.485 ;
     RECT  0.108 14.485 0.378 14.669 ;
     RECT  2.232 14.441 13.497 14.711 ;
     RECT  1.152 14.441 1.17 14.783 ;
     RECT  0.108 14.669 0.198 15.293 ;
     RECT  0.108 15.293 0.162 15.341 ;
     RECT  2.304 14.711 13.497 15.592 ;
     RECT  2.268 15.592 13.497 15.629 ;
     RECT  0.144 15.341 0.162 16.105 ;
     RECT  0.108 16.105 0.162 16.589 ;
     RECT  2.304 15.629 13.497 16.915 ;
     RECT  0.144 16.589 0.162 16.951 ;
     RECT  2.304 16.915 13.842 16.951 ;
     RECT  14.904 16.771 14.922 16.951 ;
     RECT  2.304 16.951 14.058 17.077 ;
     RECT  14.868 16.951 14.922 17.077 ;
     RECT  15.915 2.413 16.197 17.077 ;
     RECT  0.144 16.951 0.558 17.083 ;
     RECT  0.144 17.083 1.17 17.261 ;
     RECT  0.144 17.261 0.558 17.419 ;
     RECT  2.304 17.077 16.197 17.419 ;
     RECT  2.304 17.419 16.578 17.879 ;
     RECT  0.108 17.419 0.558 17.995 ;
     RECT  2.304 17.879 16.47 18.023 ;
     RECT  21.315 2.413 21.597 18.265 ;
     RECT  0.108 17.995 1.17 18.317 ;
     RECT  20.736 18.265 21.597 18.427 ;
     RECT  19.944 18.571 19.962 18.689 ;
     RECT  22.824 18.391 22.842 18.769 ;
     RECT  19.8 18.697 19.818 18.797 ;
     RECT  2.304 18.023 16.326 18.841 ;
     RECT  22.824 18.769 23.13 18.841 ;
     RECT  20.736 18.427 21.654 18.907 ;
     RECT  2.232 18.841 16.326 18.967 ;
     RECT  17.568 10.021 17.586 18.967 ;
     RECT  0.216 18.317 1.17 19.051 ;
     RECT  20.628 18.907 21.654 19.075 ;
     RECT  18.615 2.413 18.897 19.111 ;
     RECT  20.628 19.075 21.762 19.111 ;
     RECT  18.615 19.111 18.954 19.229 ;
     RECT  0.18 19.051 1.17 19.325 ;
     RECT  22.644 18.841 23.13 19.345 ;
     RECT  20.628 19.111 21.906 19.373 ;
     RECT  20.844 19.373 21.906 19.471 ;
     RECT  22.644 19.345 23.166 19.471 ;
     RECT  20.088 19.543 20.106 19.651 ;
     RECT  20.844 19.471 23.166 19.651 ;
     RECT  24.015 2.413 24.297 19.651 ;
     RECT  20.016 19.651 20.106 19.679 ;
     RECT  20.016 19.679 20.034 19.769 ;
     RECT  19.872 19.915 19.89 19.955 ;
     RECT  2.232 18.967 17.586 20.075 ;
     RECT  0.324 19.325 1.17 20.141 ;
     RECT  18.615 19.229 18.897 20.191 ;
     RECT  20.844 19.651 24.297 20.191 ;
     RECT  18.432 20.191 18.897 20.317 ;
     RECT  0.396 20.141 1.17 20.345 ;
     RECT  18.432 20.317 18.99 20.353 ;
     RECT  2.268 20.075 17.586 20.389 ;
     RECT  18.432 20.353 19.098 20.389 ;
     RECT  2.268 20.389 19.098 20.425 ;
     RECT  0.396 20.345 0.45 20.429 ;
     RECT  20.772 20.191 24.297 20.539 ;
     RECT  2.268 20.425 19.422 20.695 ;
     RECT  20.34 20.539 24.297 20.695 ;
     RECT  26.715 2.413 26.997 20.857 ;
     RECT  0.396 20.429 0.414 20.861 ;
     RECT  25.668 19.309 25.686 20.965 ;
     RECT  26.715 20.857 27.486 20.965 ;
     RECT  2.268 20.695 24.297 20.971 ;
     RECT  2.232 20.971 24.297 21.163 ;
     RECT  25.668 20.965 27.486 21.199 ;
     RECT  2.088 21.163 24.297 21.235 ;
     RECT  29.124 21.163 29.142 21.235 ;
     RECT  25.668 21.199 27.63 21.271 ;
     RECT  0.144 21.163 0.162 21.341 ;
     RECT  2.088 21.235 24.93 21.361 ;
     RECT  25.668 21.271 27.774 21.361 ;
     RECT  2.088 21.361 27.774 21.425 ;
     RECT  2.232 21.425 27.774 21.659 ;
     RECT  1.152 21.691 1.17 21.739 ;
     RECT  30.132 21.547 30.15 21.739 ;
     RECT  30.096 21.739 30.15 21.803 ;
     RECT  1.152 21.739 1.35 21.965 ;
     RECT  29.016 21.235 29.142 22.045 ;
     RECT  1.152 21.965 1.278 22.061 ;
     RECT  29.016 22.045 30.078 22.157 ;
     RECT  29.016 22.157 29.682 22.253 ;
     RECT  29.016 22.253 29.106 22.411 ;
     RECT  2.232 21.659 27.666 22.585 ;
     RECT  28.476 22.411 29.106 22.585 ;
     RECT  2.232 22.585 29.106 22.637 ;
     RECT  28.476 22.637 29.106 22.649 ;
     RECT  2.232 22.637 27.666 22.747 ;
     RECT  0.54 22.549 0.558 22.829 ;
     RECT  2.196 22.747 27.666 22.891 ;
     RECT  2.16 22.891 27.666 23.009 ;
     RECT  2.16 23.009 14.814 23.045 ;
     RECT  28.836 22.649 29.106 23.083 ;
     RECT  28.836 23.083 29.646 23.153 ;
     RECT  0.144 22.891 0.198 23.261 ;
     RECT  0.18 23.261 0.198 23.357 ;
     RECT  15.552 23.009 27.666 23.665 ;
     RECT  15.552 23.665 27.774 23.701 ;
     RECT  2.232 23.045 14.814 23.791 ;
     RECT  15.552 23.701 27.882 23.791 ;
     RECT  29.628 23.153 29.646 23.819 ;
     RECT  2.232 23.791 27.882 23.855 ;
     RECT  2.232 23.855 27.774 24.089 ;
     RECT  0.324 23.701 0.522 24.139 ;
     RECT  0.144 24.139 0.522 24.169 ;
     RECT  2.232 24.089 27.522 24.197 ;
     RECT  0.108 24.169 0.522 24.235 ;
     RECT  0.108 24.235 1.17 24.413 ;
     RECT  28.836 23.153 28.854 24.503 ;
     RECT  0.108 24.413 0.558 24.557 ;
     RECT  0.108 24.557 0.522 24.845 ;
     RECT  2.232 24.197 25.83 25.099 ;
     RECT  26.715 24.197 27.522 25.321 ;
     RECT  0.108 24.845 0.126 25.421 ;
     RECT  2.196 25.099 25.83 25.555 ;
     RECT  26.568 25.321 27.522 25.555 ;
     RECT  2.196 25.555 27.522 25.675 ;
     RECT  0.144 25.717 0.27 25.867 ;
     RECT  0.144 25.867 0.45 26.011 ;
     RECT  1.728 25.675 27.522 26.011 ;
     RECT  0.144 26.011 27.522 26.045 ;
     RECT  0.144 26.045 0.378 26.093 ;
     RECT  1.152 26.045 27.522 26.293 ;
     RECT  0.18 26.093 0.27 26.381 ;
     RECT  1.152 26.293 27.63 26.401 ;
     RECT  1.152 26.401 27.954 26.663 ;
     RECT  1.152 26.663 27.63 26.897 ;
     RECT  0.18 26.381 0.234 26.923 ;
     RECT  1.152 26.897 1.17 27.149 ;
     RECT  0.144 26.923 0.234 27.403 ;
     RECT  2.232 26.897 27.63 27.739 ;
     RECT  0.144 27.403 0.45 27.869 ;
     RECT  2.196 27.739 27.63 27.905 ;
     RECT  2.232 27.905 27.63 28.445 ;
     RECT  2.304 28.445 27.63 28.561 ;
     RECT  0.54 28.291 0.558 28.651 ;
     RECT  0.324 28.651 0.558 28.747 ;
     RECT  2.304 28.561 27.954 28.949 ;
     RECT  0.144 28.747 0.558 28.957 ;
     RECT  2.304 28.949 27.63 29.021 ;
     RECT  0.108 28.957 0.558 29.323 ;
     RECT  1.368 29.227 1.386 29.323 ;
     RECT  0.108 29.323 1.386 29.549 ;
     RECT  0.108 29.549 1.17 29.597 ;
     RECT  0.108 29.597 0.558 29.741 ;
     RECT  2.304 29.021 27.522 29.759 ;
     RECT  2.304 29.759 22.698 30.091 ;
     RECT  2.232 30.091 22.698 30.335 ;
     RECT  0.108 29.741 0.198 30.475 ;
     RECT  0.108 30.475 0.342 30.577 ;
     RECT  2.268 30.335 22.698 30.577 ;
     RECT  23.616 29.759 27.522 30.577 ;
     RECT  2.268 30.577 27.522 30.605 ;
     RECT  0.108 30.577 0.378 30.701 ;
     RECT  2.304 30.605 27.522 30.811 ;
     RECT  1.26 30.859 1.278 30.989 ;
     RECT  2.304 30.811 27.594 30.991 ;
     RECT  2.304 30.991 27.954 31.109 ;
     RECT  2.304 31.109 27.63 31.709 ;
     RECT  0.108 30.701 0.162 31.771 ;
     RECT  22.536 31.709 27.63 32.099 ;
     RECT  0.108 31.771 0.198 32.107 ;
     RECT  2.304 31.709 21.69 32.395 ;
     RECT  0.108 32.107 0.342 32.717 ;
     RECT  1.152 32.587 1.17 32.765 ;
     RECT  2.196 32.395 21.69 32.837 ;
     RECT  0.144 32.717 0.342 32.845 ;
     RECT  2.304 32.837 21.69 33.151 ;
     RECT  22.536 32.099 27.594 33.151 ;
     RECT  0.144 32.845 0.558 33.293 ;
     RECT  0.144 33.293 0.234 33.643 ;
     RECT  2.304 33.151 27.954 33.683 ;
     RECT  0.108 33.643 0.234 34.027 ;
     RECT  0.108 34.027 0.342 34.157 ;
     RECT  2.304 33.683 21.69 34.501 ;
     RECT  22.428 33.683 27.954 34.501 ;
     RECT  2.304 34.501 27.954 34.603 ;
     RECT  1.98 34.603 27.954 34.891 ;
     RECT  0.108 34.157 0.234 35.083 ;
     RECT  0.108 35.083 0.342 35.213 ;
     RECT  1.728 34.891 27.954 35.231 ;
     RECT  0.108 35.213 0.198 35.981 ;
     RECT  0.144 35.981 0.198 36.139 ;
     RECT  0.144 36.139 0.342 36.269 ;
     RECT  1.728 35.231 27.846 36.347 ;
     RECT  2.232 36.347 27.846 36.661 ;
     RECT  2.232 36.661 27.954 36.845 ;
     RECT  0.144 36.269 0.27 36.893 ;
     RECT  2.304 36.845 27.954 37.049 ;
     RECT  0.18 36.893 0.27 37.201 ;
     RECT  0.18 37.201 0.558 37.291 ;
     RECT  0.18 37.291 1.278 37.469 ;
     RECT  2.304 37.049 27.486 37.579 ;
     RECT  2.196 37.579 27.486 37.661 ;
     RECT  0.18 37.469 1.17 37.805 ;
     RECT  0.18 37.805 0.342 37.915 ;
     RECT  2.304 37.661 27.486 37.975 ;
     RECT  2.304 37.975 27.522 38.011 ;
     RECT  0.144 37.915 0.342 38.189 ;
     RECT  1.152 37.805 1.17 38.429 ;
     RECT  2.304 38.011 27.882 38.443 ;
     RECT  2.304 38.443 27.954 38.539 ;
     RECT  0.18 38.189 0.342 38.717 ;
     RECT  1.728 38.539 27.954 38.849 ;
     RECT  0.324 38.717 0.342 38.923 ;
     RECT  2.268 38.849 27.954 38.975 ;
     RECT  2.304 38.975 27.954 39.209 ;
     RECT  0.324 38.923 0.558 39.499 ;
     RECT  2.304 39.209 27.486 39.515 ;
     RECT  2.304 39.515 27.234 39.533 ;
     RECT  0.18 39.499 1.278 39.773 ;
     RECT  0.18 39.773 1.17 39.865 ;
     RECT  0.108 39.865 1.17 39.917 ;
     RECT  2.304 39.533 26.997 39.979 ;
     RECT  0.324 39.917 1.17 40.349 ;
     RECT  0.324 40.349 0.558 40.397 ;
     RECT  2.268 39.979 26.997 40.595 ;
     RECT  23.256 40.595 26.997 40.711 ;
     RECT  2.268 40.595 22.302 41.135 ;
     RECT  23.256 40.711 27.054 41.251 ;
     RECT  2.304 41.135 22.302 41.485 ;
     RECT  2.304 41.485 22.41 41.521 ;
     RECT  23.256 41.251 27.09 41.521 ;
     RECT  0.504 40.397 0.558 41.549 ;
     RECT  0.54 41.549 0.558 41.747 ;
     RECT  2.304 41.521 27.09 41.755 ;
     RECT  2.304 41.755 27.522 41.791 ;
     RECT  0.108 42.529 0.126 42.667 ;
     RECT  2.304 41.791 27.954 42.719 ;
     RECT  2.304 42.719 27.342 42.955 ;
     RECT  2.268 42.955 27.342 43.243 ;
     RECT  0.108 42.667 0.198 43.339 ;
     RECT  2.232 43.243 27.342 43.601 ;
     RECT  0.108 43.339 0.342 43.853 ;
     RECT  0.144 43.853 0.342 43.951 ;
     RECT  2.304 43.601 27.342 44.725 ;
     RECT  2.304 44.725 27.378 44.761 ;
     RECT  0.144 43.951 0.558 44.887 ;
     RECT  0.144 44.887 1.17 45.005 ;
     RECT  2.304 44.761 27.45 45.019 ;
     RECT  1.152 45.005 1.17 45.023 ;
     RECT  0.144 45.005 0.342 45.451 ;
     RECT  0.108 45.451 0.342 45.563 ;
     RECT  0.144 45.563 0.342 45.581 ;
     RECT  2.304 45.019 27.522 45.689 ;
     RECT  0.144 45.581 0.162 46.013 ;
     RECT  2.304 45.689 27.306 46.229 ;
     RECT  23.616 46.229 27.306 46.337 ;
     RECT  0.324 46.507 0.342 46.637 ;
     RECT  23.76 46.337 27.306 46.813 ;
     RECT  23.76 46.813 27.342 46.885 ;
     RECT  23.76 46.885 27.414 46.921 ;
     RECT  1.26 46.987 1.278 47.083 ;
     RECT  1.152 47.083 1.278 47.117 ;
     RECT  2.304 46.229 22.806 47.191 ;
     RECT  23.76 46.921 27.522 47.191 ;
     RECT  1.152 47.117 1.17 47.213 ;
     RECT  0.144 47.035 0.234 47.309 ;
     RECT  2.304 47.191 27.558 47.309 ;
     RECT  2.304 47.309 27.522 47.563 ;
     RECT  2.268 47.563 27.522 47.687 ;
     RECT  2.304 47.687 27.522 48.541 ;
     RECT  2.304 48.541 27.774 49.081 ;
     RECT  2.232 49.081 27.774 49.133 ;
     RECT  1.152 49.003 1.17 49.181 ;
     RECT  0.144 47.309 0.162 49.243 ;
     RECT  2.304 49.133 27.774 49.243 ;
     RECT  0.144 49.243 0.234 49.517 ;
     RECT  0.144 49.517 0.162 49.565 ;
     RECT  2.304 49.243 27.81 49.867 ;
     RECT  2.268 49.867 27.81 50.125 ;
     RECT  2.268 50.125 27.99 50.251 ;
     RECT  2.232 50.251 27.99 50.395 ;
     RECT  2.232 50.395 28.026 50.585 ;
     RECT  2.268 50.585 28.026 50.863 ;
     RECT  2.268 50.863 28.098 51.883 ;
     RECT  2.232 51.883 28.098 52.043 ;
     RECT  2.304 52.043 28.098 52.169 ;
     RECT  0.144 51.499 0.162 52.397 ;
     RECT  2.304 52.169 28.062 52.439 ;
     RECT  2.304 52.439 28.026 52.843 ;
     RECT  0.144 53.131 0.162 53.405 ;
     RECT  2.232 52.843 28.026 53.515 ;
     RECT  1.728 53.515 28.026 54.059 ;
     RECT  9.72 54.059 28.026 54.103 ;
     RECT  1.728 54.059 8.766 54.239 ;
     RECT  9.72 54.103 28.17 54.329 ;
     RECT  9.72 54.329 9.738 54.365 ;
     RECT  2.304 54.239 8.766 54.473 ;
     RECT  10.476 54.329 28.17 54.599 ;
     RECT  2.376 54.473 8.766 54.635 ;
     RECT  10.515 54.599 28.17 55.409 ;
     RECT  12.204 55.409 28.17 55.481 ;
     RECT  2.415 54.635 8.766 55.525 ;
     RECT  2.34 55.525 8.766 55.627 ;
     RECT  10.515 55.409 11.034 55.787 ;
     RECT  0.108 55.687 0.126 55.949 ;
     RECT  12.24 55.481 28.17 56.057 ;
     RECT  12.42 56.057 28.17 56.219 ;
     RECT  0.18 56.203 0.342 56.399 ;
     RECT  0.324 56.399 0.342 56.429 ;
     RECT  2.304 55.627 8.766 56.489 ;
     RECT  2.304 56.489 8.097 56.633 ;
     RECT  2.304 56.633 6.894 56.759 ;
     RECT  2.304 56.759 6.246 57.029 ;
     RECT  12.528 56.219 28.17 57.029 ;
     RECT  2.304 57.029 5.886 57.137 ;
     RECT  2.304 57.137 5.526 57.299 ;
     RECT  2.304 57.299 5.454 57.335 ;
     RECT  2.415 57.335 5.454 57.371 ;
     RECT  4.608 57.371 5.454 57.479 ;
     RECT  2.415 57.371 3.402 57.569 ;
     RECT  5.115 57.479 5.454 57.569 ;
     RECT  12.528 57.029 28.062 57.605 ;
     RECT  2.415 57.569 2.697 58.067 ;
     RECT  5.115 57.569 5.397 58.067 ;
     RECT  7.815 56.633 8.097 58.067 ;
     RECT  10.515 55.787 10.797 58.067 ;
     RECT  13.176 57.605 28.062 58.109 ;
     RECT  13.215 58.109 27.99 58.145 ;
     RECT  19.764 58.145 27.99 58.157 ;
     RECT  24.015 58.157 27.99 58.205 ;
     RECT  13.215 58.145 18.705 58.217 ;
     RECT  19.764 58.157 23.202 58.217 ;
     RECT  24.015 58.205 24.174 58.217 ;
     RECT  20.088 58.217 23.202 58.253 ;
     RECT  14.112 58.217 18.705 58.301 ;
     RECT  2.415 58.067 2.505 58.337 ;
     RECT  5.115 58.067 5.205 58.337 ;
     RECT  7.815 58.067 7.905 58.337 ;
     RECT  10.515 58.067 10.605 58.337 ;
     RECT  13.215 58.217 13.305 58.337 ;
     RECT  18.615 58.301 18.705 58.337 ;
     RECT  24.015 58.217 24.105 58.337 ;
     RECT  14.112 58.301 17.73 58.349 ;
     RECT  14.112 58.349 17.55 58.637 ;
     RECT  14.112 58.637 17.19 58.685 ;
     RECT  14.112 58.685 15.462 59.213 ;
     RECT  14.184 59.213 15.462 59.261 ;
     RECT  20.088 58.253 22.806 59.309 ;
     RECT  14.22 59.261 14.958 59.837 ;
     RECT  25.164 58.205 27.99 59.873 ;
     RECT  20.484 59.309 22.806 60.443 ;
     RECT  20.502 60.443 20.556 60.449 ;
     RECT  20.574 60.443 20.628 60.449 ;
     RECT  20.646 60.443 20.7 60.449 ;
     RECT  20.718 60.443 20.772 60.449 ;
     RECT  20.79 60.443 20.844 60.449 ;
     RECT  20.862 60.443 20.916 60.449 ;
     RECT  20.934 60.443 20.988 60.449 ;
     RECT  21.006 60.443 21.06 60.449 ;
     RECT  21.078 60.443 21.132 60.449 ;
     RECT  21.15 60.443 21.204 60.449 ;
     RECT  21.222 60.443 21.276 60.449 ;
     RECT  21.294 60.443 21.348 60.449 ;
     RECT  21.366 60.443 21.42 60.449 ;
     RECT  21.438 60.443 21.492 60.449 ;
     RECT  21.51 60.443 21.564 60.449 ;
     RECT  21.582 60.443 21.636 60.449 ;
     RECT  21.654 60.443 21.708 60.449 ;
     RECT  21.726 60.443 21.78 60.449 ;
     RECT  21.798 60.443 21.852 60.449 ;
     RECT  21.87 60.443 21.924 60.449 ;
     RECT  21.942 60.443 21.996 60.449 ;
     RECT  22.014 60.443 22.068 60.449 ;
     RECT  22.086 60.443 22.14 60.449 ;
     RECT  22.158 60.443 22.212 60.449 ;
     RECT  22.23 60.443 22.284 60.449 ;
     RECT  22.302 60.443 22.356 60.449 ;
     RECT  22.374 60.443 22.428 60.449 ;
     RECT  22.446 60.443 22.5 60.449 ;
     RECT  22.518 60.443 22.572 60.449 ;
     RECT  22.59 60.443 22.644 60.449 ;
     RECT  22.662 60.443 22.716 60.449 ;
     RECT  22.734 60.443 22.806 60.449 ;
     RECT  20.502 60.449 20.556 60.461 ;
     RECT  20.574 60.449 20.628 60.461 ;
     RECT  20.646 60.449 20.7 60.461 ;
     RECT  20.718 60.449 20.772 60.461 ;
     RECT  20.79 60.449 20.844 60.461 ;
     RECT  20.862 60.449 20.916 60.461 ;
     RECT  20.934 60.449 20.988 60.461 ;
     RECT  21.006 60.449 21.06 60.461 ;
     RECT  21.078 60.449 21.132 60.461 ;
     RECT  21.15 60.449 21.204 60.461 ;
     RECT  21.222 60.449 21.276 60.461 ;
     RECT  21.294 60.449 21.348 60.461 ;
     RECT  21.366 60.449 21.42 60.461 ;
     RECT  21.438 60.449 21.492 60.461 ;
     RECT  21.51 60.449 21.564 60.461 ;
     RECT  21.582 60.449 21.636 60.461 ;
     RECT  21.654 60.449 21.708 60.461 ;
     RECT  21.726 60.449 21.78 60.461 ;
     RECT  21.798 60.449 21.852 60.461 ;
     RECT  21.87 60.449 21.924 60.461 ;
     RECT  21.942 60.449 21.996 60.461 ;
     RECT  22.014 60.449 22.068 60.461 ;
     RECT  22.086 60.449 22.14 60.461 ;
     RECT  22.158 60.449 22.212 60.461 ;
     RECT  22.23 60.449 22.284 60.461 ;
     RECT  22.302 60.449 22.356 60.461 ;
     RECT  22.374 60.449 22.428 60.461 ;
     RECT  22.446 60.449 22.5 60.461 ;
     RECT  22.518 60.449 22.572 60.461 ;
     RECT  22.59 60.449 22.644 60.461 ;
     RECT  22.662 60.449 22.716 60.461 ;
     RECT  25.308 59.873 27.342 60.443 ;
     RECT  25.326 60.443 25.38 60.461 ;
     RECT  25.398 60.443 25.452 60.461 ;
     RECT  25.47 60.443 25.524 60.461 ;
     RECT  25.542 60.443 25.596 60.461 ;
     RECT  25.614 60.443 25.668 60.461 ;
     RECT  25.686 60.443 25.74 60.461 ;
     RECT  25.758 60.443 25.812 60.461 ;
     RECT  25.83 60.443 25.884 60.461 ;
     RECT  25.902 60.443 25.956 60.461 ;
     RECT  25.974 60.443 26.028 60.461 ;
     RECT  26.046 60.443 26.1 60.461 ;
     RECT  26.118 60.443 26.172 60.461 ;
     RECT  26.19 60.443 26.244 60.461 ;
     RECT  26.262 60.443 26.316 60.461 ;
     RECT  26.334 60.443 26.388 60.461 ;
     RECT  26.406 60.443 26.46 60.461 ;
     RECT  26.478 60.443 26.532 60.461 ;
     RECT  26.55 60.443 26.604 60.461 ;
     RECT  26.622 60.443 26.676 60.461 ;
     RECT  26.694 60.443 26.748 60.461 ;
     RECT  26.766 60.443 26.82 60.461 ;
     RECT  26.838 60.443 26.892 60.461 ;
     RECT  26.91 60.443 26.964 60.461 ;
     RECT  26.982 60.443 27.036 60.461 ;
     RECT  27.054 60.443 27.108 60.461 ;
     RECT  27.126 60.443 27.18 60.461 ;
     RECT  27.198 60.443 27.252 60.461 ;
     RECT  27.27 60.443 27.324 60.461 ;
    LAYER M4 ;
     RECT  0.084 2.928 2.408 2.952 ;
     RECT  0.06 2.952 2.408 3.024 ;
     RECT  0.084 3.024 2.408 3.048 ;
     RECT  0.06 3.048 2.408 3.12 ;
     RECT  0.084 3.12 2.408 3.144 ;
     RECT  0.06 3.144 2.408 3.216 ;
     RECT  0.084 3.216 2.408 3.24 ;
     RECT  0.06 3.24 2.408 3.312 ;
     RECT  0.084 3.312 2.408 3.336 ;
     RECT  0.06 3.336 2.408 3.408 ;
     RECT  0.084 3.408 2.408 3.432 ;
     RECT  0.06 3.432 2.408 3.504 ;
     RECT  0.084 3.504 2.408 3.528 ;
     RECT  0.06 3.528 2.408 3.6 ;
     RECT  0.084 3.6 2.408 3.624 ;
     RECT  0.06 3.624 2.408 3.696 ;
     RECT  0.084 3.696 2.408 3.72 ;
     RECT  0.06 3.72 2.408 3.792 ;
     RECT  0.084 3.792 2.408 3.816 ;
     RECT  0.06 3.816 2.408 3.888 ;
     RECT  0.084 3.888 2.408 3.912 ;
     RECT  0.06 3.912 2.408 3.984 ;
     RECT  0.084 3.984 2.408 4.008 ;
     RECT  0.06 4.008 2.408 4.08 ;
     RECT  0.084 4.08 2.408 4.104 ;
     RECT  0.06 4.104 2.408 4.176 ;
     RECT  0.084 4.176 2.408 4.2 ;
     RECT  0.06 4.2 2.408 4.272 ;
     RECT  0.084 4.272 2.408 4.296 ;
     RECT  0.06 4.296 2.408 4.368 ;
     RECT  0.084 4.368 2.408 4.392 ;
     RECT  0.06 4.392 2.408 4.464 ;
     RECT  0.084 4.464 2.408 4.488 ;
     RECT  0.06 4.488 2.408 4.56 ;
     RECT  0.084 4.56 2.408 4.584 ;
     RECT  0.06 4.584 2.408 4.656 ;
     RECT  0.084 4.656 2.408 4.68 ;
     RECT  0.06 4.68 2.408 4.752 ;
     RECT  0.084 4.752 2.408 4.776 ;
     RECT  0.06 4.776 2.408 4.848 ;
     RECT  0.084 4.848 2.408 4.872 ;
     RECT  0.06 4.872 2.408 4.944 ;
     RECT  0.084 4.944 2.408 4.968 ;
     RECT  0.06 4.968 2.408 5.04 ;
     RECT  0.084 5.04 2.408 5.064 ;
     RECT  0.06 5.064 2.408 5.136 ;
     RECT  0.084 5.136 2.408 5.16 ;
     RECT  0.06 5.16 2.408 5.232 ;
     RECT  0.084 5.232 2.408 5.256 ;
     RECT  0.06 5.256 2.408 5.328 ;
     RECT  0.084 5.328 2.408 5.352 ;
     RECT  0.06 5.352 2.408 5.424 ;
     RECT  0.084 5.424 2.408 5.448 ;
     RECT  0.06 5.448 2.408 5.52 ;
     RECT  0.084 5.52 2.408 5.544 ;
     RECT  0.06 5.544 2.408 5.616 ;
     RECT  0.084 5.616 2.408 5.64 ;
     RECT  0.06 5.64 2.408 5.712 ;
     RECT  0.084 5.712 2.408 5.736 ;
     RECT  0.06 5.736 2.408 5.808 ;
     RECT  0.084 5.808 2.408 5.832 ;
     RECT  0.06 5.832 2.408 5.904 ;
     RECT  0.084 5.904 2.408 5.928 ;
     RECT  0.06 5.928 2.408 6 ;
     RECT  0.084 6 2.408 6.024 ;
     RECT  0.06 6.024 2.408 6.096 ;
     RECT  0.084 6.096 2.408 6.12 ;
     RECT  0.06 6.12 2.408 6.192 ;
     RECT  0.084 6.192 2.408 6.216 ;
     RECT  0.06 6.216 2.408 6.288 ;
     RECT  0.084 6.288 2.408 6.312 ;
     RECT  0.06 6.312 2.408 6.384 ;
     RECT  0.084 6.384 2.408 6.408 ;
     RECT  0.06 6.408 2.408 6.48 ;
     RECT  0.084 6.48 2.408 6.504 ;
     RECT  0.06 6.504 2.408 6.576 ;
     RECT  0.084 6.576 2.408 6.6 ;
     RECT  0.06 6.6 2.408 6.672 ;
     RECT  0.084 6.672 2.408 6.696 ;
     RECT  0.06 6.696 2.408 6.768 ;
     RECT  0.084 6.768 2.408 6.792 ;
     RECT  0.06 6.792 2.408 6.864 ;
     RECT  0.084 6.864 2.408 6.888 ;
     RECT  0.06 6.888 2.408 6.96 ;
     RECT  0.084 6.96 2.408 6.984 ;
     RECT  0.06 6.984 2.408 7.056 ;
     RECT  0.084 7.056 2.408 7.08 ;
     RECT  0.06 7.08 2.408 7.152 ;
     RECT  0.084 7.152 2.408 7.176 ;
     RECT  0.06 7.176 2.408 7.248 ;
     RECT  0.084 7.248 2.408 7.272 ;
     RECT  0.06 7.272 2.408 7.344 ;
     RECT  0.084 7.344 2.408 7.368 ;
     RECT  0.06 7.368 2.408 7.44 ;
     RECT  0.084 7.44 2.408 7.464 ;
     RECT  0.06 7.464 2.408 7.536 ;
     RECT  0.084 7.536 2.408 7.56 ;
     RECT  0.06 7.56 2.408 7.632 ;
     RECT  0.084 7.632 2.408 7.656 ;
     RECT  0.06 7.656 2.408 7.728 ;
     RECT  0.084 7.728 2.408 7.752 ;
     RECT  0.06 7.752 2.408 7.824 ;
     RECT  0.084 7.824 2.408 7.848 ;
     RECT  0.06 7.848 2.408 7.92 ;
     RECT  0.084 7.92 2.408 7.944 ;
     RECT  0.06 7.944 2.408 8.016 ;
     RECT  0.084 8.016 2.408 8.04 ;
     RECT  0.06 8.04 2.408 8.112 ;
     RECT  0.084 8.112 2.408 8.136 ;
     RECT  0.06 8.136 2.408 8.208 ;
     RECT  0.084 8.208 2.408 8.232 ;
     RECT  0.06 8.232 2.408 8.304 ;
     RECT  0.084 8.304 2.408 8.328 ;
     RECT  0.06 8.328 2.408 8.4 ;
     RECT  0.084 8.4 2.408 8.424 ;
     RECT  0.06 8.424 2.408 8.496 ;
     RECT  0.084 8.496 2.408 8.52 ;
     RECT  0.06 8.52 2.408 8.592 ;
     RECT  0.084 8.592 2.408 8.616 ;
     RECT  0.06 8.616 2.408 8.688 ;
     RECT  0.084 8.688 2.408 8.712 ;
     RECT  0.06 8.712 2.408 8.784 ;
     RECT  0.084 8.784 2.408 8.808 ;
     RECT  0.06 8.808 2.408 8.88 ;
     RECT  0.084 8.88 2.408 8.904 ;
     RECT  0.06 8.904 2.408 8.976 ;
     RECT  0.084 8.976 2.408 9 ;
     RECT  0.06 9 2.408 9.072 ;
     RECT  0.084 9.072 2.408 9.096 ;
     RECT  0.06 9.096 2.408 9.168 ;
     RECT  0.084 9.168 2.408 9.192 ;
     RECT  0.06 9.192 2.408 9.264 ;
     RECT  0.084 9.264 2.408 9.288 ;
     RECT  0.06 9.288 2.408 9.36 ;
     RECT  0.084 9.36 2.408 9.384 ;
     RECT  0.06 9.384 2.408 9.456 ;
     RECT  0.084 9.456 2.408 9.48 ;
     RECT  0.06 9.48 2.408 9.552 ;
     RECT  0.084 9.552 2.408 9.576 ;
     RECT  0.06 9.576 2.408 9.648 ;
     RECT  0.084 9.648 2.408 9.672 ;
     RECT  0.06 9.672 2.408 9.744 ;
     RECT  0.084 9.744 2.408 9.768 ;
     RECT  0.06 9.768 2.408 9.84 ;
     RECT  0.084 9.84 2.408 9.864 ;
     RECT  0.06 9.864 2.408 9.936 ;
     RECT  0.084 9.936 2.408 9.96 ;
     RECT  0.06 9.96 2.408 10.032 ;
     RECT  0.084 10.032 2.408 10.056 ;
     RECT  0.06 10.056 2.408 10.128 ;
     RECT  0.084 10.128 2.408 10.152 ;
     RECT  0.06 10.152 2.408 10.224 ;
     RECT  0.084 10.224 2.408 10.248 ;
     RECT  0.06 10.248 2.408 10.32 ;
     RECT  0.084 10.32 2.408 10.344 ;
     RECT  0.06 10.344 2.408 10.416 ;
     RECT  0.084 10.416 2.408 10.44 ;
     RECT  0.06 10.44 2.408 10.512 ;
     RECT  0.084 10.512 2.408 10.536 ;
     RECT  0.06 10.536 2.408 10.608 ;
     RECT  0.084 10.608 2.408 10.632 ;
     RECT  0.06 10.632 2.408 10.704 ;
     RECT  0.084 10.704 2.408 10.728 ;
     RECT  0.06 10.728 2.408 10.8 ;
     RECT  0.084 10.8 2.408 10.824 ;
     RECT  0.06 10.824 2.408 10.896 ;
     RECT  0.084 10.896 2.408 10.92 ;
     RECT  0.06 10.92 2.408 10.992 ;
     RECT  0.084 10.992 2.408 11.016 ;
     RECT  0.06 11.016 2.408 11.088 ;
     RECT  0.084 11.088 2.408 11.112 ;
     RECT  0.06 11.112 2.408 11.184 ;
     RECT  0.084 11.184 2.408 11.208 ;
     RECT  0.06 11.208 2.408 11.28 ;
     RECT  0.084 11.28 2.408 11.304 ;
     RECT  0.06 11.304 2.408 11.376 ;
     RECT  0.084 11.376 2.408 11.4 ;
     RECT  0.06 11.4 2.408 11.472 ;
     RECT  0.084 11.472 2.408 11.496 ;
     RECT  0.06 11.496 2.408 11.568 ;
     RECT  0.084 11.568 2.408 11.592 ;
     RECT  0.06 11.592 2.408 11.664 ;
     RECT  0.084 11.664 2.408 11.688 ;
     RECT  0.06 11.688 2.408 11.76 ;
     RECT  0.084 11.76 2.408 11.784 ;
     RECT  0.06 11.784 2.408 11.856 ;
     RECT  0.084 11.856 2.408 11.88 ;
     RECT  0.06 11.88 2.408 11.952 ;
     RECT  0.084 11.952 2.408 11.976 ;
     RECT  0.06 11.976 2.408 12.048 ;
     RECT  0.084 12.048 2.408 12.072 ;
     RECT  0.06 12.072 2.408 12.144 ;
     RECT  0.084 12.144 2.408 12.168 ;
     RECT  0.06 12.168 2.408 12.24 ;
     RECT  0.084 12.24 2.408 12.264 ;
     RECT  0.06 12.264 2.408 12.336 ;
     RECT  0.084 12.336 2.408 12.36 ;
     RECT  0.06 12.36 2.408 12.432 ;
     RECT  0.084 12.432 2.408 12.456 ;
     RECT  0.06 12.456 2.408 12.528 ;
     RECT  0.084 12.528 2.408 12.552 ;
     RECT  0.06 12.552 2.408 12.624 ;
     RECT  0.084 12.624 2.408 12.648 ;
     RECT  0.06 12.648 2.408 12.72 ;
     RECT  0.084 12.72 2.408 12.744 ;
     RECT  0.06 12.744 2.408 12.816 ;
     RECT  0.084 12.816 2.408 12.84 ;
     RECT  0.06 12.84 2.408 12.912 ;
     RECT  0.084 12.912 2.408 12.936 ;
     RECT  0.06 12.936 2.408 13.008 ;
     RECT  0.084 13.008 2.408 13.032 ;
     RECT  0.06 13.032 2.408 13.104 ;
     RECT  0.084 13.104 2.408 13.128 ;
     RECT  0.06 13.128 2.408 13.2 ;
     RECT  0.084 13.2 2.408 13.224 ;
     RECT  0.06 13.224 2.408 13.296 ;
     RECT  0.084 13.296 2.408 13.32 ;
     RECT  0.06 13.32 2.408 13.392 ;
     RECT  0.084 13.392 2.408 13.416 ;
     RECT  0.06 13.416 2.408 13.488 ;
     RECT  0.084 13.488 2.408 13.512 ;
     RECT  0.06 13.512 2.408 13.584 ;
     RECT  0.084 13.584 2.408 13.608 ;
     RECT  0.06 13.608 2.408 13.68 ;
     RECT  0.084 13.68 2.408 13.704 ;
     RECT  0.06 13.704 2.408 13.776 ;
     RECT  0.084 13.776 2.408 13.8 ;
     RECT  0.06 13.8 2.408 13.872 ;
     RECT  0.084 13.872 2.408 13.896 ;
     RECT  0.06 13.896 2.408 13.968 ;
     RECT  0.084 13.968 2.408 13.992 ;
     RECT  0.06 13.992 2.408 14.064 ;
     RECT  0.084 14.064 2.408 14.088 ;
     RECT  0.06 14.088 2.408 14.16 ;
     RECT  0.084 14.16 2.408 14.184 ;
     RECT  0.06 14.184 2.408 14.256 ;
     RECT  0.084 14.256 2.408 14.28 ;
     RECT  0.06 14.28 2.408 14.352 ;
     RECT  0.084 14.352 2.408 14.376 ;
     RECT  0.06 14.376 2.408 14.448 ;
     RECT  0.084 14.448 2.408 14.472 ;
     RECT  0.06 14.472 2.408 14.544 ;
     RECT  0.084 14.544 2.408 14.568 ;
     RECT  0.06 14.568 2.408 14.64 ;
     RECT  0.084 14.64 2.408 14.664 ;
     RECT  0.06 14.664 2.408 14.736 ;
     RECT  0.084 14.736 2.408 14.76 ;
     RECT  0.06 14.76 2.408 14.832 ;
     RECT  0.084 14.832 2.408 14.856 ;
     RECT  0.06 14.856 2.408 14.928 ;
     RECT  0.084 14.928 2.408 14.952 ;
     RECT  0.06 14.952 2.408 15.024 ;
     RECT  0.084 15.024 2.408 15.048 ;
     RECT  0.06 15.048 2.408 15.12 ;
     RECT  0.084 15.12 2.408 15.144 ;
     RECT  0.06 15.144 2.408 15.216 ;
     RECT  0.084 15.216 2.408 15.24 ;
     RECT  0.06 15.24 2.408 15.312 ;
     RECT  0.084 15.312 2.408 15.336 ;
     RECT  0.06 15.336 2.408 15.408 ;
     RECT  0.084 15.408 2.408 15.432 ;
     RECT  0.06 15.432 2.408 15.504 ;
     RECT  0.084 15.504 2.408 15.528 ;
     RECT  0.06 15.528 2.408 15.6 ;
     RECT  0.084 15.6 2.408 15.624 ;
     RECT  0.06 15.624 2.408 15.696 ;
     RECT  0.084 15.696 2.408 15.72 ;
     RECT  0.06 15.72 2.408 15.792 ;
     RECT  0.084 15.792 2.408 15.816 ;
     RECT  0.06 15.816 2.408 15.888 ;
     RECT  0.084 15.888 2.408 15.912 ;
     RECT  0.06 15.912 2.408 15.984 ;
     RECT  0.084 15.984 2.408 16.008 ;
     RECT  0.06 16.008 2.408 16.08 ;
     RECT  0.084 16.08 2.408 16.104 ;
     RECT  0.06 16.104 2.408 16.176 ;
     RECT  0.084 16.176 2.408 16.2 ;
     RECT  0.06 16.2 2.408 16.272 ;
     RECT  0.084 16.272 2.408 16.296 ;
     RECT  0.06 16.296 2.408 16.368 ;
     RECT  0.084 16.368 2.408 16.392 ;
     RECT  0.06 16.392 2.408 16.464 ;
     RECT  0.084 16.464 2.408 16.488 ;
     RECT  0.06 16.488 2.408 16.56 ;
     RECT  0.084 16.56 2.408 16.584 ;
     RECT  0.06 16.584 2.408 16.656 ;
     RECT  0.084 16.656 2.408 16.68 ;
     RECT  0.06 16.68 2.408 16.752 ;
     RECT  0.084 16.752 2.408 16.776 ;
     RECT  0.06 16.776 2.408 16.848 ;
     RECT  0.084 16.848 2.408 16.872 ;
     RECT  0.06 16.872 2.408 16.944 ;
     RECT  0.084 16.944 2.408 16.968 ;
     RECT  0.06 16.968 2.408 17.04 ;
     RECT  0.084 17.04 2.408 17.064 ;
     RECT  0.06 17.064 2.408 17.136 ;
     RECT  0.084 17.136 2.408 17.16 ;
     RECT  0.06 17.16 2.408 17.232 ;
     RECT  0.084 17.232 2.408 17.256 ;
     RECT  0.06 17.256 2.408 17.328 ;
     RECT  0.084 17.328 2.408 17.352 ;
     RECT  0.06 17.352 2.408 17.424 ;
     RECT  0.084 17.424 2.408 17.448 ;
     RECT  0.06 17.448 2.408 17.52 ;
     RECT  0.084 17.52 2.408 17.544 ;
     RECT  0.06 17.544 2.408 17.616 ;
     RECT  0.084 17.616 2.408 17.64 ;
     RECT  0.06 17.64 2.408 17.712 ;
     RECT  0.084 17.712 2.408 17.736 ;
     RECT  0.06 17.736 2.408 17.808 ;
     RECT  0.084 17.808 2.408 17.832 ;
     RECT  0.06 17.832 2.408 17.904 ;
     RECT  0.084 17.904 2.408 17.928 ;
     RECT  0.06 17.928 2.408 18 ;
     RECT  0.084 18 2.408 18.024 ;
     RECT  0.06 18.024 2.408 18.096 ;
     RECT  0.084 18.096 2.408 18.12 ;
     RECT  0.06 18.12 2.408 18.192 ;
     RECT  0.084 18.192 2.408 18.216 ;
     RECT  0.06 18.216 2.408 18.288 ;
     RECT  0.084 18.288 2.408 18.312 ;
     RECT  0.06 18.312 2.408 18.384 ;
     RECT  0.084 18.384 2.408 18.408 ;
     RECT  0.06 18.408 2.408 18.48 ;
     RECT  0.084 18.48 2.408 18.504 ;
     RECT  0.06 18.504 2.408 18.576 ;
     RECT  0.084 18.576 2.408 18.6 ;
     RECT  0.06 18.6 2.408 18.672 ;
     RECT  0.084 18.672 2.408 18.696 ;
     RECT  0.06 18.696 2.408 18.768 ;
     RECT  0.084 18.768 2.408 18.792 ;
     RECT  0.06 18.792 2.408 18.864 ;
     RECT  0.084 18.864 2.408 18.888 ;
     RECT  0.06 18.888 2.408 18.96 ;
     RECT  0.084 18.96 2.408 18.984 ;
     RECT  0.06 18.984 2.408 19.056 ;
     RECT  0.084 19.056 2.408 19.08 ;
     RECT  0.06 19.08 2.408 19.152 ;
     RECT  0.084 19.152 2.408 19.176 ;
     RECT  0.06 19.176 2.408 19.248 ;
     RECT  0.084 19.248 2.408 19.272 ;
     RECT  0.06 19.272 2.408 19.344 ;
     RECT  0.084 19.344 2.408 19.368 ;
     RECT  0.06 19.368 2.408 19.44 ;
     RECT  0.084 19.44 2.408 19.464 ;
     RECT  0.06 19.464 2.408 19.536 ;
     RECT  0.084 19.536 2.408 19.56 ;
     RECT  0.06 19.56 2.408 19.632 ;
     RECT  0.084 19.632 2.408 19.656 ;
     RECT  0.06 19.656 2.408 19.728 ;
     RECT  0.084 19.728 2.408 19.752 ;
     RECT  0.06 19.752 2.408 19.824 ;
     RECT  0.084 19.824 2.408 19.848 ;
     RECT  0.06 19.848 2.408 19.92 ;
     RECT  0.084 19.92 2.408 19.944 ;
     RECT  0.06 19.944 2.408 20.016 ;
     RECT  0.084 20.016 2.408 20.04 ;
     RECT  0.06 20.04 2.408 20.112 ;
     RECT  0.084 20.112 2.408 20.136 ;
     RECT  0.06 20.136 2.408 20.208 ;
     RECT  0.084 20.208 2.408 20.232 ;
     RECT  0.06 20.232 2.408 20.304 ;
     RECT  0.084 20.304 2.408 20.328 ;
     RECT  0.06 20.328 2.408 20.4 ;
     RECT  0.084 20.4 2.408 20.424 ;
     RECT  0.06 20.424 2.408 20.496 ;
     RECT  0.084 20.496 2.408 20.52 ;
     RECT  0.06 20.52 2.408 20.592 ;
     RECT  0.084 20.592 2.408 20.616 ;
     RECT  0.06 20.616 2.408 20.688 ;
     RECT  0.084 20.688 2.408 20.712 ;
     RECT  0.06 20.712 2.408 20.784 ;
     RECT  0.084 20.784 2.408 20.808 ;
     RECT  0.06 20.808 2.408 20.88 ;
     RECT  0.084 20.88 2.408 20.904 ;
     RECT  0.06 20.904 2.408 20.976 ;
     RECT  0.084 20.976 2.408 21 ;
     RECT  0.06 21 2.408 21.072 ;
     RECT  0.084 21.072 2.408 21.096 ;
     RECT  0.06 21.096 2.408 21.168 ;
     RECT  0.084 21.168 2.408 21.192 ;
     RECT  0.06 21.192 2.408 21.264 ;
     RECT  0.084 21.264 2.408 21.288 ;
     RECT  0.06 21.288 2.408 22.128 ;
     RECT  0.084 22.128 2.408 22.152 ;
     RECT  0.06 22.152 2.408 22.224 ;
     RECT  0.084 22.224 2.408 22.248 ;
     RECT  0.06 22.248 2.408 22.32 ;
     RECT  0.084 22.32 2.408 22.344 ;
     RECT  0.06 22.344 2.408 22.416 ;
     RECT  0.084 22.416 2.408 22.44 ;
     RECT  0.06 22.44 2.408 22.512 ;
     RECT  0.084 22.512 2.408 22.536 ;
     RECT  0.06 22.536 2.408 22.608 ;
     RECT  0.084 22.608 2.408 22.632 ;
     RECT  0.06 22.632 2.408 22.704 ;
     RECT  0.084 22.704 2.408 22.728 ;
     RECT  0.06 22.728 2.408 22.8 ;
     RECT  0.084 22.8 2.408 22.824 ;
     RECT  0.06 22.824 2.408 22.896 ;
     RECT  0.084 22.896 2.408 22.92 ;
     RECT  0.06 22.92 2.408 22.992 ;
     RECT  0.084 22.992 2.408 23.016 ;
     RECT  0.06 23.016 2.408 23.088 ;
     RECT  0.084 23.088 2.408 23.112 ;
     RECT  0.06 23.112 2.408 23.184 ;
     RECT  0.084 23.184 2.408 23.208 ;
     RECT  0.06 23.208 2.408 23.28 ;
     RECT  0.084 23.28 2.408 23.304 ;
     RECT  0.06 23.304 2.408 23.376 ;
     RECT  0.084 23.376 2.408 23.4 ;
     RECT  0.06 23.4 2.408 23.472 ;
     RECT  0.084 23.472 2.408 23.496 ;
     RECT  0.06 23.496 2.408 23.568 ;
     RECT  0.084 23.568 2.408 23.592 ;
     RECT  0.06 23.592 2.408 23.664 ;
     RECT  0.084 23.664 2.408 23.688 ;
     RECT  0.06 23.688 2.408 23.76 ;
     RECT  0.084 23.76 2.408 23.784 ;
     RECT  0.06 23.784 2.408 23.856 ;
     RECT  0.084 23.856 2.408 23.88 ;
     RECT  0.06 23.88 2.408 23.952 ;
     RECT  0.084 23.952 2.408 23.976 ;
     RECT  0.06 23.976 2.408 24.048 ;
     RECT  0.084 24.048 2.408 24.072 ;
     RECT  0.06 24.072 2.408 24.144 ;
     RECT  0.084 24.144 2.408 24.168 ;
     RECT  0.06 24.168 2.408 24.24 ;
     RECT  0.084 24.24 2.408 24.264 ;
     RECT  0.06 24.264 2.408 24.336 ;
     RECT  0.084 24.336 2.408 24.36 ;
     RECT  0.06 24.36 2.408 24.432 ;
     RECT  0.084 24.432 2.408 24.456 ;
     RECT  0.06 24.456 2.408 24.528 ;
     RECT  0.084 24.528 2.408 24.552 ;
     RECT  0.06 24.552 2.408 24.624 ;
     RECT  0.084 24.624 2.408 24.648 ;
     RECT  0.06 24.648 2.408 24.72 ;
     RECT  0.084 24.72 2.408 24.744 ;
     RECT  0.06 24.744 2.408 24.816 ;
     RECT  0.084 24.816 2.408 24.84 ;
     RECT  0.06 24.84 2.408 24.912 ;
     RECT  0.084 24.912 2.408 24.936 ;
     RECT  0.06 24.936 2.408 25.008 ;
     RECT  0.084 25.008 2.408 25.032 ;
     RECT  0.06 25.032 2.408 25.104 ;
     RECT  0.084 25.104 2.408 25.128 ;
     RECT  0.06 25.128 2.408 25.2 ;
     RECT  0.084 25.2 2.408 25.224 ;
     RECT  0.06 25.224 2.408 25.296 ;
     RECT  0.084 25.296 2.408 25.32 ;
     RECT  0.06 25.32 2.408 25.392 ;
     RECT  0.084 25.392 2.408 25.416 ;
     RECT  0.06 25.416 2.408 25.488 ;
     RECT  0.084 25.488 2.408 25.512 ;
     RECT  0.06 25.512 2.408 25.584 ;
     RECT  0.084 25.584 2.408 25.608 ;
     RECT  0.06 25.608 2.408 25.68 ;
     RECT  0.084 25.68 2.408 25.704 ;
     RECT  0.06 25.704 2.408 25.776 ;
     RECT  0.084 25.776 2.408 25.8 ;
     RECT  0.06 25.8 2.408 25.872 ;
     RECT  0.084 25.872 2.408 25.896 ;
     RECT  0.06 25.896 2.408 25.968 ;
     RECT  0.084 25.968 2.408 25.992 ;
     RECT  0.06 25.992 2.408 26.064 ;
     RECT  0.084 26.064 2.408 26.088 ;
     RECT  0.06 26.088 2.408 26.16 ;
     RECT  0.084 26.16 2.408 26.184 ;
     RECT  0.06 26.184 2.408 26.256 ;
     RECT  0.084 26.256 2.408 26.28 ;
     RECT  0.06 26.28 2.408 26.352 ;
     RECT  0.084 26.352 2.408 26.376 ;
     RECT  0.06 26.376 2.408 26.448 ;
     RECT  0.084 26.448 2.408 26.472 ;
     RECT  0.06 26.472 2.408 26.544 ;
     RECT  0.084 26.544 2.408 26.568 ;
     RECT  0.06 26.568 2.408 26.64 ;
     RECT  0.084 26.64 2.408 26.664 ;
     RECT  0.06 26.664 2.408 26.736 ;
     RECT  0.084 26.736 2.408 26.76 ;
     RECT  0.06 26.76 2.408 26.832 ;
     RECT  0.084 26.832 2.408 26.856 ;
     RECT  0.06 26.856 2.408 26.928 ;
     RECT  0.084 26.928 2.408 26.952 ;
     RECT  0.06 26.952 2.408 27.024 ;
     RECT  0.084 27.024 2.408 27.048 ;
     RECT  0.06 27.048 2.408 27.12 ;
     RECT  0.084 27.12 2.408 27.144 ;
     RECT  0.06 27.144 2.408 27.216 ;
     RECT  0.084 27.216 2.408 27.24 ;
     RECT  0.06 27.24 2.408 27.312 ;
     RECT  0.084 27.312 2.408 27.336 ;
     RECT  0.06 27.336 2.408 27.408 ;
     RECT  0.084 27.408 2.408 27.432 ;
     RECT  0.06 27.432 2.408 27.504 ;
     RECT  0.084 27.504 2.408 27.528 ;
     RECT  0.06 27.528 2.408 27.6 ;
     RECT  0.084 27.6 2.408 27.624 ;
     RECT  0.06 27.624 2.408 27.696 ;
     RECT  0.084 27.696 2.408 27.72 ;
     RECT  0.06 27.72 2.408 27.792 ;
     RECT  0.084 27.792 2.408 27.816 ;
     RECT  0.06 27.816 2.408 27.888 ;
     RECT  0.084 27.888 2.408 27.912 ;
     RECT  0.06 27.912 2.408 27.984 ;
     RECT  0.084 27.984 2.408 28.008 ;
     RECT  0.06 28.008 2.408 28.08 ;
     RECT  0.084 28.08 2.408 28.104 ;
     RECT  0.06 28.104 2.408 28.176 ;
     RECT  0.084 28.176 2.408 28.2 ;
     RECT  0.06 28.2 2.408 28.272 ;
     RECT  0.084 28.272 2.408 28.296 ;
     RECT  0.06 28.296 2.408 28.368 ;
     RECT  0.084 28.368 2.408 28.392 ;
     RECT  0.06 28.392 2.408 28.464 ;
     RECT  0.084 28.464 2.408 28.488 ;
     RECT  0.06 28.488 2.408 28.56 ;
     RECT  0.084 28.56 2.408 28.584 ;
     RECT  0.06 28.584 2.408 28.656 ;
     RECT  0.084 28.656 2.408 28.68 ;
     RECT  0.06 28.68 2.408 28.752 ;
     RECT  0.084 28.752 2.408 28.776 ;
     RECT  0.06 28.776 2.408 28.848 ;
     RECT  0.084 28.848 2.408 28.872 ;
     RECT  0.06 28.872 2.408 28.944 ;
     RECT  0.084 28.944 2.408 28.968 ;
     RECT  0.06 28.968 2.408 29.04 ;
     RECT  0.084 29.04 2.408 29.064 ;
     RECT  0.06 29.064 2.408 29.136 ;
     RECT  0.084 29.136 2.408 29.16 ;
     RECT  0.06 29.16 2.408 29.232 ;
     RECT  0.084 29.232 2.408 29.256 ;
     RECT  0.06 29.256 2.408 29.328 ;
     RECT  0.084 29.328 2.408 29.352 ;
     RECT  0.06 29.352 2.408 29.424 ;
     RECT  0.084 29.424 2.408 29.448 ;
     RECT  0.06 29.448 2.408 29.52 ;
     RECT  0.084 29.52 2.408 29.544 ;
     RECT  0.06 29.544 2.408 29.616 ;
     RECT  0.084 29.616 2.408 29.64 ;
     RECT  0.06 29.64 2.408 29.712 ;
     RECT  0.084 29.712 2.408 29.736 ;
     RECT  0.06 29.736 2.408 29.808 ;
     RECT  0.084 29.808 2.408 29.832 ;
     RECT  0.06 29.832 2.408 29.904 ;
     RECT  0.084 29.904 2.408 29.928 ;
     RECT  0.06 29.928 2.408 30 ;
     RECT  0.084 30 2.408 30.024 ;
     RECT  0.06 30.024 2.408 30.096 ;
     RECT  0.084 30.096 2.408 30.12 ;
     RECT  0.06 30.12 2.408 30.192 ;
     RECT  0.084 30.192 2.408 30.216 ;
     RECT  0.06 30.216 2.408 30.288 ;
     RECT  0.084 30.288 2.408 30.312 ;
     RECT  0.06 30.312 2.408 30.384 ;
     RECT  0.084 30.384 2.408 30.408 ;
     RECT  0.06 30.408 2.408 30.48 ;
     RECT  0.084 30.48 2.408 30.504 ;
     RECT  0.06 30.504 2.408 30.576 ;
     RECT  0.084 30.576 2.408 30.6 ;
     RECT  0.06 30.6 2.408 30.672 ;
     RECT  0.084 30.672 2.408 30.696 ;
     RECT  0.06 30.696 2.408 30.768 ;
     RECT  0.084 30.768 2.408 30.792 ;
     RECT  0.06 30.792 2.408 30.864 ;
     RECT  0.084 30.864 2.408 30.888 ;
     RECT  0.06 30.888 2.408 30.96 ;
     RECT  0.084 30.96 2.408 30.984 ;
     RECT  0.06 30.984 2.408 31.056 ;
     RECT  0.084 31.056 2.408 31.08 ;
     RECT  0.06 31.08 2.408 31.152 ;
     RECT  0.084 31.152 2.408 31.176 ;
     RECT  0.06 31.176 2.408 31.248 ;
     RECT  0.084 31.248 2.408 31.272 ;
     RECT  0.06 31.272 2.408 31.344 ;
     RECT  0.084 31.344 2.408 31.368 ;
     RECT  0.06 31.368 2.408 31.44 ;
     RECT  0.084 31.44 2.408 31.464 ;
     RECT  0.06 31.464 2.408 31.536 ;
     RECT  0.084 31.536 2.408 31.56 ;
     RECT  0.06 31.56 2.408 31.632 ;
     RECT  0.084 31.632 2.408 31.656 ;
     RECT  0.06 31.656 2.408 31.728 ;
     RECT  0.084 31.728 2.408 31.752 ;
     RECT  0.06 31.752 2.408 31.824 ;
     RECT  0.084 31.824 2.408 31.848 ;
     RECT  0.06 31.848 2.408 31.92 ;
     RECT  0.084 31.92 2.408 31.944 ;
     RECT  0.06 31.944 2.408 32.016 ;
     RECT  0.084 32.016 2.408 32.04 ;
     RECT  0.06 32.04 2.408 32.112 ;
     RECT  0.084 32.112 2.408 32.136 ;
     RECT  0.06 32.136 2.408 32.208 ;
     RECT  0.084 32.208 2.408 32.232 ;
     RECT  0.06 32.232 2.408 32.304 ;
     RECT  0.084 32.304 2.408 32.328 ;
     RECT  0.06 32.328 2.408 32.4 ;
     RECT  0.084 32.4 2.408 32.424 ;
     RECT  0.06 32.424 2.408 32.496 ;
     RECT  0.084 32.496 2.408 32.52 ;
     RECT  0.06 32.52 2.408 32.592 ;
     RECT  0.084 32.592 2.408 32.616 ;
     RECT  0.06 32.616 2.408 32.688 ;
     RECT  0.084 32.688 2.408 32.712 ;
     RECT  0.06 32.712 2.408 32.784 ;
     RECT  0.084 32.784 2.408 32.808 ;
     RECT  0.06 32.808 2.408 32.88 ;
     RECT  0.084 32.88 2.408 32.904 ;
     RECT  0.06 32.904 2.408 32.976 ;
     RECT  0.084 32.976 2.408 33 ;
     RECT  0.06 33 2.408 33.072 ;
     RECT  0.084 33.072 2.408 33.096 ;
     RECT  0.06 33.096 2.408 33.168 ;
     RECT  0.084 33.168 2.408 33.192 ;
     RECT  0.06 33.192 2.408 33.264 ;
     RECT  0.084 33.264 2.408 33.288 ;
     RECT  0.06 33.288 2.408 33.36 ;
     RECT  0.084 33.36 2.408 33.384 ;
     RECT  0.06 33.384 2.408 33.456 ;
     RECT  0.084 33.456 2.408 33.48 ;
     RECT  0.06 33.48 2.408 33.552 ;
     RECT  0.084 33.552 2.408 33.576 ;
     RECT  0.06 33.576 2.408 33.648 ;
     RECT  0.084 33.648 2.408 33.672 ;
     RECT  0.06 33.672 2.408 33.744 ;
     RECT  0.084 33.744 2.408 33.768 ;
     RECT  0.06 33.768 2.408 33.84 ;
     RECT  0.084 33.84 2.408 33.864 ;
     RECT  0.06 33.864 2.408 33.936 ;
     RECT  0.084 33.936 2.408 33.96 ;
     RECT  0.06 33.96 2.408 34.032 ;
     RECT  0.084 34.032 2.408 34.056 ;
     RECT  0.06 34.056 2.408 34.128 ;
     RECT  0.084 34.128 2.408 34.152 ;
     RECT  0.06 34.152 2.408 34.224 ;
     RECT  0.084 34.224 2.408 34.248 ;
     RECT  0.06 34.248 2.408 34.32 ;
     RECT  0.084 34.32 2.408 34.344 ;
     RECT  0.06 34.344 2.408 34.416 ;
     RECT  0.084 34.416 2.408 34.44 ;
     RECT  0.06 34.44 2.408 34.512 ;
     RECT  0.084 34.512 2.408 34.536 ;
     RECT  0.06 34.536 2.408 34.608 ;
     RECT  0.084 34.608 2.408 34.632 ;
     RECT  0.06 34.632 2.408 34.704 ;
     RECT  0.084 34.704 2.408 34.728 ;
     RECT  0.06 34.728 2.408 34.8 ;
     RECT  0.084 34.8 2.408 34.824 ;
     RECT  0.06 34.824 2.408 34.896 ;
     RECT  0.084 34.896 2.408 34.92 ;
     RECT  0.06 34.92 2.408 34.992 ;
     RECT  0.084 34.992 2.408 35.016 ;
     RECT  0.06 35.016 2.408 35.088 ;
     RECT  0.084 35.088 2.408 35.112 ;
     RECT  0.06 35.112 2.408 35.184 ;
     RECT  0.084 35.184 2.408 35.208 ;
     RECT  0.06 35.208 2.408 35.28 ;
     RECT  0.084 35.28 2.408 35.304 ;
     RECT  0.06 35.304 2.408 35.376 ;
     RECT  0.084 35.376 2.408 35.4 ;
     RECT  0.06 35.4 2.408 35.472 ;
     RECT  0.084 35.472 2.408 35.496 ;
     RECT  0.06 35.496 2.408 35.568 ;
     RECT  0.084 35.568 2.408 35.592 ;
     RECT  0.06 35.592 2.408 35.664 ;
     RECT  0.084 35.664 2.408 35.688 ;
     RECT  0.06 35.688 2.408 35.76 ;
     RECT  0.084 35.76 2.408 35.784 ;
     RECT  0.06 35.784 2.408 35.856 ;
     RECT  0.084 35.856 2.408 35.88 ;
     RECT  0.06 35.88 2.408 35.952 ;
     RECT  0.084 35.952 2.408 35.976 ;
     RECT  0.06 35.976 2.408 36.048 ;
     RECT  0.084 36.048 2.408 36.072 ;
     RECT  0.06 36.072 2.408 36.144 ;
     RECT  0.084 36.144 2.408 36.168 ;
     RECT  0.06 36.168 2.408 36.24 ;
     RECT  0.084 36.24 2.408 36.264 ;
     RECT  0.06 36.264 2.408 36.336 ;
     RECT  0.084 36.336 2.408 36.36 ;
     RECT  0.06 36.36 2.408 36.432 ;
     RECT  0.084 36.432 2.408 36.456 ;
     RECT  0.06 36.456 2.408 36.528 ;
     RECT  0.084 36.528 2.408 36.552 ;
     RECT  0.06 36.552 2.408 36.624 ;
     RECT  0.084 36.624 2.408 36.648 ;
     RECT  0.06 36.648 2.408 36.72 ;
     RECT  0.084 36.72 2.408 36.744 ;
     RECT  0.06 36.744 2.408 36.816 ;
     RECT  0.084 36.816 2.408 36.84 ;
     RECT  0.06 36.84 2.408 36.912 ;
     RECT  0.084 36.912 2.408 36.936 ;
     RECT  0.06 36.936 2.408 37.008 ;
     RECT  0.084 37.008 2.408 37.032 ;
     RECT  0.06 37.032 2.408 37.104 ;
     RECT  0.084 37.104 2.408 37.128 ;
     RECT  0.06 37.128 2.408 37.2 ;
     RECT  0.084 37.2 2.408 37.224 ;
     RECT  0.06 37.224 2.408 37.296 ;
     RECT  0.084 37.296 2.408 37.32 ;
     RECT  0.06 37.32 2.408 37.392 ;
     RECT  0.084 37.392 2.408 37.416 ;
     RECT  0.06 37.416 2.408 37.488 ;
     RECT  0.084 37.488 2.408 37.512 ;
     RECT  0.06 37.512 2.408 37.584 ;
     RECT  0.084 37.584 2.408 37.608 ;
     RECT  0.06 37.608 2.408 37.68 ;
     RECT  0.084 37.68 2.408 37.704 ;
     RECT  0.06 37.704 2.408 37.776 ;
     RECT  0.084 37.776 2.408 37.8 ;
     RECT  0.06 37.8 2.408 37.872 ;
     RECT  0.084 37.872 2.408 37.896 ;
     RECT  0.06 37.896 2.408 37.968 ;
     RECT  0.084 37.968 2.408 37.992 ;
     RECT  0.06 37.992 2.408 38.064 ;
     RECT  0.084 38.064 2.408 38.088 ;
     RECT  0.06 38.088 2.408 38.16 ;
     RECT  0.084 38.16 2.408 38.184 ;
     RECT  0.06 38.184 2.408 38.256 ;
     RECT  0.084 38.256 2.408 38.28 ;
     RECT  0.06 38.28 2.408 38.352 ;
     RECT  0.084 38.352 2.408 38.376 ;
     RECT  0.06 38.376 2.408 38.448 ;
     RECT  0.084 38.448 2.408 38.472 ;
     RECT  0.06 38.472 2.408 38.544 ;
     RECT  0.084 38.544 2.408 38.568 ;
     RECT  0.06 38.568 2.408 38.64 ;
     RECT  0.084 38.64 2.408 38.664 ;
     RECT  0.06 38.664 2.408 38.736 ;
     RECT  0.084 38.736 2.408 38.76 ;
     RECT  0.06 38.76 2.408 38.832 ;
     RECT  0.084 38.832 2.408 38.856 ;
     RECT  0.06 38.856 2.408 38.928 ;
     RECT  0.084 38.928 2.408 38.952 ;
     RECT  0.06 38.952 2.408 39.024 ;
     RECT  0.084 39.024 2.408 39.048 ;
     RECT  0.06 39.048 2.408 39.12 ;
     RECT  0.084 39.12 2.408 39.144 ;
     RECT  0.06 39.144 2.408 39.216 ;
     RECT  0.084 39.216 2.408 39.24 ;
     RECT  0.06 39.24 2.408 39.312 ;
     RECT  0.084 39.312 2.408 39.336 ;
     RECT  0.06 39.336 2.408 39.408 ;
     RECT  0.084 39.408 2.408 39.432 ;
     RECT  0.06 39.432 2.408 39.504 ;
     RECT  0.084 39.504 2.408 39.528 ;
     RECT  0.06 39.528 2.408 39.6 ;
     RECT  0.084 39.6 2.408 39.624 ;
     RECT  0.06 39.624 2.408 39.696 ;
     RECT  0.084 39.696 2.408 39.72 ;
     RECT  0.06 39.72 2.408 39.792 ;
     RECT  0.084 39.792 2.408 39.816 ;
     RECT  0.06 39.816 2.408 39.888 ;
     RECT  0.084 39.888 2.408 39.912 ;
     RECT  0.06 39.912 2.408 39.984 ;
     RECT  0.084 39.984 2.408 40.008 ;
     RECT  0.06 40.008 2.408 40.08 ;
     RECT  0.084 40.08 2.408 40.104 ;
     RECT  0.06 40.104 2.408 40.176 ;
     RECT  0.084 40.176 2.408 40.2 ;
     RECT  0.06 40.2 2.408 40.272 ;
     RECT  0.084 40.272 2.408 40.296 ;
     RECT  0.06 40.296 2.408 40.368 ;
     RECT  0.084 40.368 2.408 40.392 ;
     RECT  0.06 40.392 2.408 40.464 ;
     RECT  0.084 40.464 2.408 40.488 ;
     RECT  0.06 40.488 2.408 41.328 ;
     RECT  0.084 41.328 2.408 41.352 ;
     RECT  0.06 41.352 2.408 41.424 ;
     RECT  0.084 41.424 2.408 41.448 ;
     RECT  0.06 41.448 2.408 41.52 ;
     RECT  0.084 41.52 2.408 41.544 ;
     RECT  0.06 41.544 2.408 41.616 ;
     RECT  0.084 41.616 2.408 41.64 ;
     RECT  0.06 41.64 2.408 41.712 ;
     RECT  0.084 41.712 2.408 41.736 ;
     RECT  0.06 41.736 2.408 41.808 ;
     RECT  0.084 41.808 2.408 41.832 ;
     RECT  0.06 41.832 2.408 41.904 ;
     RECT  0.084 41.904 2.408 41.928 ;
     RECT  0.06 41.928 2.408 42 ;
     RECT  0.084 42 2.408 42.024 ;
     RECT  0.06 42.024 2.408 42.096 ;
     RECT  0.084 42.096 2.408 42.12 ;
     RECT  0.06 42.12 2.408 42.192 ;
     RECT  0.084 42.192 2.408 42.216 ;
     RECT  0.06 42.216 2.408 42.288 ;
     RECT  0.084 42.288 2.408 42.312 ;
     RECT  0.06 42.312 2.408 42.384 ;
     RECT  0.084 42.384 2.408 42.408 ;
     RECT  0.06 42.408 2.408 42.48 ;
     RECT  0.084 42.48 2.408 42.504 ;
     RECT  0.06 42.504 2.408 42.576 ;
     RECT  0.084 42.576 2.408 42.6 ;
     RECT  0.06 42.6 2.408 42.672 ;
     RECT  0.084 42.672 2.408 42.696 ;
     RECT  0.06 42.696 2.408 42.768 ;
     RECT  0.084 42.768 2.408 42.792 ;
     RECT  0.06 42.792 2.408 42.864 ;
     RECT  0.084 42.864 2.408 42.888 ;
     RECT  0.06 42.888 2.408 42.96 ;
     RECT  0.084 42.96 2.408 42.984 ;
     RECT  0.06 42.984 2.408 43.056 ;
     RECT  0.084 43.056 2.408 43.08 ;
     RECT  0.06 43.08 2.408 43.152 ;
     RECT  0.084 43.152 2.408 43.176 ;
     RECT  0.06 43.176 2.408 43.248 ;
     RECT  0.084 43.248 2.408 43.272 ;
     RECT  0.06 43.272 2.408 43.344 ;
     RECT  0.084 43.344 2.408 43.368 ;
     RECT  0.06 43.368 2.408 43.44 ;
     RECT  0.084 43.44 2.408 43.464 ;
     RECT  0.06 43.464 2.408 43.536 ;
     RECT  0.084 43.536 2.408 43.56 ;
     RECT  0.06 43.56 2.408 43.632 ;
     RECT  0.084 43.632 2.408 43.656 ;
     RECT  0.06 43.656 2.408 43.728 ;
     RECT  0.084 43.728 2.408 43.752 ;
     RECT  0.06 43.752 2.408 43.824 ;
     RECT  0.084 43.824 2.408 43.848 ;
     RECT  0.06 43.848 2.408 43.92 ;
     RECT  0.084 43.92 2.408 43.944 ;
     RECT  0.06 43.944 2.408 44.016 ;
     RECT  0.084 44.016 2.408 44.04 ;
     RECT  0.06 44.04 2.408 44.112 ;
     RECT  0.084 44.112 2.408 44.136 ;
     RECT  0.06 44.136 2.408 44.208 ;
     RECT  0.084 44.208 2.408 44.232 ;
     RECT  0.06 44.232 2.408 44.304 ;
     RECT  0.084 44.304 2.408 44.328 ;
     RECT  0.06 44.328 2.408 44.4 ;
     RECT  0.084 44.4 2.408 44.424 ;
     RECT  0.06 44.424 2.408 44.496 ;
     RECT  0.084 44.496 2.408 44.52 ;
     RECT  0.06 44.52 2.408 44.592 ;
     RECT  0.084 44.592 2.408 44.616 ;
     RECT  0.06 44.616 2.408 44.688 ;
     RECT  0.084 44.688 2.408 44.712 ;
     RECT  0.06 44.712 2.408 44.784 ;
     RECT  0.084 44.784 2.408 44.808 ;
     RECT  0.06 44.808 2.408 44.88 ;
     RECT  0.084 44.88 2.408 44.904 ;
     RECT  0.06 44.904 2.408 44.976 ;
     RECT  0.084 44.976 2.408 45 ;
     RECT  0.06 45 2.408 45.072 ;
     RECT  0.084 45.072 2.408 45.096 ;
     RECT  0.06 45.096 2.408 45.168 ;
     RECT  0.084 45.168 2.408 45.192 ;
     RECT  0.06 45.192 2.408 45.264 ;
     RECT  0.084 45.264 2.408 45.288 ;
     RECT  0.06 45.288 2.408 45.36 ;
     RECT  0.084 45.36 2.408 45.384 ;
     RECT  0.06 45.384 2.408 45.456 ;
     RECT  0.084 45.456 2.408 45.48 ;
     RECT  0.06 45.48 2.408 45.552 ;
     RECT  0.084 45.552 2.408 45.576 ;
     RECT  0.06 45.576 2.408 45.648 ;
     RECT  0.084 45.648 2.408 45.672 ;
     RECT  0.06 45.672 2.408 45.744 ;
     RECT  0.084 45.744 2.408 45.768 ;
     RECT  0.06 45.768 2.408 45.84 ;
     RECT  0.084 45.84 2.408 45.864 ;
     RECT  0.06 45.864 2.408 45.936 ;
     RECT  0.084 45.936 2.408 45.96 ;
     RECT  0.06 45.96 2.408 46.032 ;
     RECT  0.084 46.032 2.408 46.056 ;
     RECT  0.06 46.056 2.408 46.128 ;
     RECT  0.084 46.128 2.408 46.152 ;
     RECT  0.06 46.152 2.408 46.224 ;
     RECT  0.084 46.224 2.408 46.248 ;
     RECT  0.06 46.248 2.408 46.32 ;
     RECT  0.084 46.32 2.408 46.344 ;
     RECT  0.06 46.344 2.408 46.416 ;
     RECT  0.084 46.416 2.408 46.44 ;
     RECT  0.06 46.44 2.408 46.512 ;
     RECT  0.084 46.512 2.408 46.536 ;
     RECT  0.06 46.536 2.408 46.608 ;
     RECT  0.084 46.608 2.408 46.632 ;
     RECT  0.06 46.632 2.408 46.704 ;
     RECT  0.084 46.704 2.408 46.728 ;
     RECT  0.06 46.728 2.408 46.8 ;
     RECT  0.084 46.8 2.408 46.824 ;
     RECT  0.06 46.824 2.408 46.896 ;
     RECT  0.084 46.896 2.408 46.92 ;
     RECT  0.06 46.92 2.408 46.992 ;
     RECT  0.084 46.992 2.408 47.016 ;
     RECT  0.06 47.016 2.408 47.088 ;
     RECT  0.084 47.088 2.408 47.112 ;
     RECT  0.06 47.112 2.408 47.184 ;
     RECT  0.084 47.184 2.408 47.208 ;
     RECT  0.06 47.208 2.408 47.28 ;
     RECT  0.084 47.28 2.408 47.304 ;
     RECT  0.06 47.304 2.408 47.376 ;
     RECT  0.084 47.376 2.408 47.4 ;
     RECT  0.06 47.4 2.408 47.472 ;
     RECT  0.084 47.472 2.408 47.496 ;
     RECT  0.06 47.496 2.408 47.568 ;
     RECT  0.084 47.568 2.408 47.592 ;
     RECT  0.06 47.592 2.408 47.664 ;
     RECT  0.084 47.664 2.408 47.688 ;
     RECT  0.06 47.688 2.408 47.76 ;
     RECT  0.084 47.76 2.408 47.784 ;
     RECT  0.06 47.784 2.408 47.856 ;
     RECT  0.084 47.856 2.408 47.88 ;
     RECT  0.06 47.88 2.408 47.952 ;
     RECT  0.084 47.952 2.408 47.976 ;
     RECT  0.06 47.976 2.408 48.048 ;
     RECT  0.084 48.048 2.408 48.072 ;
     RECT  0.06 48.072 2.408 48.144 ;
     RECT  0.084 48.144 2.408 48.168 ;
     RECT  0.06 48.168 2.408 48.24 ;
     RECT  0.084 48.24 2.408 48.264 ;
     RECT  0.06 48.264 2.408 48.336 ;
     RECT  0.084 48.336 2.408 48.36 ;
     RECT  0.06 48.36 2.408 48.432 ;
     RECT  0.084 48.432 2.408 48.456 ;
     RECT  0.06 48.456 2.408 48.528 ;
     RECT  0.084 48.528 2.408 48.552 ;
     RECT  0.06 48.552 2.408 48.624 ;
     RECT  0.084 48.624 2.408 48.648 ;
     RECT  0.06 48.648 2.408 48.72 ;
     RECT  0.084 48.72 2.408 48.744 ;
     RECT  0.06 48.744 2.408 48.816 ;
     RECT  0.084 48.816 2.408 48.84 ;
     RECT  0.06 48.84 2.408 48.912 ;
     RECT  0.084 48.912 2.408 48.936 ;
     RECT  0.06 48.936 2.408 49.008 ;
     RECT  0.084 49.008 2.408 49.032 ;
     RECT  0.06 49.032 2.408 49.104 ;
     RECT  0.084 49.104 2.408 49.128 ;
     RECT  0.06 49.128 2.408 49.2 ;
     RECT  0.084 49.2 2.408 49.224 ;
     RECT  0.06 49.224 2.408 49.296 ;
     RECT  0.084 49.296 2.408 49.32 ;
     RECT  0.06 49.32 2.408 49.392 ;
     RECT  0.084 49.392 2.408 49.416 ;
     RECT  0.06 49.416 2.408 49.488 ;
     RECT  0.084 49.488 2.408 49.512 ;
     RECT  0.06 49.512 2.408 49.584 ;
     RECT  0.084 49.584 2.408 49.608 ;
     RECT  0.06 49.608 2.408 49.68 ;
     RECT  0.084 49.68 2.408 49.704 ;
     RECT  0.06 49.704 2.408 49.776 ;
     RECT  0.084 49.776 2.408 49.8 ;
     RECT  0.06 49.8 2.408 49.872 ;
     RECT  0.084 49.872 2.408 49.896 ;
     RECT  0.06 49.896 2.408 49.968 ;
     RECT  0.084 49.968 2.408 49.992 ;
     RECT  0.06 49.992 2.408 50.064 ;
     RECT  0.084 50.064 2.408 50.088 ;
     RECT  0.06 50.088 2.408 50.16 ;
     RECT  0.084 50.16 2.408 50.184 ;
     RECT  0.06 50.184 2.408 50.256 ;
     RECT  0.084 50.256 2.408 50.28 ;
     RECT  0.06 50.28 2.408 50.352 ;
     RECT  0.084 50.352 2.408 50.376 ;
     RECT  0.06 50.376 2.408 50.448 ;
     RECT  0.084 50.448 2.408 50.472 ;
     RECT  0.06 50.472 2.408 50.544 ;
     RECT  0.084 50.544 2.408 50.568 ;
     RECT  0.06 50.568 2.408 50.64 ;
     RECT  0.084 50.64 2.408 50.664 ;
     RECT  0.06 50.664 2.408 50.736 ;
     RECT  0.084 50.736 2.408 50.76 ;
     RECT  0.06 50.76 2.408 50.832 ;
     RECT  0.084 50.832 2.408 50.856 ;
     RECT  0.06 50.856 2.408 50.928 ;
     RECT  0.084 50.928 2.408 50.952 ;
     RECT  0.06 50.952 2.408 51.024 ;
     RECT  0.084 51.024 2.408 51.048 ;
     RECT  0.06 51.048 2.408 51.12 ;
     RECT  0.084 51.12 2.408 51.144 ;
     RECT  0.06 51.144 2.408 51.216 ;
     RECT  0.084 51.216 2.408 51.24 ;
     RECT  0.06 51.24 2.408 51.312 ;
     RECT  0.084 51.312 2.408 51.336 ;
     RECT  0.06 51.336 2.408 51.408 ;
     RECT  0.084 51.408 2.408 51.432 ;
     RECT  0.06 51.432 2.408 51.504 ;
     RECT  0.084 51.504 2.408 51.528 ;
     RECT  0.06 51.528 2.408 51.6 ;
     RECT  0.084 51.6 2.408 51.624 ;
     RECT  0.06 51.624 2.408 51.696 ;
     RECT  0.084 51.696 2.408 51.72 ;
     RECT  0.06 51.72 2.408 51.792 ;
     RECT  0.084 51.792 2.408 51.816 ;
     RECT  0.06 51.816 2.408 51.888 ;
     RECT  0.084 51.888 2.408 51.912 ;
     RECT  0.06 51.912 2.408 51.984 ;
     RECT  0.084 51.984 2.408 52.008 ;
     RECT  0.06 52.008 2.408 52.08 ;
     RECT  0.084 52.08 2.408 52.104 ;
     RECT  0.06 52.104 2.408 52.176 ;
     RECT  0.084 52.176 2.408 52.2 ;
     RECT  0.06 52.2 2.408 52.272 ;
     RECT  0.084 52.272 2.408 52.296 ;
     RECT  0.06 52.296 2.408 52.368 ;
     RECT  0.084 52.368 2.408 52.392 ;
     RECT  0.06 52.392 2.408 52.464 ;
     RECT  0.084 52.464 2.408 52.488 ;
     RECT  0.06 52.488 2.408 52.56 ;
     RECT  0.084 52.56 2.408 52.584 ;
     RECT  0.06 52.584 2.408 52.656 ;
     RECT  0.084 52.656 2.408 52.68 ;
     RECT  0.06 52.68 2.408 52.752 ;
     RECT  0.084 52.752 2.408 52.776 ;
     RECT  0.06 52.776 2.408 52.848 ;
     RECT  0.084 52.848 2.408 52.872 ;
     RECT  0.06 52.872 2.408 52.944 ;
     RECT  0.084 52.944 2.408 52.968 ;
     RECT  0.06 52.968 2.408 53.04 ;
     RECT  0.084 53.04 2.408 53.064 ;
     RECT  0.06 53.064 2.408 53.136 ;
     RECT  0.084 53.136 2.408 53.16 ;
     RECT  0.06 53.16 2.408 53.232 ;
     RECT  0.084 53.232 2.408 53.256 ;
     RECT  0.06 53.256 2.408 53.328 ;
     RECT  0.084 53.328 2.408 53.352 ;
     RECT  0.06 53.352 2.408 53.424 ;
     RECT  0.084 53.424 2.408 53.448 ;
     RECT  0.06 53.448 2.408 53.52 ;
     RECT  0.084 53.52 2.408 53.544 ;
     RECT  0.084 55.536 2.408 55.56 ;
     RECT  0.06 55.56 2.408 55.632 ;
     RECT  0.084 55.632 2.408 55.656 ;
     RECT  0.06 55.656 2.408 55.728 ;
     RECT  0.084 55.728 2.408 55.752 ;
     RECT  0.06 55.752 2.408 55.824 ;
     RECT  0.084 55.824 2.408 55.848 ;
     RECT  0.06 55.848 2.408 55.92 ;
     RECT  0.084 55.92 2.408 55.944 ;
     RECT  0.06 55.944 2.408 56.016 ;
     RECT  0.084 56.016 2.408 56.04 ;
     RECT  0.06 56.04 2.408 56.112 ;
     RECT  0.084 56.112 2.408 56.136 ;
     RECT  0.06 56.136 2.408 56.208 ;
     RECT  0.084 56.208 2.408 56.232 ;
     RECT  0.06 56.232 2.408 56.304 ;
     RECT  0.084 56.304 2.408 56.328 ;
     RECT  0.06 56.328 2.408 56.4 ;
     RECT  0.084 56.4 2.408 56.424 ;
     RECT  0.06 56.424 2.408 56.496 ;
     RECT  0.084 56.496 2.408 56.52 ;
     RECT  0.06 56.52 2.408 56.592 ;
     RECT  0.084 56.592 2.408 56.616 ;
     RECT  2.408 2.148 2.512 58.332 ;
     RECT  2.512 2.418 2.704 58.062 ;
     RECT  2.704 2.496 2.819 53.928 ;
     RECT  2.704 55.008 2.981 56.328 ;
     RECT  2.819 4.656 3.923 53.928 ;
     RECT  2.981 55.008 4.021 55.848 ;
     RECT  3.923 52.464 4.057 53.928 ;
     RECT  4.021 55.008 4.057 56.52 ;
     RECT  2.819 2.496 4.129 3.672 ;
     RECT  3.923 4.656 4.129 51.336 ;
     RECT  4.129 2.496 4.357 51.336 ;
     RECT  4.357 2.064 4.957 51.336 ;
     RECT  4.057 52.464 4.957 56.52 ;
     RECT  4.957 2.064 5.108 51.432 ;
     RECT  4.957 52.464 5.108 56.568 ;
     RECT  5.108 2.064 5.212 58.332 ;
     RECT  5.212 2.064 5.404 58.062 ;
     RECT  5.404 2.064 5.555 55.32 ;
     RECT  5.404 56.496 5.573 56.808 ;
     RECT  5.573 56.496 5.789 56.568 ;
     RECT  5.555 2.064 5.825 54.936 ;
     RECT  5.825 2.208 6.725 54.936 ;
     RECT  6.725 2.208 6.803 3.912 ;
     RECT  5.789 56.496 6.865 56.52 ;
     RECT  6.725 5.088 7.189 54.936 ;
     RECT  6.803 2.208 7.808 3.672 ;
     RECT  7.189 5.088 7.808 55.32 ;
     RECT  6.865 56.448 7.808 56.52 ;
     RECT  7.808 2.148 7.912 58.332 ;
     RECT  7.912 2.418 8.104 58.062 ;
     RECT  8.104 6.096 8.165 53.544 ;
     RECT  8.104 54.624 8.309 54.888 ;
     RECT  8.165 7.872 8.381 53.544 ;
     RECT  8.381 8.976 8.417 53.544 ;
     RECT  8.417 9.504 8.579 53.544 ;
     RECT  8.104 3.36 8.771 3.672 ;
     RECT  8.579 51.936 8.771 53.544 ;
     RECT  8.771 51.936 8.813 53.304 ;
     RECT  8.381 7.872 8.957 7.992 ;
     RECT  8.579 9.504 9.029 50.952 ;
     RECT  9.029 9.504 9.251 50.76 ;
     RECT  8.165 6.096 9.299 6.84 ;
     RECT  9.251 10.128 9.539 50.76 ;
     RECT  8.309 54.864 9.709 54.888 ;
     RECT  8.813 51.936 9.961 52.056 ;
     RECT  8.813 53.28 9.961 53.304 ;
     RECT  9.541 2.304 10.357 2.328 ;
     RECT  8.771 3.36 10.357 3.384 ;
     RECT  9.299 6.096 10.357 6.12 ;
     RECT  10.357 2.304 10.508 3.384 ;
     RECT  10.357 5.184 10.508 6.12 ;
     RECT  8.957 7.92 10.508 7.992 ;
     RECT  9.539 10.128 10.508 48.984 ;
     RECT  9.539 50.016 10.508 50.76 ;
     RECT  9.961 51.936 10.508 53.304 ;
     RECT  9.709 54.336 10.508 54.888 ;
     RECT  10.508 2.148 10.612 58.332 ;
     RECT  10.612 2.418 10.804 58.062 ;
     RECT  10.804 51.936 10.979 52.008 ;
     RECT  10.804 45.792 11.027 46.536 ;
     RECT  10.804 47.712 11.123 48.504 ;
     RECT  11.123 47.712 11.219 48.264 ;
     RECT  10.804 40.32 11.261 44.664 ;
     RECT  10.804 11.952 11.267 17.16 ;
     RECT  11.267 11.952 11.363 15.48 ;
     RECT  10.804 18.24 11.363 39.336 ;
     RECT  11.363 11.952 11.411 14.472 ;
     RECT  11.363 18.24 11.411 39.24 ;
     RECT  11.411 18.24 11.549 39.144 ;
     RECT  11.261 40.32 11.549 44.472 ;
     RECT  11.411 11.952 11.555 13.608 ;
     RECT  11.549 38.16 11.585 39.144 ;
     RECT  10.804 5.184 11.621 5.208 ;
     RECT  10.804 50.016 11.621 50.76 ;
     RECT  11.267 16.56 11.651 17.16 ;
     RECT  11.555 12.864 11.699 13.608 ;
     RECT  10.979 51.936 11.747 51.96 ;
     RECT  10.804 7.92 11.795 7.944 ;
     RECT  11.549 40.656 11.837 44.472 ;
     RECT  11.027 45.984 11.837 46.536 ;
     RECT  11.549 18.24 11.873 37.08 ;
     RECT  11.837 45.984 11.909 46.2 ;
     RECT  11.873 18.24 11.939 34.776 ;
     RECT  10.804 53.28 11.941 53.304 ;
     RECT  11.873 36 11.945 37.08 ;
     RECT  11.945 36 11.981 36.264 ;
     RECT  11.699 12.864 11.987 12.888 ;
     RECT  11.939 18.24 11.987 32.328 ;
     RECT  11.651 16.56 12.017 16.872 ;
     RECT  11.621 50.016 12.049 50.328 ;
     RECT  11.987 18.24 12.053 30.408 ;
     RECT  11.837 41.04 12.053 44.472 ;
     RECT  12.053 18.24 12.083 29.064 ;
     RECT  12.049 49.248 12.083 50.328 ;
     RECT  11.939 33.6 12.089 34.776 ;
     RECT  12.089 34.08 12.125 34.776 ;
     RECT  11.981 36 12.125 36.072 ;
     RECT  11.363 15.456 12.131 15.48 ;
     RECT  12.053 41.52 12.131 43.56 ;
     RECT  11.909 46.176 12.161 46.2 ;
     RECT  12.083 23.856 12.179 29.064 ;
     RECT  12.131 42.72 12.227 43.56 ;
     RECT  11.219 47.712 12.697 47.736 ;
     RECT  12.083 49.248 12.733 50.136 ;
     RECT  12.697 47.664 12.757 47.736 ;
     RECT  12.733 49.056 12.757 50.136 ;
     RECT  11.585 39.12 12.769 39.144 ;
     RECT  12.757 47.664 12.805 50.136 ;
     RECT  12.517 51.456 12.841 51.72 ;
     RECT  12.841 51.456 12.877 51.768 ;
     RECT  10.804 54.336 12.985 54.888 ;
     RECT  11.941 53.04 13.021 53.304 ;
     RECT  12.985 54.336 13.021 55.464 ;
     RECT  12.877 51.168 13.045 51.768 ;
     RECT  13.021 53.04 13.045 55.464 ;
     RECT  13.045 51.168 13.057 55.464 ;
     RECT  12.083 18.24 13.093 22.632 ;
     RECT  12.053 30.384 13.093 30.408 ;
     RECT  12.125 36.048 13.093 36.072 ;
     RECT  12.805 57.024 13.165 57.048 ;
     RECT  12.769 39.12 13.201 39.816 ;
     RECT  12.017 16.56 13.208 16.584 ;
     RECT  13.093 18.24 13.208 22.824 ;
     RECT  12.179 23.856 13.208 24.456 ;
     RECT  12.179 25.44 13.208 29.064 ;
     RECT  13.093 30.384 13.208 30.6 ;
     RECT  11.987 31.728 13.208 32.328 ;
     RECT  12.125 34.08 13.208 34.104 ;
     RECT  13.093 36.048 13.208 36.552 ;
     RECT  13.201 38.16 13.208 39.816 ;
     RECT  12.131 41.52 13.208 41.688 ;
     RECT  12.227 42.72 13.208 42.84 ;
     RECT  12.805 47.472 13.208 50.136 ;
     RECT  13.057 51.168 13.208 55.752 ;
     RECT  13.165 56.88 13.208 57.048 ;
     RECT  13.208 2.148 13.312 58.332 ;
     RECT  13.312 2.418 13.504 58.062 ;
     RECT  13.504 35.856 13.715 36.552 ;
     RECT  13.504 28.272 13.745 29.064 ;
     RECT  13.715 35.856 13.745 36.36 ;
     RECT  13.504 30.048 13.859 34.104 ;
     RECT  13.504 51.168 13.961 57.384 ;
     RECT  14.101 59.184 14.129 59.208 ;
     RECT  13.504 16.56 14.195 17.016 ;
     RECT  13.504 18.048 14.195 23.352 ;
     RECT  14.129 59.184 14.209 59.256 ;
     RECT  14.195 16.56 14.291 16.584 ;
     RECT  13.504 24.336 14.291 27.096 ;
     RECT  14.291 24.336 14.332 24.936 ;
     RECT  13.859 30.048 14.393 33.624 ;
     RECT  14.195 18.24 14.428 23.352 ;
     RECT  14.209 59.184 14.437 59.832 ;
     RECT  14.291 26.208 14.465 27.096 ;
     RECT  13.504 39.168 14.531 42.744 ;
     RECT  13.504 37.584 14.569 38.184 ;
     RECT  14.531 39.168 14.569 42.312 ;
     RECT  14.437 58.656 14.597 59.832 ;
     RECT  13.504 44.4 14.641 50.136 ;
     RECT  13.961 51.168 14.641 57.096 ;
     RECT  13.745 28.272 14.897 28.488 ;
     RECT  14.641 44.4 14.965 57.096 ;
     RECT  14.597 58.608 14.969 59.832 ;
     RECT  14.965 43.44 15.109 57.096 ;
     RECT  14.393 33.024 15.205 33.624 ;
     RECT  15.073 34.848 15.205 34.872 ;
     RECT  14.428 18.24 15.253 23.256 ;
     RECT  15.253 17.616 15.389 23.256 ;
     RECT  14.393 31.68 15.389 31.944 ;
     RECT  15.205 33.024 15.389 34.872 ;
     RECT  14.393 30.048 15.397 30.648 ;
     RECT  15.389 31.68 15.397 34.872 ;
     RECT  13.745 36.336 15.397 36.36 ;
     RECT  15.397 30.048 15.405 36.36 ;
     RECT  15.389 17.616 15.425 23.928 ;
     RECT  14.332 24.912 15.425 24.936 ;
     RECT  14.465 26.688 15.433 27.096 ;
     RECT  15.405 29.568 15.433 36.36 ;
     RECT  14.897 28.464 15.452 28.488 ;
     RECT  15.433 29.568 15.452 36.6 ;
     RECT  14.969 58.608 15.473 59.256 ;
     RECT  15.109 43.44 15.493 57.576 ;
     RECT  15.473 58.608 15.493 58.68 ;
     RECT  14.569 37.584 15.649 42.312 ;
     RECT  15.493 43.44 15.649 58.68 ;
     RECT  15.452 28.464 15.793 36.6 ;
     RECT  15.649 37.584 15.793 58.68 ;
     RECT  15.425 17.616 15.908 24.936 ;
     RECT  15.433 26.208 15.908 27.096 ;
     RECT  15.793 28.464 15.908 58.68 ;
     RECT  15.908 2.148 16.012 58.68 ;
     RECT  16.012 2.418 16.204 58.68 ;
     RECT  16.204 18.432 16.229 22.824 ;
     RECT  16.204 29.04 16.355 31.944 ;
     RECT  16.355 31.92 16.445 31.944 ;
     RECT  16.261 60.288 16.451 60.312 ;
     RECT  16.204 34.368 16.481 35.256 ;
     RECT  16.229 19.536 16.589 22.824 ;
     RECT  16.204 37.104 16.733 38.76 ;
     RECT  16.733 37.104 16.883 37.992 ;
     RECT  16.883 37.2 16.985 37.992 ;
     RECT  16.204 48.864 16.985 58.68 ;
     RECT  16.985 37.296 17.057 37.992 ;
     RECT  16.355 29.04 17.129 30.84 ;
     RECT  16.204 44.448 17.129 46.344 ;
     RECT  16.481 34.704 17.197 35.256 ;
     RECT  16.589 19.536 17.201 22.776 ;
     RECT  16.985 48.96 17.201 58.68 ;
     RECT  17.129 30.24 17.425 30.84 ;
     RECT  16.204 40.08 17.489 43.368 ;
     RECT  16.204 24.912 17.521 25.752 ;
     RECT  16.204 27.072 17.521 27.096 ;
     RECT  17.201 48.96 17.561 58.632 ;
     RECT  17.197 34.704 17.737 35.448 ;
     RECT  17.561 48.96 17.741 58.344 ;
     RECT  17.737 34.56 17.845 35.448 ;
     RECT  17.749 23.664 17.953 23.688 ;
     RECT  17.521 24.912 17.953 27.096 ;
     RECT  17.845 33.936 17.989 35.448 ;
     RECT  17.489 42.768 17.989 43.368 ;
     RECT  17.989 42.768 18.097 43.656 ;
     RECT  17.129 45.072 18.097 46.344 ;
     RECT  17.989 33.936 18.313 35.928 ;
     RECT  17.057 37.968 18.421 37.992 ;
     RECT  18.421 37.968 18.469 39.336 ;
     RECT  17.489 40.464 18.469 41.688 ;
     RECT  18.097 42.768 18.469 46.344 ;
     RECT  17.341 47.376 18.469 47.4 ;
     RECT  18.469 40.32 18.493 47.4 ;
     RECT  16.229 18.432 18.608 18.456 ;
     RECT  17.201 19.536 18.608 22.344 ;
     RECT  17.953 23.664 18.608 27.096 ;
     RECT  17.129 29.04 18.608 29.064 ;
     RECT  17.425 30.816 18.608 30.84 ;
     RECT  17.413 31.872 18.608 31.896 ;
     RECT  18.313 33.024 18.608 35.928 ;
     RECT  18.469 37.104 18.608 39.336 ;
     RECT  18.493 40.32 18.608 47.928 ;
     RECT  17.741 48.96 18.608 58.332 ;
     RECT  18.608 2.148 18.712 58.332 ;
     RECT  18.712 2.418 18.904 58.062 ;
     RECT  18.904 34.368 18.965 34.392 ;
     RECT  18.904 42.72 19.001 43.656 ;
     RECT  18.904 22.08 19.037 22.776 ;
     RECT  18.904 35.616 19.043 35.88 ;
     RECT  18.904 41.616 19.043 41.64 ;
     RECT  19.001 42.768 19.109 42.792 ;
     RECT  18.904 40.08 19.289 40.632 ;
     RECT  18.904 28.944 19.505 28.968 ;
     RECT  18.904 48.912 19.541 57.432 ;
     RECT  18.904 45.792 19.757 46.536 ;
     RECT  18.904 27.456 19.897 27.48 ;
     RECT  19.037 22.752 19.916 22.776 ;
     RECT  18.904 24.432 19.916 24.792 ;
     RECT  18.904 30.528 19.933 30.552 ;
     RECT  19.043 35.856 19.957 35.88 ;
     RECT  18.904 37.104 19.957 37.992 ;
     RECT  19.933 30.528 19.969 30.696 ;
     RECT  19.289 40.08 19.973 40.104 ;
     RECT  19.541 48.912 19.973 54.36 ;
     RECT  19.916 22.752 20.003 24.792 ;
     RECT  19.957 35.856 20.003 37.992 ;
     RECT  19.757 45.792 20.009 46.2 ;
     RECT  20.009 46.032 20.099 46.2 ;
     RECT  19.541 55.392 20.113 57.432 ;
     RECT  19.969 30.528 20.149 30.792 ;
     RECT  20.149 30.24 20.153 30.792 ;
     RECT  20.113 34.56 20.221 34.584 ;
     RECT  20.221 33.648 20.293 34.584 ;
     RECT  20.185 28.752 20.333 28.776 ;
     RECT  20.003 22.752 20.341 23.4 ;
     RECT  20.003 24.672 20.365 24.792 ;
     RECT  18.904 26.208 20.365 26.232 ;
     RECT  20.149 32.064 20.401 32.088 ;
     RECT  20.113 55.392 20.473 58.104 ;
     RECT  20.293 33.6 20.545 34.584 ;
     RECT  18.904 18.432 20.629 21 ;
     RECT  20.545 33.552 20.797 34.584 ;
     RECT  20.003 36.432 20.869 37.992 ;
     RECT  18.904 44.736 20.941 44.76 ;
     RECT  20.869 36.432 20.972 38.808 ;
     RECT  20.341 22.752 20.977 22.872 ;
     RECT  20.401 32.016 21.049 32.088 ;
     RECT  20.099 46.176 21.061 46.2 ;
     RECT  20.077 59.28 21.305 59.304 ;
     RECT  20.629 18.432 21.308 21.24 ;
     RECT  20.977 22.56 21.308 22.872 ;
     RECT  20.365 24.672 21.308 26.232 ;
     RECT  19.897 27.312 21.308 27.48 ;
     RECT  20.153 30.24 21.308 30.744 ;
     RECT  21.049 31.968 21.308 32.088 ;
     RECT  20.797 33.552 21.308 35.304 ;
     RECT  20.972 36.432 21.308 39.72 ;
     RECT  20.588 42.144 21.308 42.168 ;
     RECT  20.629 43.344 21.308 43.368 ;
     RECT  20.941 44.448 21.308 44.76 ;
     RECT  21.061 45.792 21.308 46.2 ;
     RECT  19.973 49.536 21.308 54.216 ;
     RECT  20.473 55.392 21.308 58.152 ;
     RECT  21.308 2.148 21.412 58.332 ;
     RECT  21.412 2.418 21.604 58.152 ;
     RECT  21.604 18.432 21.665 18.456 ;
     RECT  21.604 20.88 21.665 21.24 ;
     RECT  21.604 38.784 21.665 39.48 ;
     RECT  21.604 27.36 21.701 32.04 ;
     RECT  21.604 48.72 21.731 58.152 ;
     RECT  21.604 33.6 21.737 36.936 ;
     RECT  21.665 20.928 21.773 21.192 ;
     RECT  21.604 19.488 21.809 19.8 ;
     RECT  21.604 43.968 21.953 46.248 ;
     RECT  21.604 42 22.097 42.216 ;
     RECT  21.604 40.944 22.133 40.968 ;
     RECT  21.953 45.84 22.205 46.248 ;
     RECT  21.731 48.72 22.205 58.056 ;
     RECT  21.701 27.36 22.421 31.704 ;
     RECT  21.737 34.224 22.421 36.936 ;
     RECT  21.773 21.072 22.429 21.192 ;
     RECT  22.421 28.416 22.529 31.704 ;
     RECT  22.421 36.192 22.565 36.936 ;
     RECT  21.809 19.488 22.745 19.56 ;
     RECT  21.604 22.416 22.777 25.56 ;
     RECT  22.777 22.368 22.885 25.56 ;
     RECT  22.885 21.744 22.921 25.56 ;
     RECT  21.665 39.456 22.925 39.48 ;
     RECT  22.205 48.96 23.065 58.056 ;
     RECT  22.097 42.192 23.137 42.216 ;
     RECT  22.529 30.816 23.245 31.704 ;
     RECT  23.137 42 23.245 42.216 ;
     RECT  23.065 48.96 23.461 58.152 ;
     RECT  21.953 43.968 23.533 44.76 ;
     RECT  23.245 42 23.677 42.504 ;
     RECT  23.533 43.632 23.677 44.76 ;
     RECT  23.461 48.768 23.713 58.152 ;
     RECT  22.421 27.36 23.821 27.384 ;
     RECT  22.745 19.488 23.893 19.512 ;
     RECT  22.921 21.744 23.965 26.232 ;
     RECT  22.565 36.912 23.965 36.936 ;
     RECT  23.893 19.488 24.008 19.608 ;
     RECT  23.965 21.696 24.008 26.232 ;
     RECT  23.821 27.36 24.008 27.432 ;
     RECT  22.529 28.416 24.008 29.064 ;
     RECT  23.245 30.816 24.008 31.752 ;
     RECT  22.421 34.224 24.008 34.92 ;
     RECT  23.965 36 24.008 36.936 ;
     RECT  23.389 40.848 24.008 40.968 ;
     RECT  23.677 42 24.008 44.76 ;
     RECT  22.205 46.224 24.008 46.248 ;
     RECT  23.713 48.384 24.008 58.152 ;
     RECT  24.008 2.148 24.112 58.332 ;
     RECT  24.112 2.418 24.304 58.2 ;
     RECT  24.304 19.584 24.419 19.608 ;
     RECT  24.304 21.696 24.419 25.752 ;
     RECT  24.304 47.856 24.509 58.2 ;
     RECT  24.304 27.36 24.515 27.576 ;
     RECT  24.419 21.744 24.545 25.752 ;
     RECT  24.304 31.44 24.545 31.8 ;
     RECT  24.515 27.36 24.553 27.432 ;
     RECT  24.304 28.992 24.617 29.4 ;
     RECT  24.304 34.32 24.617 35.88 ;
     RECT  24.509 47.856 24.617 58.152 ;
     RECT  24.545 21.984 24.653 25.752 ;
     RECT  24.553 27.36 24.797 27.384 ;
     RECT  24.617 34.896 25.013 35.88 ;
     RECT  24.545 31.68 25.049 31.8 ;
     RECT  24.304 44.88 25.057 45 ;
     RECT  24.304 38.976 25.085 39.48 ;
     RECT  24.617 47.856 25.085 57.96 ;
     RECT  25.013 34.896 25.121 34.92 ;
     RECT  25.085 56.88 25.157 57.96 ;
     RECT  24.617 29.328 25.265 29.4 ;
     RECT  24.304 42.816 25.265 43.896 ;
     RECT  24.304 40.848 25.301 41.64 ;
     RECT  25.085 47.856 25.333 55.896 ;
     RECT  25.265 29.328 25.337 29.352 ;
     RECT  25.085 38.976 25.337 39 ;
     RECT  25.333 47.808 25.361 55.896 ;
     RECT  25.049 31.728 25.513 31.8 ;
     RECT  25.513 31.728 25.553 32.28 ;
     RECT  24.304 46.128 25.573 46.152 ;
     RECT  25.361 47.328 25.573 55.896 ;
     RECT  25.301 40.944 25.661 41.64 ;
     RECT  25.265 42.816 25.697 43.656 ;
     RECT  24.653 24.624 25.724 25.752 ;
     RECT  25.724 23.904 25.765 25.752 ;
     RECT  24.653 21.984 26.089 22.92 ;
     RECT  25.765 23.904 26.089 26.28 ;
     RECT  25.573 46.128 26.197 55.896 ;
     RECT  25.157 56.928 26.197 57.96 ;
     RECT  25.661 41.472 26.233 41.64 ;
     RECT  26.233 60.384 26.444 60.408 ;
     RECT  25.057 44.88 26.449 44.904 ;
     RECT  26.197 46.128 26.449 57.96 ;
     RECT  26.444 60.336 26.531 60.408 ;
     RECT  26.449 44.88 26.533 57.96 ;
     RECT  25.724 28.176 26.581 28.2 ;
     RECT  26.233 41.472 26.581 41.688 ;
     RECT  25.697 42.816 26.581 43.368 ;
     RECT  26.089 21.984 26.708 26.28 ;
     RECT  26.581 28.176 26.708 28.92 ;
     RECT  25.553 31.776 26.708 32.28 ;
     RECT  26.581 34.8 26.708 34.824 ;
     RECT  26.521 35.904 26.708 35.928 ;
     RECT  24.304 36.912 26.708 36.936 ;
     RECT  26.197 39.504 26.708 39.528 ;
     RECT  26.581 41.472 26.708 43.368 ;
     RECT  26.533 44.88 26.708 58.728 ;
     RECT  26.708 2.148 26.812 58.728 ;
     RECT  26.812 2.418 26.921 58.728 ;
     RECT  26.921 2.418 27.004 58.68 ;
     RECT  27.004 49.776 27.065 50.424 ;
     RECT  27.065 50.112 27.101 50.424 ;
     RECT  27.004 41.664 27.155 41.688 ;
     RECT  26.531 60.384 27.203 60.408 ;
     RECT  27.004 38.736 27.245 39.528 ;
     RECT  27.004 51.744 27.251 58.68 ;
     RECT  27.251 51.744 27.281 55.416 ;
     RECT  27.004 48.432 27.289 48.456 ;
     RECT  27.281 53.28 27.299 55.416 ;
     RECT  27.251 56.4 27.299 58.68 ;
     RECT  27.299 56.736 27.325 58.68 ;
     RECT  27.004 36.048 27.389 37.128 ;
     RECT  27.245 38.736 27.389 38.76 ;
     RECT  27.101 50.112 27.389 50.136 ;
     RECT  27.299 54.096 27.395 55.272 ;
     RECT  27.325 57.024 27.443 58.68 ;
     RECT  27.004 44.88 27.461 45.048 ;
     RECT  27.395 54.096 27.491 55.08 ;
     RECT  27.004 32.256 27.497 32.28 ;
     RECT  27.461 45.024 27.533 45.048 ;
     RECT  27.491 54.096 27.533 54.84 ;
     RECT  27.389 36.048 27.539 36.456 ;
     RECT  27.443 57.024 27.577 58.152 ;
     RECT  27.539 36.048 27.605 36.072 ;
     RECT  27.577 57.936 27.605 58.152 ;
     RECT  27.281 51.744 27.821 52.2 ;
     RECT  27.605 57.936 27.821 57.96 ;
     RECT  27.533 54.384 27.829 54.84 ;
     RECT  27.829 54.384 27.868 54.408 ;
     RECT  27.821 51.936 27.893 52.2 ;
     RECT  27.893 52.176 28.001 52.2 ;
     RECT  27.004 22.32 28.825 22.632 ;
     RECT  28.825 22.32 29.005 22.824 ;
     RECT  29.005 21.936 29.041 22.92 ;
     RECT  29.041 21.84 29.077 22.92 ;
     RECT  29.077 21.648 29.617 23.016 ;
     RECT  29.617 21.648 30.121 23.112 ;
     RECT  30.121 21.552 30.156 21.576 ;
     RECT  30.121 21.576 30.204 21.648 ;
     RECT  30.121 21.648 30.156 21.672 ;
     RECT  30.121 21.672 30.204 21.744 ;
     RECT  30.121 21.744 30.156 21.768 ;
     RECT  30.121 21.768 30.204 21.84 ;
     RECT  30.121 21.84 30.156 21.864 ;
     RECT  30.121 21.864 30.204 21.936 ;
     RECT  30.121 21.936 30.156 21.96 ;
     RECT  30.121 21.96 30.204 22.032 ;
     RECT  30.121 22.032 30.156 22.056 ;
     RECT  30.121 22.056 30.204 22.128 ;
     RECT  30.121 22.128 30.156 22.152 ;
     RECT  30.121 22.152 30.204 22.224 ;
     RECT  30.121 22.224 30.156 22.248 ;
     RECT  30.121 22.248 30.204 22.32 ;
     RECT  30.121 22.32 30.156 22.344 ;
     RECT  30.121 22.344 30.204 22.416 ;
     RECT  30.121 22.416 30.156 22.44 ;
     RECT  30.121 22.44 30.204 22.512 ;
     RECT  30.121 22.512 30.156 22.536 ;
     RECT  30.121 22.536 30.204 22.608 ;
     RECT  30.121 22.608 30.156 22.632 ;
     RECT  30.121 22.632 30.204 22.704 ;
     RECT  30.121 22.704 30.156 22.728 ;
     RECT  30.121 22.728 30.204 22.8 ;
     RECT  30.121 22.8 30.156 22.824 ;
     RECT  30.121 22.824 30.204 22.896 ;
     RECT  30.121 22.896 30.156 22.92 ;
     RECT  30.121 22.92 30.204 22.992 ;
     RECT  30.121 22.992 30.156 23.016 ;
     RECT  30.121 23.016 30.204 23.088 ;
     RECT  30.121 23.088 30.156 23.112 ;
    LAYER M5 ;
     RECT  4.368 2.053 4.392 2.137 ;
     RECT  2.4 2.137 2.52 2.151 ;
     RECT  4.368 2.137 5.22 2.151 ;
     RECT  7.8 2.137 7.92 2.151 ;
     RECT  9.552 2.137 10.62 2.151 ;
     RECT  13.2 2.137 13.32 2.151 ;
     RECT  15.9 2.137 16.02 2.151 ;
     RECT  18.6 2.137 18.72 2.151 ;
     RECT  21.3 2.137 21.42 2.151 ;
     RECT  24 2.137 24.12 2.151 ;
     RECT  26.7 2.137 26.82 2.151 ;
     RECT  4.368 2.151 5.412 2.197 ;
     RECT  7.8 2.151 8.112 2.197 ;
     RECT  9.552 2.151 10.812 2.339 ;
     RECT  2.4 2.151 2.712 2.485 ;
     RECT  4.368 2.197 5.736 2.485 ;
     RECT  7.632 2.197 8.112 2.725 ;
     RECT  2.4 2.485 5.736 3.205 ;
     RECT  2.4 3.205 5.88 3.301 ;
     RECT  10.368 2.339 10.812 3.349 ;
     RECT  7.056 2.725 8.112 3.637 ;
     RECT  2.4 3.301 6.024 3.733 ;
     RECT  7.056 3.637 8.76 3.733 ;
     RECT  0.144 4.645 0.168 5.123 ;
     RECT  10.272 3.349 10.812 6.085 ;
     RECT  2.4 3.733 8.76 6.757 ;
     RECT  2.4 6.757 8.808 6.805 ;
     RECT  10.176 6.085 10.812 6.805 ;
     RECT  2.4 6.805 10.812 7.909 ;
     RECT  0.192 8.677 0.216 9.061 ;
     RECT  0.144 9.061 0.216 9.827 ;
     RECT  0.144 9.827 0.168 10.981 ;
     RECT  0.144 10.981 0.216 11.989 ;
     RECT  0.144 11.989 0.36 12.469 ;
     RECT  0.144 12.469 0.456 12.659 ;
     RECT  2.4 7.909 11.784 12.853 ;
     RECT  0.144 12.659 0.216 13.669 ;
     RECT  0.144 13.669 0.312 14.917 ;
     RECT  2.4 12.853 11.976 15.445 ;
     RECT  0.144 14.917 0.408 15.875 ;
     RECT  13.2 2.151 13.512 16.549 ;
     RECT  0.288 15.875 0.408 16.837 ;
     RECT  0.144 16.837 0.408 17.123 ;
     RECT  0.288 17.123 0.408 17.219 ;
     RECT  15.9 2.151 16.212 17.605 ;
     RECT  0.288 17.219 0.312 18.133 ;
     RECT  0.144 18.133 0.312 18.181 ;
     RECT  2.4 15.445 12.12 18.181 ;
     RECT  0.144 18.181 0.552 18.515 ;
     RECT  2.208 18.181 12.12 18.661 ;
     RECT  13.2 16.549 14.28 18.661 ;
     RECT  2.208 18.661 14.28 18.709 ;
     RECT  18.6 2.151 18.912 18.757 ;
     RECT  21.3 2.151 21.612 18.757 ;
     RECT  2.208 18.709 14.52 19.285 ;
     RECT  2.208 19.285 14.712 19.333 ;
     RECT  15.696 17.605 16.212 19.333 ;
     RECT  2.208 19.333 16.212 19.475 ;
     RECT  24 2.151 24.312 19.477 ;
     RECT  23.904 19.477 24.312 19.573 ;
     RECT  23.904 19.573 24.408 19.619 ;
     RECT  15.696 19.475 16.212 20.051 ;
     RECT  0.24 18.515 0.552 20.101 ;
     RECT  18.6 18.757 19.032 20.293 ;
     RECT  0.192 20.101 0.552 20.389 ;
     RECT  18.24 20.293 19.032 20.389 ;
     RECT  18.096 20.389 19.032 20.723 ;
     RECT  0.192 20.389 0.6 20.773 ;
     RECT  20.64 18.757 21.612 21.061 ;
     RECT  2.208 19.475 14.712 21.203 ;
     RECT  0.192 20.773 0.696 21.251 ;
     RECT  20.64 21.061 22.392 21.251 ;
     RECT  18.096 20.723 18.912 21.541 ;
     RECT  2.304 21.203 14.712 21.635 ;
     RECT  24 19.619 24.408 21.731 ;
     RECT  0.192 21.251 0.648 21.779 ;
     RECT  14.496 21.635 14.712 22.067 ;
     RECT  21.3 21.251 22.392 22.451 ;
     RECT  14.688 22.067 14.712 22.501 ;
     RECT  15.9 20.051 16.212 22.501 ;
     RECT  2.304 21.635 13.512 23.317 ;
     RECT  14.688 22.501 16.212 23.317 ;
     RECT  20.304 22.741 20.328 23.411 ;
     RECT  0.192 21.779 0.552 23.507 ;
     RECT  26.7 2.151 27.012 23.893 ;
     RECT  0.192 23.507 0.504 24.323 ;
     RECT  19.968 23.701 19.992 24.757 ;
     RECT  21.3 22.451 21.612 24.757 ;
     RECT  19.968 24.757 21.612 24.803 ;
     RECT  17.76 21.541 18.912 24.901 ;
     RECT  0.192 24.323 0.312 25.187 ;
     RECT  22.848 25.045 22.872 25.525 ;
     RECT  24 21.731 24.312 25.525 ;
     RECT  22.848 25.525 24.312 25.571 ;
     RECT  20.496 24.803 21.612 25.715 ;
     RECT  0.192 25.187 0.216 26.149 ;
     RECT  23.328 25.571 24.312 26.243 ;
     RECT  17.376 24.901 18.912 27.107 ;
     RECT  24 26.243 24.312 27.397 ;
     RECT  24 27.397 24.504 27.587 ;
     RECT  21.3 25.715 21.612 27.877 ;
     RECT  25.776 23.893 27.012 28.211 ;
     RECT  26.592 28.211 27.012 28.931 ;
     RECT  0.192 26.149 0.408 28.981 ;
     RECT  2.304 23.317 16.212 29.029 ;
     RECT  18.6 27.107 18.912 29.029 ;
     RECT  0.192 28.981 0.504 29.461 ;
     RECT  2.304 29.029 16.344 29.461 ;
     RECT  17.376 27.107 17.4 29.461 ;
     RECT  0.192 29.461 1.176 29.509 ;
     RECT  0.192 29.509 1.272 29.651 ;
     RECT  2.304 29.461 17.4 30.275 ;
     RECT  21.3 27.877 22.392 30.275 ;
     RECT  0.192 29.651 0.504 30.661 ;
     RECT  0.144 30.661 0.504 30.949 ;
     RECT  0.144 30.949 1.176 31.091 ;
     RECT  2.304 30.275 16.68 31.427 ;
     RECT  0.144 31.091 0.312 32.099 ;
     RECT  2.4 31.427 16.68 33.013 ;
     RECT  0.288 32.099 0.312 33.683 ;
     RECT  24 27.587 24.312 34.309 ;
     RECT  18.432 29.029 18.912 34.693 ;
     RECT  26.7 28.931 27.012 34.789 ;
     RECT  2.304 33.013 16.68 34.835 ;
     RECT  21.3 30.275 21.612 34.885 ;
     RECT  21.3 34.885 21.912 34.981 ;
     RECT  21.024 34.981 21.912 35.027 ;
     RECT  18 34.693 18.912 35.075 ;
     RECT  0.144 35.029 0.168 35.219 ;
     RECT  0.24 35.221 0.264 35.507 ;
     RECT  18.192 35.075 18.912 35.605 ;
     RECT  18.192 35.605 19.032 35.845 ;
     RECT  24 34.309 24.504 35.891 ;
     RECT  18.192 35.845 19.992 35.939 ;
     RECT  26.592 34.789 27.012 35.939 ;
     RECT  26.7 35.939 27.012 36.037 ;
     RECT  26.7 36.037 27.48 36.421 ;
     RECT  0.144 36.901 0.168 36.997 ;
     RECT  2.4 34.835 16.68 37.093 ;
     RECT  18.6 35.939 19.992 37.093 ;
     RECT  18.48 37.093 19.992 37.139 ;
     RECT  0.144 36.997 0.216 37.429 ;
     RECT  2.4 37.093 16.872 37.475 ;
     RECT  2.4 37.475 16.68 37.573 ;
     RECT  0.144 37.429 0.504 38.867 ;
     RECT  2.304 37.573 16.68 39.539 ;
     RECT  2.4 39.539 16.68 40.069 ;
     RECT  0.144 38.867 0.216 40.403 ;
     RECT  0.192 40.403 0.216 40.597 ;
     RECT  2.4 40.069 17.4 41.171 ;
     RECT  18.48 37.139 19.032 41.651 ;
     RECT  0.192 40.597 0.264 41.893 ;
     RECT  21.024 35.027 21.612 42.133 ;
     RECT  0.144 41.893 0.264 42.323 ;
     RECT  26.7 36.421 27.528 42.565 ;
     RECT  2.4 41.171 17.064 42.899 ;
     RECT  18.48 41.651 18.912 42.997 ;
     RECT  20.64 42.133 21.612 43.379 ;
     RECT  26.592 42.565 27.528 43.379 ;
     RECT  0.144 42.323 0.168 44.149 ;
     RECT  0.144 44.149 0.216 44.435 ;
     RECT  2.4 42.899 16.68 44.437 ;
     RECT  18.384 42.997 18.912 44.483 ;
     RECT  21.024 43.379 21.612 44.725 ;
     RECT  20.064 44.725 21.612 44.771 ;
     RECT  24 35.891 24.312 44.869 ;
     RECT  0.144 44.435 0.168 44.963 ;
     RECT  2.4 44.437 17.112 45.059 ;
     RECT  18.6 44.483 18.912 45.973 ;
     RECT  21.072 44.771 21.612 46.211 ;
     RECT  0.144 46.261 0.168 46.643 ;
     RECT  24 44.869 25.224 46.741 ;
     RECT  18.48 45.973 18.912 47.411 ;
     RECT  24 46.741 25.608 48.133 ;
     RECT  26.7 43.379 27.528 48.133 ;
     RECT  24 48.133 27.528 48.421 ;
     RECT  2.4 45.059 17.016 48.949 ;
     RECT  2.4 48.949 17.112 49.091 ;
     RECT  18.6 47.411 18.912 49.525 ;
     RECT  21.3 46.211 21.612 50.053 ;
     RECT  20.064 44.771 20.088 50.101 ;
     RECT  21.3 50.053 22.056 50.101 ;
     RECT  23.76 48.421 27.528 50.101 ;
     RECT  2.4 49.091 17.016 50.387 ;
     RECT  9.936 50.387 17.016 50.533 ;
     RECT  18 49.525 18.912 50.533 ;
     RECT  9.936 50.533 18.912 50.629 ;
     RECT  9.936 50.629 19.032 50.677 ;
     RECT  20.064 50.101 22.056 50.677 ;
     RECT  9.936 50.677 22.056 50.867 ;
     RECT  21.072 50.867 22.056 51.253 ;
     RECT  23.52 50.101 27.528 51.253 ;
     RECT  2.4 50.387 8.76 51.347 ;
     RECT  9.936 50.867 19.992 51.491 ;
     RECT  9.936 51.491 17.256 51.971 ;
     RECT  18.24 51.491 19.992 51.971 ;
     RECT  9.936 51.971 10.968 52.019 ;
     RECT  3.888 51.347 8.76 52.595 ;
     RECT  2.4 51.347 2.808 53.027 ;
     RECT  11.952 51.971 17.256 53.075 ;
     RECT  9.936 52.019 10.812 53.315 ;
     RECT  4.08 52.595 8.76 53.555 ;
     RECT  12.288 53.075 17.256 53.603 ;
     RECT  15.648 53.603 17.256 54.179 ;
     RECT  18.24 51.971 19.608 54.179 ;
     RECT  21.072 51.253 27.528 54.373 ;
     RECT  4.08 53.555 8.112 54.755 ;
     RECT  12.288 53.603 14.664 54.755 ;
     RECT  18.24 54.179 19.032 54.755 ;
     RECT  4.704 54.755 8.112 54.803 ;
     RECT  21.072 54.373 27.816 54.851 ;
     RECT  12.288 54.755 13.512 54.899 ;
     RECT  6.816 54.803 8.112 54.947 ;
     RECT  4.704 54.803 5.544 55.331 ;
     RECT  15.9 54.179 17.256 55.429 ;
     RECT  4.704 55.331 5.412 55.907 ;
     RECT  21.072 54.851 27.528 56.005 ;
     RECT  14.64 54.755 14.664 56.245 ;
     RECT  15.792 55.429 17.256 56.245 ;
     RECT  0.144 56.245 0.168 56.435 ;
     RECT  20.976 56.005 27.528 56.437 ;
     RECT  7.008 54.947 8.112 56.483 ;
     RECT  14.64 56.245 17.256 56.483 ;
     RECT  20.256 56.437 27.528 56.819 ;
     RECT  12.864 54.899 13.512 57.059 ;
     RECT  14.64 56.483 16.44 57.059 ;
     RECT  18.6 54.755 19.032 57.059 ;
     RECT  20.88 56.819 27.528 57.059 ;
     RECT  15.12 57.059 16.44 57.445 ;
     RECT  15.12 57.445 16.584 57.541 ;
     RECT  20.88 57.059 22.632 57.635 ;
     RECT  24 57.059 27.432 57.635 ;
     RECT  20.88 57.635 22.2 57.827 ;
     RECT  25.584 57.635 27.432 57.971 ;
     RECT  20.88 57.827 21.72 58.019 ;
     RECT  21.168 58.019 21.72 58.163 ;
     RECT  15.12 57.541 16.776 58.261 ;
     RECT  15.12 58.261 16.968 58.309 ;
     RECT  2.4 53.027 2.712 58.329 ;
     RECT  5.1 55.907 5.412 58.329 ;
     RECT  7.8 56.483 8.112 58.329 ;
     RECT  10.5 53.315 10.812 58.329 ;
     RECT  18.6 57.059 18.912 58.329 ;
     RECT  21.168 58.163 21.612 58.329 ;
     RECT  24 57.635 24.312 58.329 ;
     RECT  2.4 58.329 2.52 58.343 ;
     RECT  5.1 58.329 5.22 58.343 ;
     RECT  7.8 58.329 7.92 58.343 ;
     RECT  10.5 58.329 10.62 58.343 ;
     RECT  13.2 57.059 13.512 58.343 ;
     RECT  18.6 58.329 18.72 58.343 ;
     RECT  21.168 58.329 21.42 58.343 ;
     RECT  24 58.329 24.12 58.343 ;
     RECT  15.12 58.309 17.064 58.597 ;
     RECT  14.64 58.597 17.16 58.645 ;
     RECT  26.496 57.971 27.432 58.691 ;
     RECT  21.168 58.343 21.192 59.315 ;
     RECT  26.496 58.691 27.192 60.371 ;
     RECT  27.168 60.371 27.192 60.419 ;
     RECT  14.16 58.645 17.16 60.396 ;
     RECT  14.184 60.396 14.256 60.432 ;
     RECT  14.28 60.396 14.352 60.432 ;
     RECT  14.376 60.396 14.448 60.432 ;
     RECT  14.472 60.396 14.544 60.432 ;
     RECT  14.568 60.396 14.64 60.432 ;
     RECT  14.664 60.396 14.736 60.432 ;
     RECT  14.76 60.396 14.832 60.432 ;
     RECT  14.856 60.396 14.928 60.432 ;
     RECT  14.952 60.396 15.024 60.432 ;
     RECT  15.048 60.396 15.12 60.432 ;
     RECT  15.144 60.396 15.216 60.432 ;
     RECT  15.24 60.396 15.312 60.432 ;
     RECT  15.336 60.396 15.408 60.432 ;
     RECT  15.432 60.396 15.504 60.432 ;
     RECT  15.528 60.396 15.6 60.432 ;
     RECT  15.624 60.396 15.696 60.432 ;
     RECT  15.72 60.396 15.792 60.432 ;
     RECT  15.816 60.396 15.888 60.432 ;
     RECT  15.912 60.396 15.984 60.432 ;
     RECT  16.008 60.396 16.08 60.432 ;
     RECT  16.104 60.396 16.176 60.432 ;
     RECT  16.2 60.396 16.272 60.432 ;
     RECT  16.296 60.396 16.368 60.432 ;
     RECT  16.392 60.396 16.464 60.432 ;
     RECT  16.488 60.396 16.56 60.432 ;
     RECT  16.584 60.396 16.656 60.432 ;
     RECT  16.68 60.396 16.752 60.432 ;
     RECT  16.776 60.396 16.848 60.432 ;
     RECT  16.872 60.396 16.944 60.432 ;
     RECT  16.968 60.396 17.04 60.432 ;
     RECT  17.064 60.396 17.136 60.432 ;
     RECT  8.112 2.151 9.504 2.185 ;
     RECT  8.112 2.185 9.552 2.339 ;
     RECT  8.112 2.339 10.368 3.349 ;
     RECT  5.736 2.725 7.056 3.205 ;
     RECT  5.88 3.205 7.056 3.301 ;
     RECT  6.024 3.301 7.056 3.733 ;
     RECT  8.112 3.349 10.272 3.637 ;
     RECT  8.76 3.637 10.272 6.085 ;
     RECT  8.76 6.085 10.176 6.757 ;
     RECT  8.808 6.757 10.176 6.805 ;
     RECT  11.784 7.909 13.2 12.853 ;
     RECT  0.168 9.827 0.216 10.981 ;
     RECT  0.216 12.659 0.312 13.669 ;
     RECT  11.976 12.853 13.2 15.445 ;
     RECT  12.12 15.445 13.2 18.661 ;
     RECT  0.144 15.875 0.288 16.837 ;
     RECT  0.144 17.123 0.288 18.133 ;
     RECT  0.312 17.219 0.408 18.181 ;
     RECT  14.28 17.605 15.696 18.709 ;
     RECT  14.52 18.709 15.696 19.285 ;
     RECT  14.712 19.285 15.696 19.333 ;
     RECT  14.712 19.475 15.696 20.051 ;
     RECT  14.712 20.051 15.9 22.501 ;
     RECT  0.696 20.773 2.208 21.203 ;
     RECT  20.64 21.251 21.3 22.741 ;
     RECT  13.512 21.635 14.496 22.067 ;
     RECT  13.512 22.067 14.688 23.317 ;
     RECT  18.912 22.741 20.304 23.411 ;
     RECT  20.328 22.741 21.3 23.411 ;
     RECT  18.912 23.411 21.3 23.701 ;
     RECT  18.912 23.701 19.968 24.803 ;
     RECT  19.992 23.701 21.3 24.757 ;
     RECT  24.312 23.893 25.776 27.397 ;
     RECT  16.212 24.901 17.376 29.029 ;
     RECT  21.612 25.045 22.848 25.571 ;
     RECT  22.872 25.045 24 25.525 ;
     RECT  0.216 25.187 0.312 26.149 ;
     RECT  17.4 27.107 18.6 29.029 ;
     RECT  24.504 27.397 25.776 27.587 ;
     RECT  24.312 27.587 25.776 28.211 ;
     RECT  16.344 29.029 17.376 29.461 ;
     RECT  17.4 29.029 18.432 30.275 ;
     RECT  1.176 29.461 2.304 29.509 ;
     RECT  1.272 29.509 2.304 29.651 ;
     RECT  0.504 29.651 2.304 30.949 ;
     RECT  1.176 30.949 2.304 31.091 ;
     RECT  16.68 34.693 18 35.075 ;
     RECT  16.68 35.075 18.192 35.939 ;
     RECT  19.992 35.845 21.024 37.139 ;
     RECT  16.68 35.939 16.872 37.093 ;
     RECT  18.48 35.939 18.6 37.093 ;
     RECT  17.4 40.069 18.48 41.171 ;
     RECT  0.144 40.403 0.192 41.893 ;
     RECT  17.064 41.171 18.48 42.899 ;
     RECT  18.384 42.899 18.48 42.997 ;
     RECT  20.64 43.379 21.024 44.725 ;
     RECT  26.592 43.379 26.7 44.869 ;
     RECT  17.112 44.437 18.384 44.483 ;
     RECT  17.112 44.483 18.6 45.059 ;
     RECT  18.912 44.725 20.064 50.629 ;
     RECT  20.088 44.771 21.072 46.211 ;
     RECT  25.224 44.869 26.7 46.741 ;
     RECT  0.144 44.963 0.168 46.261 ;
     RECT  17.016 45.059 18.6 45.973 ;
     RECT  17.016 45.973 18.48 47.411 ;
     RECT  20.088 46.211 21.3 50.101 ;
     RECT  25.608 46.741 26.7 48.133 ;
     RECT  17.112 48.949 18.6 49.091 ;
     RECT  17.016 49.091 18.6 49.525 ;
     RECT  17.016 49.525 18 50.533 ;
     RECT  22.056 50.101 23.52 51.253 ;
     RECT  8.76 50.387 9.936 53.315 ;
     RECT  19.032 50.629 20.064 50.677 ;
     RECT  19.992 50.867 21.072 51.971 ;
     RECT  2.808 51.347 3.888 52.595 ;
     RECT  17.256 51.491 18.24 54.755 ;
     RECT  10.968 51.971 11.952 52.019 ;
     RECT  19.608 51.971 21.072 54.179 ;
     RECT  10.812 52.019 11.952 53.075 ;
     RECT  2.808 52.595 4.08 53.027 ;
     RECT  2.712 53.027 4.08 54.755 ;
     RECT  10.812 53.075 12.288 54.899 ;
     RECT  14.664 53.603 15.648 54.179 ;
     RECT  14.664 54.179 15.9 55.429 ;
     RECT  13.512 54.755 14.64 57.059 ;
     RECT  17.256 54.755 18.6 56.483 ;
     RECT  5.544 54.803 6.816 54.947 ;
     RECT  5.544 54.947 7.008 55.331 ;
     RECT  14.664 55.429 15.792 56.245 ;
     RECT  19.032 56.437 20.256 56.819 ;
     RECT  16.44 56.483 16.776 57.445 ;
     RECT  22.632 57.059 24 57.635 ;
     RECT  16.584 57.445 16.776 57.541 ;
     RECT  24.312 57.635 25.584 57.971 ;
  END
END ot_s81_cfg7_seq_bfp
END LIBRARY
